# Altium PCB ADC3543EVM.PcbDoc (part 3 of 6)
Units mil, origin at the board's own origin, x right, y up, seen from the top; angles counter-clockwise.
Board outline 3900 x 2716.54 mil, 10 copper layers (Top Layer, L2 GND, L3 PWR, L4 GND, L5 SIG, L6 GND, L7 GND, L8 PWR, L9 GND, Bottom Layer), stack 61.2 mil thick; 352 components, 249 nets, 1505 pads, 904 vias.

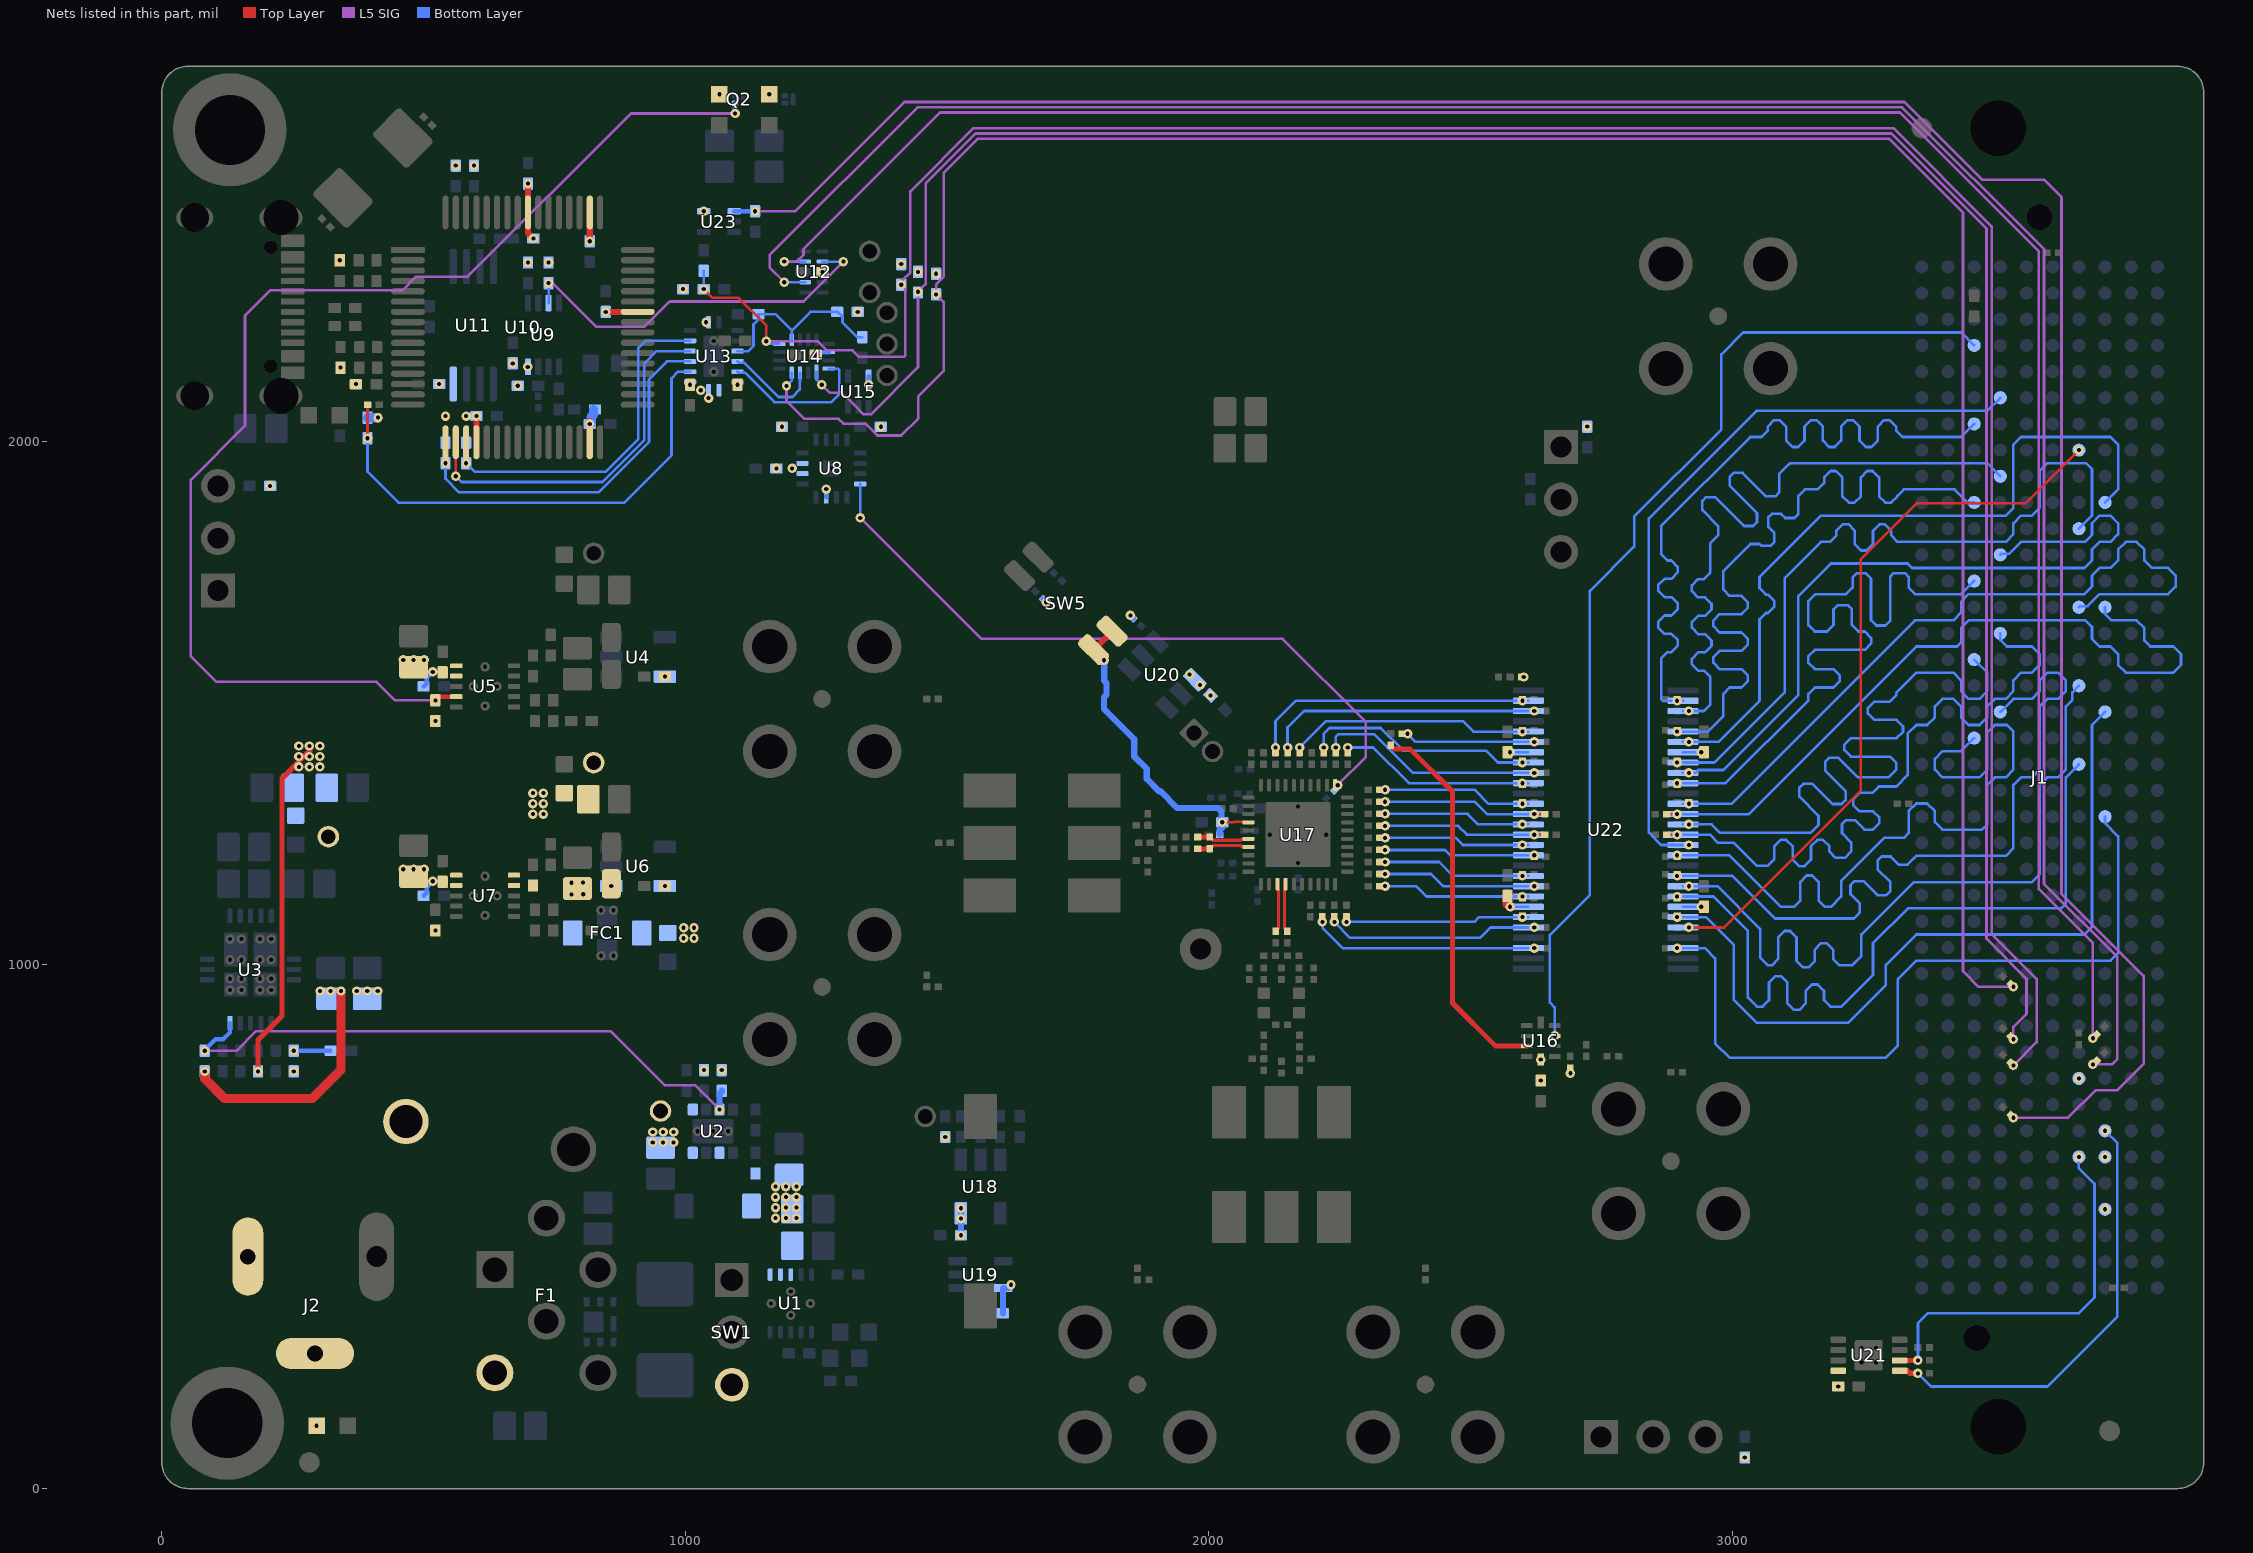
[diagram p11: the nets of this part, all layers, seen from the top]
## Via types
v1: diameter 18, hole 8, Top Layer to Bottom Layer, tented both sides, 891 vias
v2: diameter 40, hole 20, Top Layer to Bottom Layer, tented both sides, 9 vias
v3: diameter 18, hole 8, Top Layer to Bottom Layer, tented bottom, 4 vias

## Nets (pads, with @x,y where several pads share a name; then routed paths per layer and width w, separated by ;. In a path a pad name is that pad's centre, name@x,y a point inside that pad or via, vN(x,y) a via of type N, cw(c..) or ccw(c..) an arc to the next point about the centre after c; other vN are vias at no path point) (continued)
1p8V_BUFVCC: C29.2 C81.2 C82.2 C83.2 C84.2 FC1.3 R138.2 U22.7 U22.22 U22.35 U22.50 | length 181.9
  Top Layer w5: C81.2@2570,1406.28 v1(2575,1406.28) ; v1(2940.28,1111) C83.2@2945.28,1111 ; v1(2940.28,1406.28) C82.2@2945.28,1406.28
  Top Layer w8: R138.2@2597.05,1550 v1(2601.05,1550)
  Top Layer w18: C84.2@2570,1131.85 2570,1116 v1(2575,1111)
  Bottom Layer w5: v1(2575,1111) U22.35@2610,1111 ; v1(2575,1406.28) U22.50@2610,1406.28 ; U22.22@2905.28,1111 v1(2940.28,1111) ; U22.7@2905.28,1406.28 v1(2940.28,1406.28)
  other v1: 996.48,1051.05 1016.48,1051.05 996.48,1071.05 1016.48,1071.05
1p8V_IOVDD: C27.2 C69.2 FB3.2 PP4.1 U8.4 U17.31 | length 1351.9
  Top Layer w5: U17.31@2240.81,1343.29 v1(2245.81,1343.29)
  L5 SIG w5: v1(1334.01,1853.77) 1565.07,1622.71 2140.67,1622.71 2299.43,1463.94 2299.43,1396.91 v1(2245.81,1343.29)
  Bottom Layer w5: v1(1334.01,1853.77) U8.4@1334.01,1918.77
  Bottom Layer w8: C69.2@2239.47,1333.78 2245.81,1340.12 v1(2245.81,1343.29)
  other v1: 708.74,1288.25 728.74,1288.25 708.74,1308.25 728.74,1308.25 708.74,1328.25 728.74,1328.25
1p8V_LVLSHIFT: C26.2 C47.2 C73.2 FC1.1 R26.1 R27.2 R55.1 R58.2 R59.2 R60.2 R69.2 R96.2 R110.2 R112.1 R120.2 R148.1 U6.1 U7.9 U7.10 U13.15 U15.5 U18.5 U19.5 U23.5 | length 158.5
  Top Layer w5: v1(2690.22,793.22) R69.2@2690.22,803.22
  Bottom Layer w5: v1(1099.53,2108.3) U13.15@1099.53,2113.3
  Bottom Layer w9: v1(1350,2108.49) U15.5@1350,2124.23
  Bottom Layer w12: C73.2@1526.23,483.68 v1(1526.21,535.51) ; R112.1@1606.46,334.78 1606.69,335.01 1606.69,382.82 U19.5@1606.92,383.05 1615.82,383.05 ccw(c1615.82,389.15) 1616.84,383.13 U19.5@1621.84,388.13 ; R120.2@1683.8,1697.91 1688.18,1693.52 1689.41,1693.52 v1(1688.8,1692.91) ; U19.5@1621.84,388.13 ccw(c1615.82,389.15) v1(1621.93,389.15) 1621.93,388.22 U19.5@1621.84,388.13
  other v1: 1526.26,483.65 1526.21,515.51 1496.21,671.34 782.74,1134.69 805,1135 858.46,1150.75 782.43,1156.95 804.69,1157.26 2722.46,2028.25 1329.09,2247.34 995.55,2290.74 1478.89,2320.15 1444.21,2323.69 1412.13,2338.64 1034.92,2439.48
2p3V: C14.2 C15.2 C18.2 C19.2 C24.2 C25.2 FB1.2 PP2.1 R11.2 R15.2 R25.2 U5.1 U5.2 U7.1 U7.2 | length 854.7
  Top Layer w8: v1(460.98,1182.66) 474.98,1168.66 C24.2@480.98,1168.66 ; v1(460.98,1582.66) 474.98,1568.66 C18.2@480.98,1568.66 ; v1(480.98,1182.66) C24.2@480.98,1168.66 ; v1(480.98,1582.66) C18.2@480.98,1568.66 ; v1(500.98,1182.66) 486.98,1168.66 C24.2@480.98,1168.66 ; v1(500.98,1582.66) 486.98,1568.66 C18.2@480.98,1568.66
  Top Layer w10: v1(183.89,796.75) 183.89,856.68 229.77,902.57 229.77,1356.43 282.4,1409.06
  Bottom Layer w8: R25.2@499.93,1132.05 500.25,1132.05 506.09,1137.89 506.09,1148.51 v1(517.4,1159.81) ; R15.2@499.93,1532.05 500.25,1532.05 506.09,1537.89 506.09,1548.51 v1(517.4,1559.81)
  other v1: 261.89,1378.18 281.89,1378.18 301.89,1378.18 261.89,1398.18 281.89,1398.18 301.89,1398.18 261.89,1418.18 281.89,1418.18 301.89,1418.18
3p3V_AUX: J1.D32
  other v1: 3661.42,783.27
3p3V_EEPROM: C80.2 U21.8
  other v1: 3201.8,194.99
3p3V_Utility: C7.2 C17.2 C23.2 C30.2 C31.2 C37.2 C38.2 C39.2 C40.2 C41.2 C42.2 C45.2 C46.2 C48.2 C56.2 C77.2 FB4.1 FB5.1 PP1.1 R5.2 R7.2 R9.2 R14.2 R23.2 R31.2 R32.2 R33.2 R34.1 R36.2 R37.1 R40.2 R46.2 R47.2 R48.2 R50.2 R51.2 R52.2 R53.2 R72.2 R121.2 U2.4 U2.5 U4.5 U6.5 U8.7 U8.10 U8.11 U9.8 U10.20 U10.31 U10.42 U10.50 U10.56 U11.8 U12.8@1261.85,2323.6 U13.1 U13.2 U13.8 U13.16 U14.14 U16.10 U20.4 | length 426.6
  Top Layer w11: v1(847.98,2247.34) U10.42@908.98,2247.34
  Top Layer w12: U10.20@600.91,1998.32 v1(600.91,2048.32) ; v1(699.33,2492.3) U10.56@699.33,2437.3 699.33,2397.82 v1(709.66,2387.5) ; U10.31@817.44,1998.32 v1@817.44,2038.32 ; v1(817.44,2382.3) U10.50@817.44,2437.3
  Bottom Layer w5: v1(1008.98,2108.3) U13.2@1008.98,2113.3 ; v1(1039.41,2227.47) U13.8@1044.41,2227.47
  Bottom Layer w8: v1(1249.02,2165.39) 1251.72,2165.39 1256.72,2170.39 U14.14@1274.02,2170.39
  Bottom Layer w9: U8.7@1269.05,1893.18 v1(1269.05,1908.92)
  Bottom Layer w12: v1(1849.99,1667.72) R121.2@1854.99,1662.72
  Bottom Layer w18: R51.2@392.95,2045.32 v1(412.95,2045.32) ; v1(817.44,2033.32) 819.41,2033.32 820.25,2034.16 820.25,2047 824.48,2051.23 R37.1@824.48,2060.88
  other v1: 3023.45,59.35 937.5,660.99 957.5,660.99 977.5,660.99 937.5,680.99 957.5,680.99 977.5,680.99 2633.64,779.36 251.89,796.75 1035.7,799.2 1069.29,799.2 2633.64,819.36 522.48,1065.91 960.83,1150.75 522.48,1465.91 2002.96,1514.75 1982.96,1534.75 960.83,1550.75 1962.96,1554.75 206.85,1915 1173.78,1948.29 1203.78,1948.29 1184.41,2027.82 1373.38,2027.82 541.85,2048.32 581.22,2048.32 1044.41,2082.55 1029.41,2097.55 679.65,2106.22 370.63,2109.54 529.61,2109.54 341.37,2140.87 699.03,2142.22 670.29,2148.91 1261.85,2323.6 699.33,2341.64 738.7,2341.64 340,2345.76 561.54,2526.67 596.22,2526.67
3p3VU_PG: R5.1 R10.1 U2.7 U3.24 | length 1180.4
  L5 SIG w5: v1(81.89,836.12) 142.5,836.12 179.96,873.58 857.24,873.58 960.83,770 1019.12,770 v1(1065.29,723.83)
  Bottom Layer w8: v1(81.89,836.12) 81.89,838.09 87.73,843.93 88.74,843.93 103.07,858.26 117.42,858.26 130.21,871.05 U3.24@130.21,888.94
  Bottom Layer w12: v1(1065.29,723.83) 1065.29,753.86 1069.29,757.86 R5.1@1069.29,759.83
12V: C2.2 C3.2 C6.2 C9.2 C10.2 D1.1 D3.1 D4.1 D5.1 R6.2 R10.2 U1.6 U1.7 U1.8 U2.2 U3.18 | length 462.9
  Top Layer w18: v1(81.89,796.75) 81.89,783.11 120,745 287.48,745 342.26,799.78 v1(342.26,950.2)
  other v1: 295.33,119.85 1172.07,516.64 1192.07,516.64 1212.07,516.64 1172.07,536.64 1192.07,536.64 1212.07,536.64 1172.07,556.64 1192.07,556.64 1212.07,556.64 1172.07,576.64 1192.07,576.64 1212.07,576.64 302.26,950.2 322.26,950.2 372.26,950.2 392.26,950.2 412.26,950.2 1065,2663.11 1160,2663.11
12V_FMC: J1.C35 J1.C37 SW1.3
  other v1: 3711.42,533.27 3711.42,633.27
AIN_N: R84.2 U17.14 | length 93.3
  Top Layer w6.1: U17.14@2146.32,1154.31 2146.32,1146.44 2144,1144.11 2144,1070.85 2149.75,1065.1 R84.2@2149.75,1064.31
AIN_P: R76.2 U17.13 | length 93.3
  Top Layer w6.1: R76.2@2127.15,1064.31 2127.15,1065.1 2132.9,1070.85 2132.9,1144.11 2130.57,1146.44 U17.13@2130.57,1154.31
AVDD_PG: Q2.1@1095,2646.22 R14.1 U5.4 | length 2355.2
  Top Layer w8: v1(522.48,1505.28) 522.48,1506.52 528.32,1512.36 U5.4@562.48,1512.36
  L5 SIG w5: v1(522.48,1505.28) 445.42,1505.28 410,1540.7 104.24,1540.7 55.51,1589.43 55.51,1926.56 158.81,2029.87 158.81,2240.25 206.85,2288.29 459.46,2288.29 485.67,2314.49 584.28,2314.49 896.01,2626.22 v1(1095,2626.22)
  Bottom Layer w9.7: v1(1095,2626.22) Q2.1@1095,2646.22
CLK_N: C55.2 R65.1 U17.7 | length 100.5
  Top Layer w6.1: R65.1@2001.99,1221.75 2008.24,1228 2039.34,1228 2060.84,1228 2062.78,1226.06 2074.57,1226.06 U17.7@2075.45,1225.18
  Top Layer w9.7: C55.2@1978.2,1221.75 1994.35,1221.75 1994.9,1222.3 R65.1@2001.2,1222.3
CLK_P: C49.2 R65.2 U17.6 | length 101
  Top Layer w6.1: R65.2@2001.2,1244.35 2001.99,1244.35 2008.24,1238.1 2035.16,1238.1 2060.84,1238.1 2062.78,1240.04 2074.57,1240.04 U17.6@2075.45,1240.92
  Top Layer w9.7: C49.2@1978.2,1244.35 R65.2@2001.2,1244.35
CTRL: C78.2 C79.2 SW5.3 SW5.4 U17.4 | length 608.6
  Top Layer w5: v1(2025.45,1272.42) 2047.87,1272.42 2048.62,1273.17 2062.29,1273.17 2063.04,1272.42 U17.4@2075.45,1272.42
  Top Layer w12: v1(1799.63,1582.07) SW5.4@1779.63,1602.07 1790.21,1612.65 SW5.3@1814.99,1637.43
  Bottom Layer w12: v1@1799.8,1582.1 1799.8,1542.89 1804.28,1538.42 1804.28,1516.25 1799.37,1511.34 1799.37,1489.17 1857.18,1431.36 1857.18,1398.19 1880.89,1374.48 1880.89,1355.37 1904.59,1331.66 1907.61,1331.66 1939.61,1299.66 2006.69,1299.66 2006.93,1299.91 2016.93,1299.91 2023.96,1292.88 2023.96,1273.92 v1(2025.45,1272.42) 2025.45,1262.58 2020.45,1257.58 C79.2@2020.45,1249.42
D0: J1.H7 R140.2 U22.2 | length 1436.9
  Bottom Layer w5: U22.2@2905.28,1504.7 v1(2893.99,1504.7) 2866.64,1504.7 2863.71,1507.63 2863.71,1547.76 2863.71,1585.26 2875.96,1597.51 2883.21,1597.51 2895.46,1609.76 2895.46,1620.26 2883.21,1632.51 2870.16,1632.51 2857.91,1644.76 2857.91,1655.26 2870.16,1667.51 2883.21,1667.51 2895.46,1679.76 2895.46,1690.26 2883.21,1702.51 2870.16,1702.51 2857.91,1714.76 2857.91,1725.26 2870.16,1737.51 2882.98,1737.51 2895.23,1749.76 2895.23,1760.26 2882.98,1772.51 2875.96,1772.51 2863.71,1784.76 2863.71,1808.27 2863.71,1838.07 3033.91,2008.27 3052.59,2008.27 3055.09,2008.27 3067.34,2020.52 3067.34,2028.28 3079.59,2040.53 3090.09,2040.53 3102.34,2028.28 3102.34,2001.39 3114.59,1989.14 3125.09,1989.14 3137.34,2001.39 3137.34,2028.28 3149.59,2040.53 3160.09,2040.53 3172.34,2028.28 3172.34,2001.39 3184.59,1989.14 3195.09,1989.14 3207.34,2001.39 3207.34,2028.28 3219.59,2040.53 3230.09,2040.53 3242.34,2028.28 3242.34,2001.39 3254.59,1989.14 3265.09,1989.14 3277.34,2001.39 3277.34,2028.28 3289.59,2040.53 3300.09,2040.53 3312.34,2028.28 3312.34,2020.52 3324.59,2008.27 3361.42,2008.27 3436.42,2008.27 J1.H7@3461.42,2033.27
D1: J1.G9 R142.2 U22.3 | length 1436.9
  Bottom Layer w5: U22.3@2905.28,1485.02 v1(2916.56,1485.02) 2945.02,1485.02 2957.51,1497.51 2957.51,1547.2 2957.51,1549.7 2945.26,1561.95 2934.35,1561.95 2922.1,1574.2 2922.1,1584.7 2934.35,1596.95 2947.45,1596.95 2959.7,1609.2 2959.7,1619.7 2947.45,1631.95 2934.35,1631.95 2922.1,1644.2 2922.1,1654.7 2934.35,1666.95 2947.45,1666.95 2959.7,1679.2 2959.7,1689.7 2947.45,1701.95 2934.35,1701.95 2922.1,1714.2 2922.1,1724.7 2934.35,1736.95 2945.26,1736.95 2957.51,1749.2 2957.51,1797.33 2957.51,1805.77 2970.87,1819.13 2972.64,1820.9 2972.64,1838.22 2942.16,1868.7 2942.16,1886.02 2949.59,1893.44 2966.91,1893.44 3021.98,1838.37 3039.31,1838.37 3046.73,1845.8 3046.73,1863.12 2994.66,1915.19 2994.66,1932.52 3002.09,1939.94 3019.41,1939.94 3064.21,1895.15 3081.53,1895.15 3088.95,1902.57 3088.95,1919.9 3088.95,1937.22 3108.09,1956.35 3110,1958.27 3486.42,1958.27 J1.G9@3511.42,1933.27
D2: J1.H10 R144.2 U22.5 | length 1436.9
  Bottom Layer w5: U22.5@2905.28,1445.65 2952.69,1445.65 2982.27,1475.22 2982.27,1480.24 2982.27,1517.74 2994.52,1529.99 3017.1,1529.99 3029.35,1542.24 3029.35,1552.74 3017.1,1564.99 2975.47,1564.99 2963.22,1577.24 2963.22,1587.74 2975.47,1599.99 3017.1,1599.99 3029.35,1612.24 3029.35,1622.74 3017.1,1634.99 2975.47,1634.99 2963.22,1647.24 2963.22,1657.74 2975.47,1669.99 3017.1,1669.99 3029.35,1682.24 3029.35,1692.74 3017.1,1704.99 2994.52,1704.99 2982.27,1717.24 2982.27,1719.89 2982.27,1752.26 3007.54,1777.53 3034.06,1804.05 3051.38,1804.05 3054.9,1800.53 3072.22,1800.53 3079.65,1807.96 3079.65,1825.28 3067.98,1836.95 3067.98,1854.27 3075.4,1861.7 3092.73,1861.7 3100.88,1853.55 3118.2,1853.55 3125.63,1860.97 3125.63,1878.29 3125.63,1895.62 3138.27,1908.27 3139.36,1908.27 3160.09,1908.27 3162.59,1908.27 3174.84,1920.52 3174.84,1931.16 3187.09,1943.41 3197.59,1943.41 3209.84,1931.16 3209.84,1895.14 3222.09,1882.89 3232.59,1882.89 3244.84,1895.14 3244.84,1931.16 3257.09,1943.41 3267.59,1943.41 3279.84,1931.16 3279.84,1895.14 3292.09,1882.89 3302.59,1882.89 3314.84,1895.14 3314.84,1896.02 3327.09,1908.27 3348.03,1908.27 3423.82,1908.27 3448.82,1883.27 J1.H10@3461.42,1883.27
  other v1: 2893.99,1445.65
D3: J1.C10 R146.2 U22.6 | length 1436.9
  Bottom Layer w5: U22.6@2905.28,1425.96 v1(2916.56,1425.96) 2973.17,1425.96 3051.38,1504.17 3051.38,1622.51 3051.38,1660.01 3063.63,1672.26 3067.7,1672.26 3079.95,1684.51 3079.95,1695.01 3067.7,1707.26 3063.63,1707.26 3051.38,1719.51 3051.38,1733.05 3051.38,1740.84 3168.81,1858.27 3521.77,1858.27 3536.42,1872.91 3536.42,1886.02 3536.42,1993.62 3551.06,2008.27 3721.77,2008.27 3736.42,1993.62 3736.42,1908.27 J1.C10@3711.42,1883.27
D4: J1.D11 R151.2 U22.8 | length 1436.9
  Bottom Layer w5: U22.8@2905.28,1386.59 2965.15,1386.59 3100,1521.44 3100,1739.28 3168.98,1808.27 3183.47,1808.27 3185.97,1808.27 3198.22,1820.52 3198.22,1829.54 3210.47,1841.79 3220.97,1841.79 3233.22,1829.54 3233.22,1803.93 3245.47,1791.68 3255.97,1791.68 3268.22,1803.93 3268.22,1829.12 3280.47,1841.37 3290.97,1841.37 3303.22,1829.12 3303.22,1820.52 3315.47,1808.27 3361.1,1808.27 3521.77,1808.27 3536.42,1822.91 3536.42,1843.62 3551.07,1858.27 3571.77,1858.27 3586.42,1872.92 3586.42,1943.62 3601.07,1958.27 3675.16,1958.27 3686.42,1947.01 3686.42,1858.27 J1.D11@3661.42,1833.27
  other v1: 2893.99,1386.59
D5: J1.G12 R153.2 U22.9 | length 1446.1
  Bottom Layer w5: U22.9@2905.28,1366.91 2928.9,1366.91 2934.28,1372.29 2982.23,1372.29 3125.63,1515.7 3125.63,1704.82 3187.64,1766.83 3334.51,1766.83 3343.07,1758.27 3671.77,1758.27 3686.42,1772.91 3686.42,1793.62 3701.06,1808.27 3721.77,1808.27 3736.42,1822.91 3736.42,1843.62 3721.77,1858.27 3701.06,1858.27 3686.42,1843.62 3686.42,1821.1 3673.58,1808.27 3551.06,1808.27 3527.95,1785.16 3513.31,1785.16 J1.G12@3511.42,1783.27
  other v1: 2916.56,1366.91
D6: J1.H13 R155.2 U22.10 | length 1441.3
  Bottom Layer w5: U22.10@2905.28,1347.22 2986.88,1347.22 3144.84,1505.19 3144.84,1517.69 3157.09,1529.94 3192.59,1529.94 3204.84,1542.19 3204.84,1552.69 3192.59,1564.94 3157.09,1564.94 3144.84,1577.19 3144.84,1589.69 3157.09,1601.94 3252.59,1601.94 3264.84,1614.19 3264.84,1624.69 3252.59,1636.94 3240.09,1636.94 3227.84,1649.19 3227.84,1679.63 3220.53,1686.94 3200.67,1686.94 3192.84,1679.11 3192.84,1649.19 3180.59,1636.94 3157.09,1636.94 3144.84,1649.19 3144.84,1694.89 3158.22,1708.27 3217.09,1708.27 3229.34,1720.52 3229.34,1739.75 3237.86,1748.27 3253.9,1748.27 3264.34,1737.82 3264.34,1658.62 3274.7,1648.27 3291.7,1648.27 3301.35,1657.92 3301.35,1741.92 3307.69,1748.27 3328.98,1748.27 3336.35,1740.9 3336.35,1720.52 3348.6,1708.27 3436.42,1708.27 J1.H13@3461.42,1733.27
  other v1: 2893.99,1347.22
D7: J1.D14 R157.2 U22.12 | length 1446.1
  Bottom Layer w5: U22.12@2905.28,1307.85 v1(2916.56,1307.85) 2997.92,1307.85 3348.33,1658.27 3421.77,1658.27 3436.42,1672.91 3436.42,1693.62 3451.07,1708.27 3671.77,1708.27 3686.42,1722.91 3686.42,1743.62 3701.06,1758.27 3721.77,1758.27 3736.42,1772.91 3736.42,1793.62 3751.06,1808.27 3771.77,1808.27 3786.42,1793.62 3786.42,1772.51 3800.66,1758.27 3831.77,1758.27 3846.42,1743.62 3846.42,1722.91 3831.77,1708.27 3702.95,1708.27 3701.06,1708.27 3677.95,1685.16 3663.31,1685.16 J1.D14@3661.42,1683.27
D8: J1.C14 R159.2 U22.13 | length 1437.9
  Top Layer w5: R159.2@2873.99,1288.17 v1(2893.99,1288.17)
  Bottom Layer w5: U22.13@2905.28,1288.17 3030.96,1288.17 3351.07,1608.27 3428.88,1608.27 3436.42,1615.81 3436.42,1643.62 3451.07,1658.27 3511.41,1658.27 3673.82,1658.27 3686.42,1645.66 3686.42,1622.91 3701.07,1608.27 3721.77,1608.27 3736.42,1593.62 3736.42,1572.92 3751.06,1558.27 3841.77,1558.27 3856.42,1572.91 3856.42,1593.62 3841.77,1608.27 3797.85,1608.27 3786.42,1619.7 3786.42,1643.62 3771.77,1658.27 3723.82,1658.27 3711.42,1670.67 J1.C14@3711.42,1683.27
D9: J1.H16 R161.2 U22.14 | length 1438.9
  Bottom Layer w5: U22.14@2905.28,1268.48 v1(2916.56,1268.48) 2959.81,1268.48 2975.47,1252.83 3149.51,1252.83 3162.4,1265.71 3164.17,1267.48 3164.17,1284.81 3127.66,1321.32 3127.66,1338.64 3135.08,1346.07 3152.41,1346.07 3191.16,1307.31 3208.49,1307.31 3215.91,1314.73 3215.91,1332.06 3177.16,1370.81 3177.16,1388.14 3184.58,1395.56 3201.9,1395.56 3239.2,1358.27 3264.34,1358.27 3298.13,1358.27 3312.78,1372.92 3312.78,1383.27 3312.78,1385.77 3300.53,1398.02 3225.84,1398.02 3213.59,1410.27 3213.59,1420.77 3225.84,1433.02 3313.26,1433.02 3325.51,1445.27 3325.51,1455.77 3313.26,1468.02 3270.79,1468.02 3258.54,1480.27 3258.54,1490.77 3270.79,1503.02 3300.53,1503.02 3312.78,1515.27 3312.78,1518.58 3312.78,1519.98 3351.07,1558.27 3421.77,1558.27 3436.42,1543.62 3436.42,1522.92 3451.06,1508.27 3471.77,1508.27 3486.42,1522.92 3486.42,1558.27 J1.H16@3461.42,1583.27
D10: J1.G15 R163.2 U22.15 | length 1444.1
  Top Layer w5: R163.2@2873.99,1248.8 v1(2893.99,1248.8)
  Bottom Layer w5: U22.15@2905.28,1248.8 2957.11,1248.8 2972.64,1233.27 3002.62,1233.27 3046.14,1189.74 3067.5,1189.74 3079.75,1201.99 3079.75,1226.79 3092,1239.04 3102.5,1239.04 3114.75,1226.79 3114.75,1201.02 3127,1188.77 3137.5,1188.77 3149.75,1201.02 3149.75,1226.79 3162,1239.04 3172.5,1239.04 3184.75,1226.79 3184.75,1216.9 3197,1204.65 3214.32,1204.65 3226.57,1216.9 3226.57,1234.22 3209.04,1251.76 3209.04,1269.08 3216.47,1276.51 3233.79,1276.51 3252.01,1258.29 3267.96,1258.29 3280.47,1270.79 3280.47,1281.29 3268.22,1293.54 3242.45,1293.54 3230.2,1305.79 3230.2,1316.29 3242.45,1328.54 3267.25,1328.54 3279.5,1340.79 3312.78,1340.79 3334.51,1362.53 3334.51,1441.71 3351.06,1458.27 3371.77,1458.27 3386.42,1472.91 3386.42,1493.62 3401.06,1508.27 3421.77,1508.27 3436.42,1493.62 3436.42,1472.91 3451.07,1458.27 3471.77,1458.27 3486.42,1472.91 3486.42,1493.62 3501.07,1508.27 3521.77,1508.27 3536.42,1522.91 3536.42,1543.62 3551.06,1558.27 3571.77,1558.27 3586.42,1572.91 3586.42,1593.62 3571.77,1608.27 3551.06,1608.27 3523.82,1608.27 3511.42,1620.67 J1.G15@3511.42,1633.27
D11: J1.H19 R167.2 U22.17 | length 1439.9
  Bottom Layer w5: U22.17@2905.28,1209.43 2993.71,1209.43 3092.14,1111 3114.59,1111 3117.09,1111 3129.34,1123.25 3129.34,1158.6 3141.59,1170.85 3152.09,1170.85 3164.34,1158.6 3164.34,1123.25 3176.59,1111 3182.82,1111 3187.66,1111 3207.34,1130.69 3207.34,1160.52 3289.59,1242.77 3289.69,1242.67 3327.09,1242.67 3336.42,1252 3336.42,1293.62 3351.06,1308.27 3371.77,1308.27 3386.42,1293.62 3386.42,1272.91 3401.06,1258.27 3411.41,1258.27 3476.2,1258.27 3486.42,1268.48 3486.42,1343.62 3501.07,1358.27 3521.77,1358.27 3536.42,1372.91 3536.42,1445.65 3523.8,1458.27 3501.06,1458.27 3486.42,1443.62 3486.42,1372.92 3471.77,1358.27 3461.42,1358.27 3401.06,1358.27 3386.42,1372.91 3386.42,1393.62 3401.07,1408.27 3436.42,1408.27 J1.H19@3461.42,1433.27
  other v1: 2893.99,1209.43
D12: J1.G18 R169.2 U22.19 | length 1439.9
  Bottom Layer w5: U22.19@2905.28,1170.06 2999.74,1170.06 3081.08,1088.72 3231.52,1088.72 3241.17,1098.38 3242.94,1100.14 3242.94,1117.47 3225.23,1135.18 3225.23,1152.5 3232.65,1159.93 3249.98,1159.93 3276.47,1133.44 3293.79,1133.44 3301.22,1140.87 3301.22,1158.19 3277.11,1182.3 3277.11,1199.62 3284.53,1207.05 3301.86,1207.05 3317.19,1191.71 3334.51,1191.71 3346.93,1204.13 3351.07,1208.27 3521.77,1208.27 3536.42,1222.91 3536.42,1343.62 3551.06,1358.27 3571.77,1358.27 3586.42,1372.92 3586.42,1493.62 3601.07,1508.27 3621.77,1508.27 3636.42,1522.91 3636.42,1543.62 3621.77,1558.27 3601.07,1558.27 3586.42,1543.62 3586.42,1522.92 3571.77,1508.27 3536.42,1508.27 J1.G18@3511.42,1483.27
  other v1: 2893.99,1170.06
D13: J1.D17 R171.2 U22.20 | length 1440.8
  Bottom Layer w5: U22.20@2905.28,1150.37 v1(2916.56,1150.37) 2970.87,1150.37 3052.59,1068.65 3052.59,1014.37 3067.7,999.26 3072.34,999.26 3074.84,999.26 3087.09,1011.51 3087.09,1052.6 3099.34,1064.85 3109.84,1064.85 3122.09,1052.6 3122.09,1007.71 3134.34,995.46 3144.84,995.46 3157.09,1007.71 3157.09,1029.22 3169.34,1041.47 3179.84,1041.47 3192.09,1029.22 3192.09,1011.51 3204.34,999.26 3228.12,999.26 3232.59,1003.73 3246.08,1017.22 3246.08,1058.27 3346.08,1158.27 3401.06,1158.27 3571.77,1158.27 3586.42,1172.92 3586.42,1343.62 3601.07,1358.27 3621.77,1358.27 3636.42,1372.91 3636.42,1412.56 3636.42,1493.62 3648.82,1506.02 3648.82,1520.67 J1.D17@3661.42,1533.27
D14: J1.D20 R173.2 U22.21 | length 1441.1
  Bottom Layer w5: U22.21@2905.28,1130.69 2963.22,1130.69 3029.35,1064.56 3029.35,937.87 3046.73,920.49 3054.9,920.49 3057.4,920.49 3069.65,932.74 3069.65,966.38 3081.9,978.63 3092.4,978.63 3104.65,966.38 3104.65,926.67 3116.9,914.42 3127.4,914.42 3139.65,926.67 3139.65,950.41 3151.9,962.66 3162.4,962.66 3174.65,950.41 3174.65,932.74 3186.9,920.49 3202.19,920.49 3207.79,920.49 3268.22,980.92 3268.22,1041.52 3334.97,1108.27 3627.31,1108.27 3636.42,1117.37 3636.42,1358.27 J1.D20@3661.42,1383.27
  other v1: 2893.99,1130.69
D15: J1.C18 R175.2 U22.23 | length 1444.9
  Bottom Layer w5: U22.23@2905.28,1091.32 2949.59,1091.32 3002.09,1038.82 3002.09,934.32 3047.01,889.4 3220.05,889.4 3292.8,962.15 3292.8,1000.01 3351.07,1058.27 3671.77,1058.27 3686.42,1072.91 3686.42,1458.27 J1.C18@3711.42,1483.27
  other v1: 2893.99,1091.32
D16/FCLK: J1.D8 R177.2 U22.24 | length 1381.5
  Top Layer w5: v1(2916.56,1071.63) 2983.81,1071.63 3245,1332.82 3245,1775 3352.04,1882.04 3560.19,1882.04 v1(3661.42,1983.27)
D17: J1.C22 R179.2 U22.26 | length 1440.9
  Bottom Layer w5: U22.26@2905.28,1032.26 2947.23,1032.26 2966.91,1012.58 2966.91,850.46 2994.52,822.85 3292.8,822.85 3315.47,845.52 3315.47,972.67 3351.06,1008.27 3721.77,1008.27 3736.42,1022.91 3736.42,1245.67 3711.42,1270.67 J1.C22@3711.42,1283.27
  other v1: 2893.99,1032.26
DC-DC_PG: R9.1 R22.2 U3.19 | length 70.2
  Bottom Layer w8: v1(251.89,836.12) R22.2@322.11,836.12
DCLK: J1.G6 R165.2 U22.16 | length 1441.9
  Bottom Layer w5: U22.16@2905.28,1229.11 2863.71,1229.11 2840,1252.83 2840,1852.7 3045.56,2058.27 3486.42,2058.27 J1.G6@3511.42,2083.27
  other v1: 2916.56,1229.11
DCLKIN: R117.1 U16.8 | length 734.7
  Top Layer w9.7: R117.1@2347.23,1419.45 2347.23,1418.66 2353.16,1412.73 2383.41,1412.73 2465,1331.15 2465,927.49 2547.53,844.95 U16.8@2607.07,844.95
DUT_D0: R88.2 R139.1 U22.55 | length 559.4
  Top Layer w5: R88.2@2127.07,1405.33 v1(2127.07,1415.33)
  Bottom Layer w5: v1(2127.07,1415.33) 2127.07,1465.57 2166.2,1504.7 U22.55@2610,1504.7
  other v1: 2598.72,1504.7
DUT_D1: R90.2 R141.1 U22.54 | length 521.3
  Top Layer w5: R90.2@2150.07,1405.33 v1(2150.07,1415.33)
  Bottom Layer w5: v1(2150.07,1415.33) 2150.07,1453.7 2181.39,1485.02 U22.54@2610,1485.02
  other v1: 2621.28,1485.02
DUT_D2: R91.2 R143.1 U22.52 | length 476
  Top Layer w5: R91.2@2173.07,1405.33 v1(2173.07,1415.33)
  Bottom Layer w5: v1(2173.07,1415.33) 2223.31,1465.57 2485,1465.57 2504.93,1445.65 U22.52@2610,1445.65
  other v1: 2598.72,1445.65
DUT_D4: R93.2 R150.1 U22.49 | length 458.7
  Top Layer w5: R93.2@2219.07,1405.33 v1(2219.07,1415.33)
  Bottom Layer w5: v1(2219.07,1415.33) 2219.07,1441.14 2230.41,1452.48 2327.77,1452.48 2371.08,1409.17 2529.22,1409.17 2551.8,1386.59 U22.49@2610,1386.59
  other v1: 2598.72,1386.59
DUT_D5: R94.2 R152.1 U22.48 | length 431
  Top Layer w5: R94.2@2242.07,1405.33 v1(2242.07,1415.33)
  Bottom Layer w5: v1(2242.07,1415.33) 2242.07,1435.67 2247.25,1440.85 2315.31,1440.85 2389.25,1366.91 U22.48@2610,1366.91
  other v1: 2621.28,1366.91
DUT_D6: R95.2 R154.1 U22.47 | length 383.1
  Top Layer w5: R95.2@2265.07,1405.33 v1(2265.07,1415.33)
  Bottom Layer w5: v1(2265.07,1415.33) 2313.7,1415.33 2381.81,1347.22 U22.47@2610,1347.22
  other v1: 2598.72,1347.22
DUT_D7: R97.2 R156.1 U22.45 | length 294.6
  Top Layer w5: R97.2@2326.48,1334.67 v1(2336.48,1334.67)
  Bottom Layer w5: v1(2336.48,1334.67) 2507.24,1334.67 2534.06,1307.85 U22.45@2610,1307.85
  other v1: 2598.72,1307.85
DUT_D8: R98.2 R158.1 U22.44 | length 313.3
  Top Layer w5: R98.2@2326.48,1311.67 v1(2336.48,1311.67) ; v1(2621.28,1288.17) R158.1@2641.28,1288.17
  Bottom Layer w5: v1(2336.48,1311.67) 2507.65,1311.67 2531.15,1288.17 U22.44@2610,1288.17
DUT_D9: R99.2 R160.1 U22.43 | length 291.9
  Top Layer w5: R99.2@2326.48,1288.67 v1(2336.48,1288.67)
  Bottom Layer w5: v1(2336.48,1288.67) 2493.85,1288.67 2514.04,1268.48 U22.43@2610,1268.48
  other v1: 2598.72,1268.48
DUT_D10: R100.2 R162.1 U22.42 | length 310.5
  Top Layer w5: R100.2@2326.48,1265.67 v1(2336.48,1265.67) ; v1(2621.28,1248.8) R162.1@2641.28,1248.8
  Bottom Layer w5: v1(2336.48,1265.67) 2476,1265.67 2492.87,1248.8 U22.42@2610,1248.8
DUT_D11: R101.2 R166.1 U22.40 | length 287.8
  Top Layer w5: R101.2@2326.48,1219.67 v1(2336.48,1219.67)
  Bottom Layer w5: v1(2336.48,1219.67) 2450.61,1219.67 2460.85,1209.43 U22.40@2610,1209.43
  other v1: 2621.28,1209.43
DUT_D12: R102.2 R168.1 U22.38 | length 294.5
  Top Layer w5: R102.2@2326.48,1196.67 v1(2336.48,1196.67)
  Bottom Layer w5: v1(2336.48,1196.67) 2439.79,1196.67 2466.41,1170.06 U22.38@2610,1170.06
  other v1: 2598.72,1170.06
DUT_D13: R103.2 R170.1 U22.37 | length 292.8
  Top Layer w5: R103.2@2326.48,1173.67 v1(2336.48,1173.67)
  Bottom Layer w5: v1@2336.81,1173.67 2423.87,1173.67 2447.17,1150.37 U22.37@2610,1150.37
  other v1: 2621.28,1150.37
DUT_D14: R104.2 R172.1 U22.36 | length 291.8
  Top Layer w5: R104.2@2326.48,1150.67 v1(2336.48,1150.67)
  Bottom Layer w5: v1(2336.48,1150.67) 2395.82,1150.67 2415.81,1130.69 U22.36@2610,1130.69
  other v1: 2598.72,1130.69
DUT_D15: R105.2 R174.1 U22.34 | length 361.2
  Top Layer w5: v1(2262.56,1082.26) R105.2@2262.56,1092.26
  Bottom Layer w5: v1(2262.56,1082.26) 2506.99,1082.26 2516.05,1091.32 U22.34@2610,1091.32
  other v1: 2598.72,1091.32
DUT_D16/FCLK: R106.2 R176.1 U22.33 | length 401.3
  Top Layer w5: v1(2239.56,1082.26) R106.2@2239.56,1092.26
  Bottom Layer w5: v1(2239.56,1082.26) 2239.56,1081.93 2269.55,1051.95 2517.94,1051.95 2537.63,1071.63 U22.33@2610,1071.63
  other v1: 2621.28,1071.63
DUT_D17: R107.2 R178.1 U22.31 | length 430.8
  Top Layer w5: v1(2216.56,1082.26) R107.2@2216.56,1092.26
  Bottom Layer w5: v1(2216.56,1082.26) 2217.58,1081.25 2217.58,1069.94 2255.26,1032.26 U22.31@2610,1032.26
  other v1: 2621.28,1032.26
DUT_DB1: R113.1 R145.1 U22.51 | length 247.2
  Top Layer w5: R113.1@2369.27,1441.5 v1(2379.27,1441.5)
  Bottom Layer w5: v1(2379.27,1441.5) 2394.81,1425.96 U22.51@2610,1425.96
  other v1: 2621.28,1425.96
DUT_DCLK: R87.2 R164.1 U22.41 | length 289.1
  Top Layer w5: R87.2@2326.48,1242.67 v1(2336.48,1242.67)
  Bottom Layer w5: v1(2336.48,1242.67) 2471.44,1242.67 2485,1229.11 U22.41@2610,1229.11
  other v1: 2598.72,1229.11
EXTGND: F1.3 J2.2 J2.3 TP2.1
FMC_C\S\_DUT_LVLS: R59.1 R133.1 U14.4 | length 4447.5
  Top Layer w5: R133.1@3531.71,962.97 v3(3536.42,958.27)
  L5 SIG w5: v1(1193.15,2106.02) 1193.15,2077.4 1227.45,2043.1 1292.36,2043.1 1301.74,2033.72 1344.15,2033.72 1366.55,2011.32 1412.13,2011.32 1444.85,2044.05 1444.85,2086.22 1493.1,2134.47 1493.1,2266.58 v1(1478.89,2280.78) 1478.89,2299.65 1493.39,2314.15 1493.39,2512.94 1558.54,2578.09 3298.99,2578.09 3440,2437.08 3440,988.27 3470,958.27 v3(3536.42,958.27)
  Bottom Layer w5: v1(1193.15,2106.02) 1203.15,2116.02 U14.4@1203.15,2131.02
FMC_I2C_SCL: R130.1 U12.4 | length 4395.1
  Top Layer w10: v1(3688.23,860.08) R130.1@3694.85,866.7
  L5 SIG w5: v1(1188.98,2343.28) 1212.63,2343.28 1225.48,2356.13 1225.48,2367.09 1486.47,2628.09 2620,2628.09 ; 2790,2628.09 2620,2628.09 ; v1(3688.23,860.08) 3688.23,1041.77 3584.92,1145.08 3584.92,2362.87 3319.7,2628.09 2620,2628.09
  Bottom Layer w5: v1(1188.98,2343.28) U12.4@1228.98,2343.28
FMC_I2C_SDA: R131.1 U12.2 | length 4601.8
  Top Layer w10: v1(3688.23,810.08) R131.1@3694.85,816.7
  L5 SIG w5: v1(1188.98,2303.91) 1161.11,2331.78 1161.11,2356.13 1443.06,2638.09 2620,2638.09 ; 2790,2638.09 2620,2638.09 ; v1(3688.23,810.08) 3724.99,810.08 3734.92,820 3734.92,1015.08 3594.92,1155.08 3594.92,2367.01 3323.84,2638.09 2620,2638.09
  Bottom Layer w5: v1(1188.98,2303.91) U12.2@1228.98,2303.91
FMC_SCLK_DUT_LVLS: R58.1 R134.1 U14.1 | length 4368.2
  Top Layer w5: R134.1@3531.71,862.97 v3(3536.42,858.27)
  L5 SIG w5: v1(1260.39,2107.99) 1275.83,2092.55 1299.42,2092.55 1322.51,2069.47 1340.35,2051.62 1354.11,2051.62 1444.21,2141.73 1444.21,2145.58 v1(1444.21,2285.78) 1458.71,2300.28 1458.71,2492.4 1554.39,2588.09 3303.13,2588.09 3484.92,2406.3 3484.92,1050.11 3561.42,973.61 3561.42,906.6 3536.42,881.6 v3(3536.42,858.27)
  Bottom Layer w5: U14.1@1250.39,2132.99 1250.39,2117.99 v1(1260.39,2107.99)
FMC_SDI_DUT: R136.1 R147.2 U23.1 | length 4715
  Top Layer w5: R136.1@3531.71,712.97 v3(3536.42,708.27)
  L5 SIG w5: v1(1133.18,2439.48) 1209.54,2439.49 1418.14,2648.09 3327.99,2648.09 3476.07,2500 3595.03,2500 3628.21,2466.83 3628.21,1135.94 3785,979.14 3785,811.05 3734.92,760.97 3693.8,760.97 3641.1,708.27 v3(3536.42,708.27)
  Bottom Layer w8: U23.1@1093.18,2439.48 v1(1133.18,2439.48)
FMC_SDO_DUT_LVLS: R60.1 R61.1 R135.1 R148.2 R149.2 U14.8 | length 4698.7
  Top Layer w5: v1(1034.92,2290.74) 1051.42,2274.24 1101.36,2274.24 1154.53,2221.08 v1(1154.53,2191.14) ; R135.1@3531.71,812.97 v3(3536.42,808.27)
  L5 SIG w5: v1(1154.53,2191.14) 1253.15,2191.14 1270.56,2173.73 1319.06,2173.73 1331.33,2161.47 1417.07,2161.47 1420,2164.39 1420,2289.84 1412.13,2297.71 v1(1412.13,2299.27) 1414.61,2301.75 1414.61,2307.78 1429.71,2322.88 1429.71,2477.54 1550.25,2598.09 3307.28,2598.09 3494.92,2410.44 3494.92,1059.36 3580.66,973.61 3580.66,852.51 v3(3536.42,808.27)
  Bottom Layer w5: v1(1034.92,2290.74) R149.2@1034.92,2325.74 ; v1(1154.53,2191.14) 1157.23,2191.14 1162.23,2186.14 U14.8@1179.53,2186.14
FPGA_DCLKIN: J1.H4 U16.3 | length 1951.4
  Bottom Layer w5: v1(2660.22,864.64) 2660.22,919.21 2651.1,928.33 2651.1,1057.29 2727.5,1133.69 2727.5,1714.36 2812.17,1799.03 2812.17,1856.43 2978.68,2022.94 2978.68,2166.38 3020.21,2207.91 3436.77,2207.91 J1.H4@3461.42,2183.27
FTDI_C\S\_DUT_LVLS: U13.13 U14.3 | length 185.1
  Bottom Layer w5: U13.13@1099.53,2152.67 1101.75,2150.45 1112.4,2150.45 1178.02,2084.83 1204.35,2084.83 1218.15,2098.63 1218.15,2112.85 1218.9,2113.6 U14.3@1218.9,2131.02
FTDI_CSB_SHIFT: R52.1 U10.17 U13.4 | length 721.2
  Top Layer w5: v1(541.85,1958.32) U10.17@541.85,1998.32
  Bottom Layer w5: v1(541.85,1958.32) 541.85,1928.79 567.97,1902.67 834.37,1902.67 930.46,1998.75 930.46,2118.54 964.59,2152.67 U13.4@1008.98,2152.67
FTDI_I2C_SCL: R34.2 U9.3 U12.7 | length 727.2
  L5 SIG w5: v1(738.7,2302.27) 741.19,2299.78 748.78,2299.78 829.55,2219.01 921.46,2219.01 969.54,2267.09 1225.86,2267.09 1276.35,2317.59 1276.35,2317.78 v1(1301.85,2343.28)
  Bottom Layer w5: U9.3@738.7,2264.27 v1(738.7,2302.27) ; U12.7@1261.85,2343.28 v1(1301.85,2343.28)
FTDI_SCLK_DUT_LVLS: U13.14 U14.16 | length 292
  Bottom Layer w5: U13.14@1099.53,2132.99 1101.25,2131.27 1113.79,2131.27 1170.23,2074.83 1278.9,2074.83 1293.81,2089.74 1293.81,2136.39 1291.31,2138.89 U14.16@1274.02,2138.89
FTDI_SCLK_SHIFT: R35.2 R51.1 U13.3 | length 958.4
  Top Layer w5: v1(392.95,2005.95) R35.2@392.95,2070.17
  Bottom Layer w5: v1(392.95,2005.95) 392.95,1942.05 452.01,1882.99 883.27,1882.99 973.36,1973.08 973.36,2120.3 986.05,2132.99 U13.3@1008.98,2132.99
FTDI_SDI_SHIFT: R53.1 U10.19 U13.6 | length 680.4
  Top Layer w5: v1(581.22,1958.32) U10.19@581.22,1998.32
  Bottom Layer w5: v1(581.22,1958.32) 597.72,1941.82 847.76,1941.82 910,2004.06 910,2178.45 923.59,2192.04 U13.6@1008.98,2192.04
FTDI_SDIO_DUT_LVLS: R55.2 R56.2 R57.1 U13.12 U14.9 | length 369.5
  Bottom Layer w5: U13.12@1099.53,2172.36 1120.1,2172.36 1130.05,2182.31 1130.05,2223.58 1139.66,2233.18 R57.1@1139.66,2243.02 1171.83,2243.02 1203.15,2211.7 ; U14.9@1203.15,2194.01 1203.15,2211.7 ; R56.2@1337.95,2199.01 1328.11,2199.01 1299.97,2227.15 1299.97,2238.07 1290.71,2247.34 1288.74,2247.34 1238.79,2247.34 1203.15,2211.7
FTDI_SDO_SHIFT: U10.18 U13.5 | length 701.3
  Top Layer w5: v1@561.54,1938.32 U10.18@561.54,1998.32
  Bottom Layer w5: v1(561.54,1933.32) 572.5,1922.36 841.33,1922.36 921.46,2002.48 921.46,2148.91 944.9,2172.36 U13.5@1008.98,2172.36
GA0_FMC: J1.C34 R124.2 U21.1 | length 848.2
  Top Layer w10: U21.1@3319.06,224.99 3333.82,224.99 3338.82,219.99 v1(3354.06,219.99)
  Bottom Layer w5: v1(3354.06,219.99) 3379.05,195 3601.42,195 3735,328.58 3735,659.69 v1(3711.42,683.27)
GA1_FMC: J1.D35 R125.2 U21.2 | length 744.5
  Top Layer w10: U21.2@3319.06,244.68 v1(3354.06,244.68)
  Bottom Layer w5: v1(3354.06,244.68) 3354.06,315.9 3373.15,335 3661.42,335 3691.32,364.9 3691.32,581.79 3661.42,611.69 v1(3661.42,633.27)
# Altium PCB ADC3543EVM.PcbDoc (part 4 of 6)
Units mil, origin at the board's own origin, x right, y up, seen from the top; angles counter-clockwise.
Board outline 3900 x 2716.54 mil, 10 copper layers (Top Layer, L2 GND, L3 PWR, L4 GND, L5 SIG, L6 GND, L7 GND, L8 PWR, L9 GND, Bottom Layer), stack 61.2 mil thick; 352 components, 249 nets, 1505 pads, 904 vias.

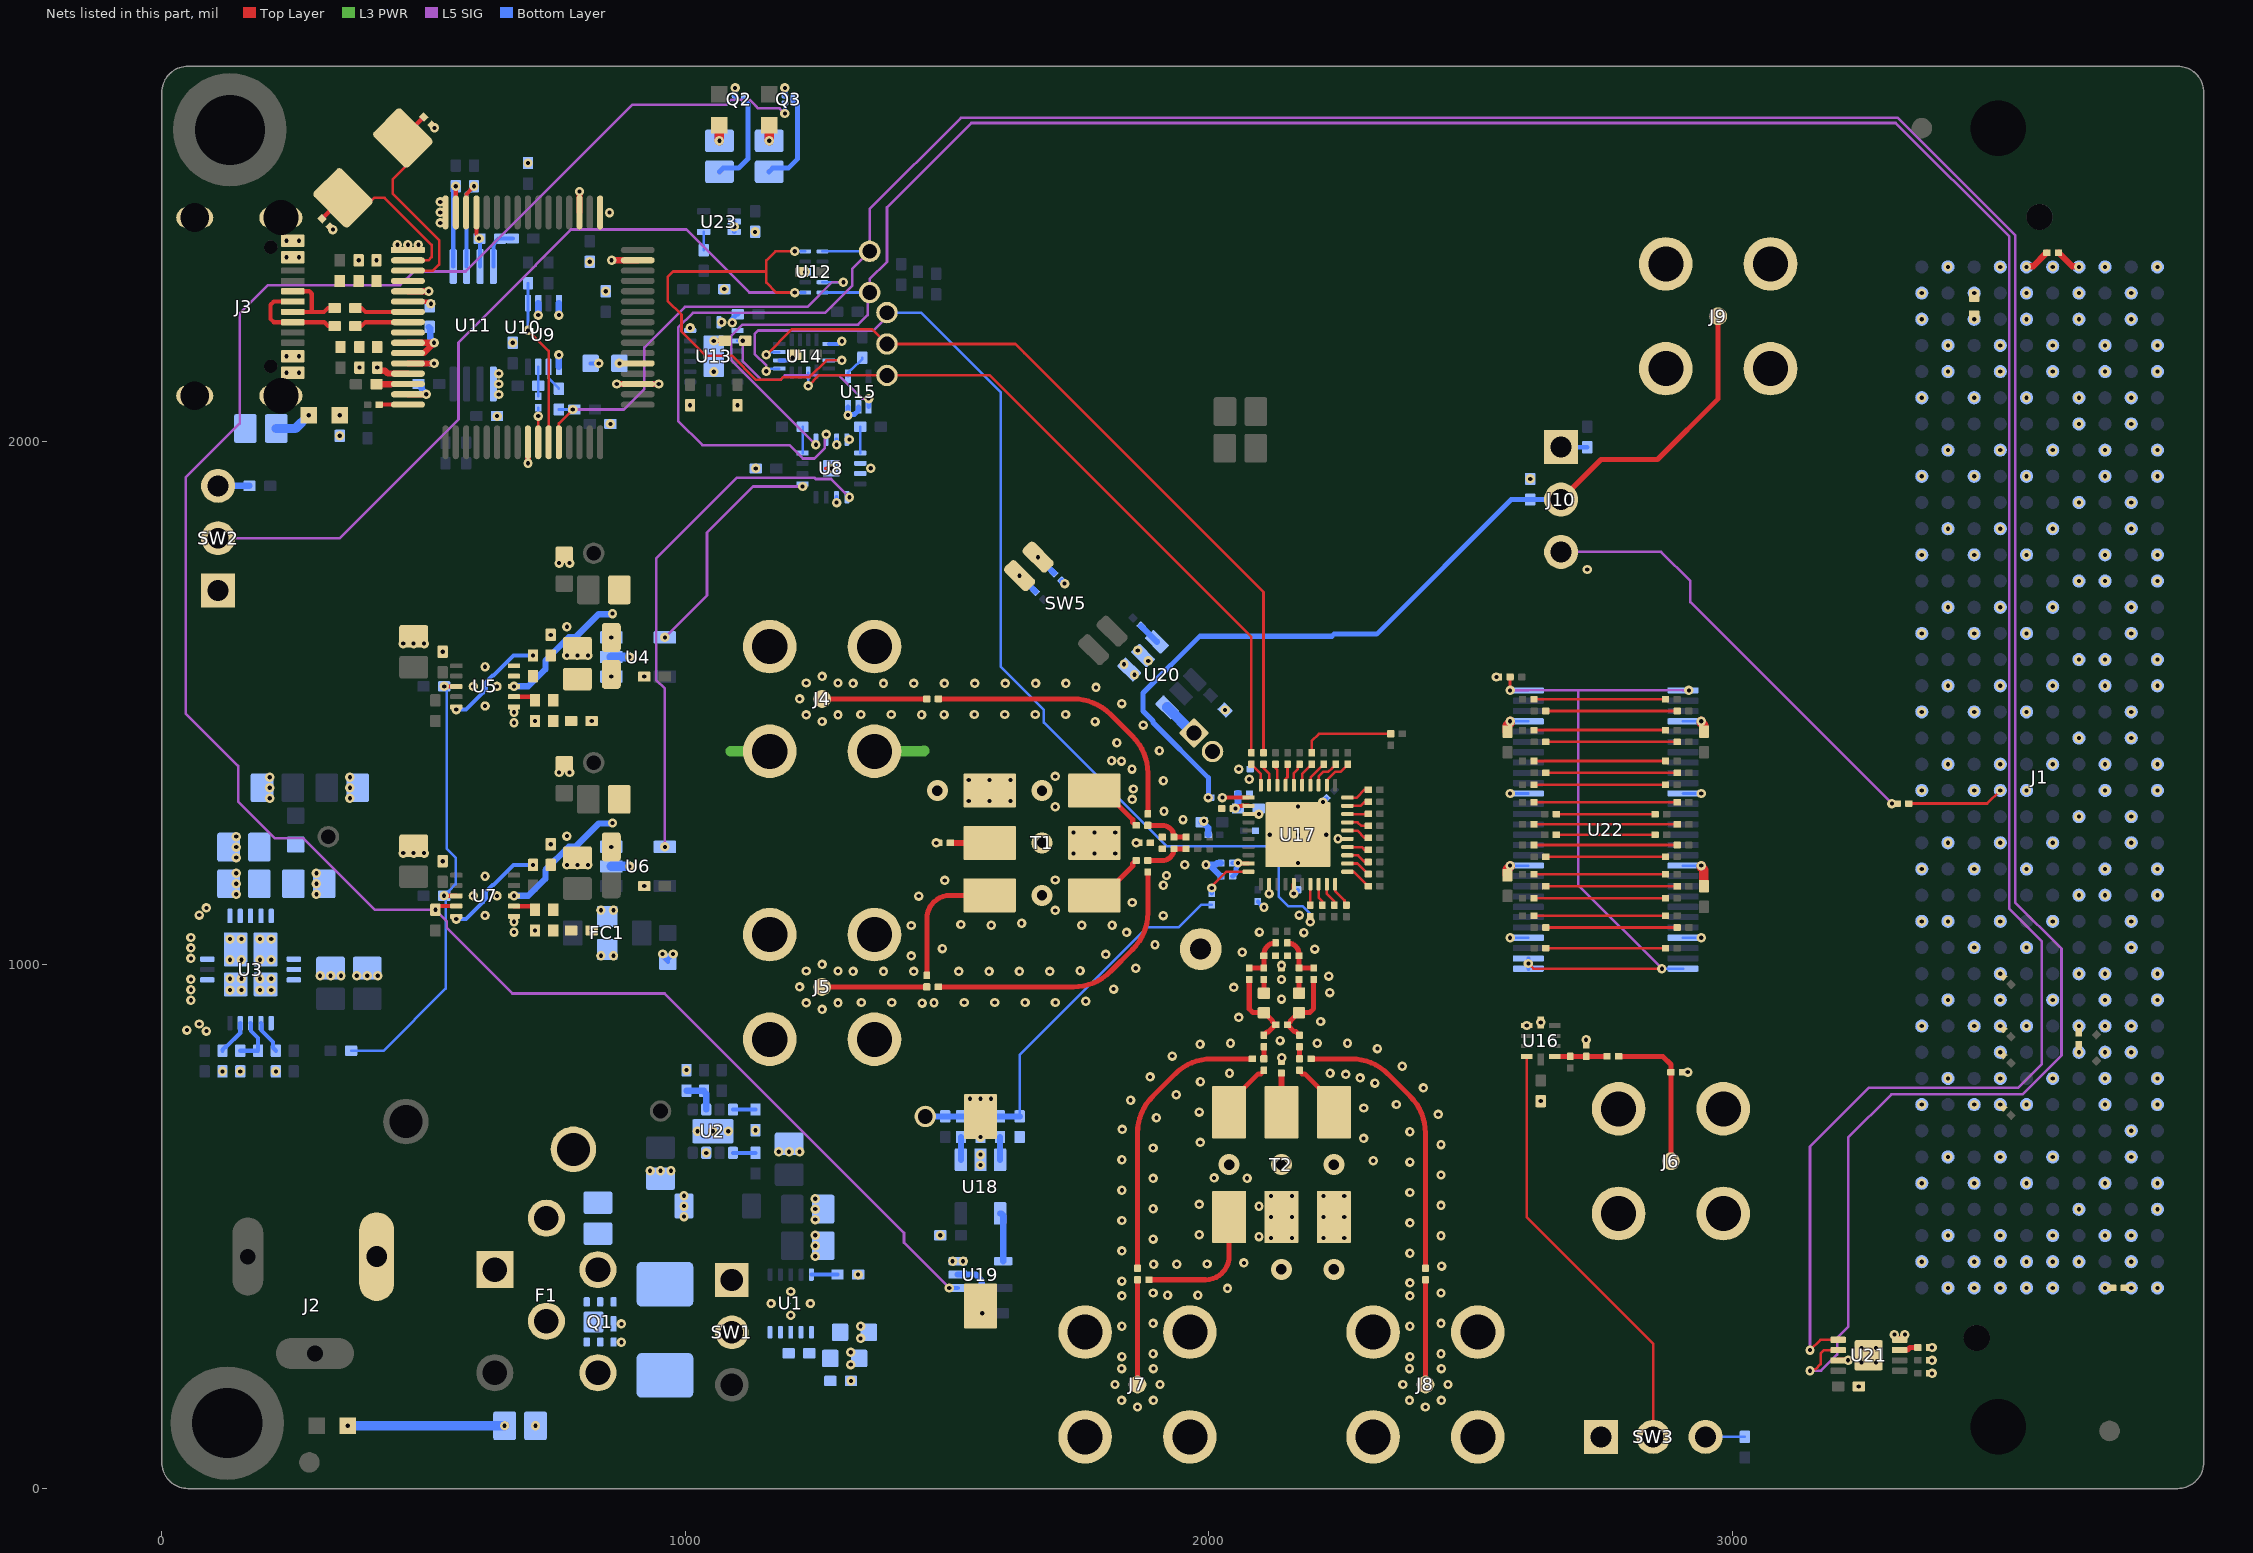
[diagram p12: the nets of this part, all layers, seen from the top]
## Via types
v1: diameter 18, hole 8, Top Layer to Bottom Layer, tented both sides, 891 vias
v2: diameter 40, hole 20, Top Layer to Bottom Layer, tented both sides, 9 vias
v3: diameter 18, hole 8, Top Layer to Bottom Layer, tented bottom, 4 vias

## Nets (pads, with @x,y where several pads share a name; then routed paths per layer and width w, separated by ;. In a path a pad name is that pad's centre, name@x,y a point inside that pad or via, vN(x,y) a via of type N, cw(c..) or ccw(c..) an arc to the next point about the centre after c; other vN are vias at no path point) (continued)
GND: C2.1 C3.1 C4.1 C5.1 C6.1 C7.1 C8.1 C9.1 C10.1 C11.1 C12.1 C13.1 C14.1 C15.1 C16.2 C17.1 C18.1 C19.1 C20.1 C21.1 C22.1 C23.1 C24.1 C25.1 C26.1 C27.1 C28.1 C29.1 C30.1 C31.1 C32.1 C33.1 C34.1 C35.1 C36.1 C37.1 C38.1 C39.1 C40.1 C41.1 C42.1 C43.1 C44.1 C45.1 C46.1 C47.1 C48.1 C51.2 C52.1 C56.1 C61.1 C62.2 C66.1 C67.1 C68.1 C69.1 C70.1 C71.1 C72.1 C73.1 C74.1 C75.1 C76.1 C77.1 C78.1 C79.1 C80.1 C81.1 C82.1 C83.1 C84.1 D3.2 FC1.2 J1.A1 J1.A4 J1.A5 J1.A8 J1.A9 J1.A12 J1.A13 J1.A16 J1.A17 J1.A20 J1.A21 J1.A24 J1.A25 J1.A28 J1.A29 J1.A32 J1.A33 J1.A36 J1.A37 J1.A40 J1.B2 J1.B3 J1.B6 J1.B7 J1.B10 J1.B11 J1.B14 J1.B15 J1.B18 J1.B19 J1.B22 J1.B23 J1.B26 J1.B27 J1.B30 J1.B31 J1.B34 J1.B35 J1.B38 J1.B39 J1.C1 J1.C4 J1.C5 J1.C8 J1.C9 J1.C12 J1.C13 J1.C16 J1.C17 J1.C20 J1.C21 J1.C24 J1.C25 J1.C28 J1.C29 J1.C32 J1.C33 J1.C36 J1.C38 J1.C40 J1.D2 J1.D3 J1.D6 J1.D7 J1.D10 J1.D13 J1.D16 J1.D19 J1.D22 J1.D25 J1.D28 J1.D37 J1.D39 J1.E1 J1.E4 J1.E5 J1.E8 J1.E11 J1.E14 J1.E17 J1.E20 J1.E23 J1.E26 J1.E29 J1.E32 J1.E35 J1.E38 J1.E40 J1.F2 J1.F3 J1.F6 J1.F9 J1.F12 J1.F15 J1.F18 J1.F21 J1.F24 J1.F27 J1.F30 J1.F33 J1.F36 J1.F39 J1.G1 J1.G4 J1.G5 J1.G8 J1.G11 J1.G14 J1.G17 J1.G20 J1.G23 J1.G26 J1.G29 J1.G32 J1.G35 J1.G38 J1.G40 J1.H3 J1.H6 J1.H9 J1.H12 J1.H15 J1.H18 J1.H21 J1.H24 J1.H27 J1.H30 J1.H33 J1.H36 J1.H39 J1.J1 J1.J4 J1.J5 J1.J8 J1.J11 J1.J14 J1.J17 J1.J20 J1.J23 J1.J26 J1.J29 J1.J32 J1.J35 J1.J38 J1.J40 J1.K2 J1.K3 J1.K6 J1.K9 J1.K12 J1.K15 J1.K18 J1.K21 J1.K24 J1.K26 J1.K30 J1.K33 J1.K36 J1.K39 J3.1 J3.2 J3.3 J3.4 J3.A1 J3.B1 J4.2 J4.3 J4.4 J4.5 J5.2 J5.3 J5.4 J5.5 J6.2 J6.3 J6.4 J6.5 J7.2 J7.3 J7.4 J7.5 J8.2 J8.3 J8.4 J8.5 J9.2 J9.3 J9.4 J9.5 Q1.4 Q1.7 Q2.2@1095,2660 Q3.2@1190,2660 R2.1 R3.1 R4.1 R8.1 R12.1 R13.1 R19.1 R21.1 R28.1 R30.1 R44.1 R45.1 R54.1 R57.2 R61.2 R70.1 R71.1 R89.1 R114.1 R122.1 R123.1 R124.1 R125.1 R126.1 R127.1 R137.1 R147.1 R180.1 SW2.3 SW3.3 SW4.2 T1.1 T1.5 T2.2 T2.3 U1.11 U2.3 U2.9 U3.1 U3.2 U3.3 U3.5 U3.6 U3.7 U3.8 U3.9 U3.16 U3.17 U3.20 U3.25 U3.26 U3.28 U4.2 U5.6 U5.11 U6.2 U7.6 U7.11 U8.2 U8.3 U8.6 U8.15 U8.16 U8.17 U9.2 U9.4 U9.5 U10.1 U10.5 U10.10 U10.11 U10.13 U10.15 U10.25 U10.35 U10.47 U10.51 U11.5 U12.3@1228.98,2323.6 U13.7 U13.9 U13.10 U13.17 U14.6 U14.13 U15.2 U15.3 U16.5 U16.6 U17.3 U17.12 U17.15 U17.25 U17.41 U18.2 U19.3 U20.1 U20.2 U21.4 U21.7 U21.9 U22.4 U22.11 U22.18 U22.25 U22.32 U22.39 U22.46 U22.53 U23.2 U23.3 | length 2249.5
  Top Layer w5: v1(2246.43,1240.92) U17.25@2264.43,1240.92 ; R71.1@2720.22,847.32 v1(2720.22,857.32) ; R70.1@2904.31,795.27 v1(2914.31,795.27)
  Top Layer w8: v1(460.98,1213.72) 474.98,1227.72 C24.1@480.98,1227.72 ; v1(460.98,1613.72) 474.98,1627.72 C18.1@480.98,1627.72 ; v1(480.98,1213.72) C24.1@480.98,1227.72 ; v1(480.98,1613.72) C18.1@480.98,1627.72 ; v1(500.98,1213.72) 486.98,1227.72 C24.1@480.98,1227.72 ; v1(500.98,1613.72) 486.98,1627.72 C18.1@480.98,1627.72 ; v1(758.74,1367.62) 758.74,1373.36 C27.1@768.74,1383.36 778.74,1373.36 v1(778.74,1367.62) ; v1(773.72,1191.03) 787.72,1205.03 C26.1@793.72,1205.03 ; v1(773.72,1591.03) 787.72,1605.03 C20.1@793.72,1605.03 ; v1(793.72,1191.03) C26.1@793.72,1205.03 ; v1(793.72,1591.03) C20.1@793.72,1605.03 ; v1(813.72,1191.03) 799.72,1205.03 C26.1@793.72,1205.03 ; v1(813.72,1591.03) 799.72,1605.03 C20.1@793.72,1605.03 ; v1(1479.06,1233.05) C51.2@1484.06,1233.05 ; v1(1861.06,1233.05) C52.1@1866.06,1233.05 ; U17.3@2075.45,1288.17 v1(2095.45,1288.17) ; v1(2114.82,1136.31) U17.12@2114.82,1154.31 ; v1(2162.07,1136.31) U17.15@2162.07,1154.31 ; v1(2548.95,1550) R180.1@2552.95,1550 ; C21.1@758.74,1773.36 C21.1@768.74,1783.36 ; C21.1@758.74,1773.36 v1(758.74,1767.62) C21.1@758.74,1773.36 ; C21.1@758.74,1773.36 C21.1@768.74,1783.36 ; C21.1@768.74,1783.36 C21.1@778.74,1773.36 ; C21.1@768.74,1783.36 C21.1@778.74,1773.36 ; C21.1@778.74,1773.36 v1(778.74,1767.62) C21.1@778.74,1773.36 ; 1269.05,1948.3 U8.17@1278.9,1948.29 1269.05,1948.29
  Top Layer w9: U13.17@1054.25,2192.04 R54.1@1075.16,2192.04
  Top Layer w10: U21.7@3201.8,244.68 3202.01,244.88 3220.36,244.88 v1(3220.57,245.09) ; v1(3309.06,294.05) U21.4@3319.06,284.05 v1(3329.06,294.05) ; R124.1@3376.1,219.99 v1(3381.1,219.99) ; R125.1@3376.1,244.68 v1(3381.1,244.68) ; R126.1@3376.1,269.36 v1(3381.1,269.36) ; v1(3461.42,2233.27) R137.1@3461.42,2238.58 ; v1(3711.42,383.27) R127.1@3726.08,383.27
  Top Layer w12: C43.1@321.7,2409.56 v1(326.7,2404.56) ; v1(411.37,2140.87) 411.37,2138.91 415.21,2135.06 426.33,2135.06 431.82,2129.57 469.65,2129.57 U10.13@470,2129.23 ; U10.15@470,2089.86 v1(505,2089.86) ; U10.11@470,2168.6 500.32,2168.6 v1(520,2188.28) U10.10@470,2188.28 ; U10.5@470,2286.71 v1(510,2286.71) ; C44.1@515.84,2603.7 v1(520.84,2598.7) ; v1(699.33,1958.32) U10.25@699.33,1998.32 ; U10.51@797.76,2437.3 v1(797.76,2477.3) ; v1(858.98,2345.76) U10.47@908.98,2345.76 ; v1(868.98,2109.54) U10.35@908.98,2109.54 v1(948.98,2109.54)
  Top Layer w18: C84.1@2570,1171.22 2570,1183.03 2575,1188.03 v1(2575,1189.74) ; C81.1@2570,1445.65 2570,1457.46 2575,1462.46 v1(2575,1465.33) ; v1(2940.28,1189.74) 2940.28,1186.87 2945.28,1181.87 C83.1@2945.28,1150.37 ; v1(2940.28,1465.33) 2940.28,1462.46 2945.28,1457.46 C82.1@2945.28,1445.65
  L3 PWR w20: 1086.21,1408.05 J4.4@1161.11,1408.05 ; J4.5@1361.11,1408.05 1454.85,1408.05 1455.97,1409.17
  Bottom Layer w5: U13.7@1008.98,2211.73 v1(1008.98,2216.73) ; U13.9@1064.09,2227.47 v1(1069.09,2227.47) ; v1(2575,1051.95) U22.32@2610,1051.95 ; v1(2575,1189.74) U22.39@2610,1189.74 ; v1(2575,1327.54) U22.46@2610,1327.54 ; v1(2575,1465.33) U22.53@2610,1465.33 ; U22.25@2905.28,1051.95 v1(2940.28,1051.95) ; U22.18@2905.28,1189.74 v1(2940.28,1189.74) ; U22.11@2905.28,1327.54 v1(2940.28,1327.54) ; U22.4@2905.28,1465.33 v1(2940.28,1465.33)
  Bottom Layer w8: C36.1@818.86,2148.91 v1(834.61,2148.91) ; v1(956.48,1020.93) 956.48,1015.93 C29.1@966.48,1005.93 966.48,1010.93 v1(976.48,1020.93) ; U23.3@1093.18,2400.11 v1(1093.18,2409.96) U23.2@1093.18,2419.8 ; U14.6@1179.53,2154.64 1196.82,2154.64 1201.82,2159.64 v1(1204.53,2159.64) ; U14.13@1274.02,2186.14 1291.31,2186.14 1296.31,2191.14 v1(1299.02,2191.14) ; v1(1288.74,1883.18) U8.6@1288.74,1893.18 ; v1(1288.74,1993.41) U8.15@1288.74,2003.41 ; C68.1@2093.37,1121.24 2093.37,1120.45 2103.66,1110.16 v1(2105.13,1110.16) ; v1(2162.07,1136.31) 2163.75,1136.31 2169.94,1142.5 C66.1@2169.94,1143.29 ; v1(2217.54,1311.29) 2217.54,1311.85 C69.1@2223.88,1318.19
  Bottom Layer w9: v1(1089.53,2226.73) 1089.05,2227.2 1089.05,2233.76 1098.32,2243.02 R57.2@1100.29,2243.02 ; v1(1310.63,2050.22) U15.3@1310.63,2065.97
  Bottom Layer w9.7: Q2.2@1095,2660 v1(1095,2675) ; Q3.2@1190,2660 v1(1190,2675) ; v1(1310.63,2050.22) 1311.97,2051.56 1323.19,2051.56 1330.32,2058.68 U15.2@1330.32,2065.97
  Bottom Layer w12: C38.1@490.24,2109.54 492.21,2109.54 496.06,2105.7 496.06,2099.89 505,2090.94 v1(505,2089.86) ; R45.1@510,2218.61 512.81,2215.81 512.81,2197.1 520,2189.9 v1(520,2188.28) v1@512,2188.28 ; v1(719.02,2241.27) U9.2@719.02,2264.27 ; U9.5@758.39,2142.22 v1(758.39,2165.22) ; v1(758.39,2241.27) U9.4@758.39,2264.27 ; v1@1313.15,2002.7 v1(1313.15,2003.55) ; R123.1@1719.15,1733.26 1723.54,1728.88 1724.77,1728.88 v1(1724.15,1728.26) ; C78.1@1986.08,1272.42 1988.05,1272.42 1998.41,1262.07 C79.1@1998.41,1248.42 ; C71.1@2022.97,1169.68 2022.19,1169.68 2001.77,1190.1 1995.53,1190.1 v1(1994.38,1191.25) 2012.46,1191.25 2015.89,1194.68 C70.1@2022.97,1194.68
  Bottom Layer w18: U6.2@858.46,1188.15 v1(893.46,1188.15) ; U4.2@858.46,1588.15 v1(893.46,1588.15)
  other v1: 713.73,119.85 1863.45,155.72 2413.45,155.72 1833.04,168.31 1893.85,168.31 2383.04,168.31 2443.85,168.31 3241.17,194.99 1820.45,198.72 1906.45,198.72 2370.45,198.72 2456.45,198.72 1316.31,205.62 1833.04,229.13 1893.85,229.13 2383.04,229.13 2443.85,229.13 1315.9,236.67 1833.73,251.91 2383.73,251.91 1893.17,257.52 2443.17,257.52 1315.9,260.14 877.82,279.42 1334.68,286.67 1334.68,310.14 1833.73,309.91 2383.73,309.91 877.82,314.42 1893.17,315.52 2443.17,315.52 1833.73,367.91 2383.73,367.91 1920.88,369 1978.88,369 1893.17,373.52 2443.17,373.52 2035.36,382.2 3411.42,383.27 3511.42,383.27 3611.42,383.27 3811.42,383.27 2383.73,392.76 1833.72,396.3 1329.96,408.64 2444.32,424.84 1894.32,428.42 1938.51,428.44 1996.5,428.81 2066.73,430.98 3361.42,433.27 3461.42,433.27 3561.42,433.27 3661.42,433.27 3761.42,433.27 1510.3,434.23 1530.3,434.23 1248.09,443.64 2383.73,449.44 1833.73,453.87 1248.09,463.64 1893.17,476.41 2118.45,478.72 2158.45,478.72 2218.45,478.72 2258.45,478.72 2095.58,481.3 2443.17,482.83 1248.09,483.64 1486.89,483.65 3411.42,483.27 3511.42,483.27 3611.42,483.27 3711.42,483.27 3761.42,483.27 1981.32,484.79 2383.73,507.44 1833.73,511.87 1248.09,513.64 2118.45,518.72 2158.45,518.72 2218.45,518.72 2258.45,518.72 997.3,519.36 1248.09,533.64 3661.42,533.27 3811.42,533.27 1893.17,534.41 997.3,539.36 2095.58,539.3 2443.17,540.83 1981.32,542.79 1248.09,553.64 2118.45,558.72 2158.45,558.72 2218.45,558.72 2258.45,558.72 997.3,559.36 2383.73,565.44 1833.73,569.87 3361.42,583.27 3461.42,583.27 3561.42,583.27 3711.42,583.27 3811.42,583.27 1893.17,592.41 2072.72,592.61 2009.73,593.35 2443.17,598.83 932.5,606.94 952.5,606.94 972.5,606.94 1563.61,617.87 2383.73,623.44 2313.86,626.23 1833.73,627.87 3411.42,633.27 3511.42,633.27 3611.42,633.27 3761.42,633.27 1563.61,637.87 1039.7,641.15 1178.13,643.42 1198.13,643.42 1218.13,643.42 1893.17,650.41 2443.17,656.83 1983.29,661.04 2295.21,668.82 1563.61,671.34 2383.69,681.44 3761.42,683.27 1133.88,684.46 1834.29,685.87 1899.57,708.05 2437.83,714.58 1981.32,719.01 2295.58,726.82 2358.06,733.47 3361.42,733.27 3461.42,733.27 3561.42,733.27 3711.42,733.27 3811.42,733.27 2633.64,739.99 1850.33,741.61 1543.61,744.61 1563.61,744.61 1583.61,744.61 1937.39,752.02 2409.59,765.24 2316.86,774.3 1983.52,776.97 3411.42,783.27 3511.42,783.27 3611.42,783.27 3711.42,783.27 3811.42,783.27 2288.58,784.39 1887.47,786.16 2261.33,791.05 2039.16,793.35 2231.27,793.35 115.89,796.75 149.89,796.75 217.89,796.75 1002.1,799.2 2368.96,806.63 2138.87,822.85 1929.7,825.92 3761.42,833.27 2321.72,840.29 1983.09,848.57 2041.06,850.49 2206.62,850.49 2264.62,850.49 2135.87,855.52 85.27,873.58 47.89,875.49 3361.42,883.27 3461.42,883.27 3561.42,883.27 3761.42,883.27 2607.07,884.32 71.55,887.3 2633.64,890.23 2213.26,892 2056.72,899.9 1261.11,915.05 1230.7,927.64 1291.51,927.64 1452.07,927.18 1474.77,927.69 1336.09,928.33 1394.09,928.33 1532.76,928.33 1590.76,928.33 1648.76,928.33 1706.76,928.33 1764.71,930.73 55.51,932.48 3411.42,933.27 3511.42,933.27 3611.42,933.27 3711.42,933.27 3811.42,933.27 2138.45,934.79 2230.67,947.33 55.51,952.48 1817.9,953.86 2047.21,957.11 1218.11,958.05 55.51,972.48 2138.45,972.22 2228.88,978.84 302.26,979.25 322.26,979.25 342.26,979.25 372.26,979.25 392.26,979.25 412.26,979.25 3661.42,983.27 3711.42,983.27 3811.42,983.27 1320.3,987.77 1378.3,987.77 1436.3,987.77 1521.96,987.77 1579.96,987.77 1637.96,987.77 1695.96,987.77 1230.7,988.46 1291.51,988.46 1753.95,988.8 1860.11,993.63 1261.11,1001.05 55.51,1012.48 1431.39,1017.35 1802.68,1020.26 2063.68,1024.29 2202.05,1030.26 1490.83,1031.32 55.51,1032.48 3461.42,1033.27 3561.42,1033.27 3761.42,1033.27 1896.97,1038.42 55.51,1052.48 2181.3,1061.83 672.72,1062.68 1842.66,1062.28 2096.27,1062.84 712.72,1065.91 821.09,1065.91 1431.39,1075.35 1584.19,1075.92 1757.05,1075.92 1815.05,1075.92 1526.21,1077.28 1642.06,1079.77 672.72,1082.68 3361.42,1083.27 3411.42,1083.27 3511.42,1083.27 3611.42,1083.27 3761.42,1083.27 1912.59,1094.28 71.55,1095.3 2172.52,1095.34 1706.48,1104.31 85.27,1109.02 1853.44,1119.27 1445.8,1131.53 3661.42,1133.27 3711.42,1133.27 3811.42,1133.27 142.26,1135 295.33,1135 921.46,1150.75 1912.87,1152.28 142.26,1155 295.33,1155 1495.39,1161.6 1706.48,1162.31 1918.93,1170.82 142.26,1175 295.33,1175 3361.42,1183.27 3461.42,1183.27 3561.42,1183.27 3711.42,1183.27 3811.42,1183.27 1953.79,1191.31 536.41,1198.19 142.26,1205.06 1741.11,1213.05 1781.11,1213.05 1821.11,1213.05 142.26,1225.06 742.72,1230.47 3411.42,1233.27 3511.42,1233.27 3611.42,1233.27 3761.42,1233.27 142.26,1245.06 773.72,1246.01 1741.11,1253.05 1781.11,1253.05 1821.11,1253.05 1990.19,1274.7 1950.39,1277.59 3661.42,1283.27 3761.42,1283.27 1914.03,1293.68 1706.56,1302.08 1541.11,1313.05 1581.11,1313.05 1621.11,1313.05 1853.44,1316.16 206.27,1318.49 359.34,1318.49 3361.42,1333.27 3461.42,1333.27 3561.42,1333.27 3711.42,1333.27 3811.42,1333.27 1855.74,1336.13 206.27,1338.49 359.34,1338.49 1912.87,1351.66 1541.11,1353.05 1581.11,1353.05 1621.11,1353.05 2077.05,1354.73 206.27,1358.49 359.34,1358.49 1706.48,1360.08 1852.93,1374.15 3411.42,1383.27 3511.42,1383.27 3611.42,1383.27 3711.42,1383.27 3811.42,1383.27 1832.88,1389.44 1814.05,1390.18 1905.33,1409.17 1824.06,1424.46 3661.42,1433.27 3761.42,1433.27 1874.37,1458.21 672.72,1462.68 1782.46,1464.87 1261.11,1465.05 712.72,1465.91 821.09,1465.91 1230.7,1477.64 1291.51,1477.64 1335.23,1478.33 1393.23,1478.33 1451.23,1477.98 1494.04,1478.18 1552.04,1478.33 1610.04,1478.33 1668.04,1478.33 1726.04,1478.33 672.72,1482.68 3361.42,1483.27 3461.42,1483.27 3561.42,1483.27 3761.42,1483.27 2030.8,1486.91 1833.35,1499.23 1218.11,1508.05 1784.28,1530.13 3411.42,1533.27 3511.42,1533.27 3611.42,1533.27 3711.42,1533.27 3811.42,1533.27 1320.3,1537.77 1378.3,1537.77 1436.3,1537.77 1494.78,1537.77 1552.78,1537.77 1610.78,1537.77 1668.78,1537.77 1726.78,1537.77 1230.7,1538.46 1291.51,1538.46 921.46,1550.75 1261.11,1551.05 1857.68,1554.24 1837.68,1574.24 1884.13,1580.68 3661.42,1583.27 3711.42,1583.27 3811.42,1583.27 536.41,1598.19 1864.13,1600.68 742.72,1630.47 3361.42,1633.27 3461.42,1633.27 3561.42,1633.27 3761.42,1633.27 773.72,1646.01 3411.42,1683.27 3511.42,1683.27 3611.42,1683.27 3761.42,1683.27 3661.42,1733.27 3711.42,1733.27 3811.42,1733.27 2722.46,1755.24 3361.42,1783.27 3461.42,1783.27 3561.42,1783.27 3711.42,1783.27 3811.42,1783.27 3411.42,1833.27 3511.42,1833.27 3611.42,1833.27 3761.42,1833.27 3661.42,1883.27 3761.42,1883.27 2613.43,1928.25 3361.42,1933.27 3461.42,1933.27 3561.42,1933.27 3711.42,1933.27 3811.42,1933.27 1134.41,1948.29 1354.11,1948.52 3411.42,1983.27 3511.42,1983.27 3611.42,1983.27 3711.42,1983.27 3811.42,1983.27 340,2010.63 856.81,2033.32 3661.42,2033.27 3761.42,2033.27 640.28,2048.32 1008.98,2068.93 1099.53,2068.93 3361.42,2083.27 3461.42,2083.27 3561.42,2083.27 3661.42,2083.27 3761.42,2083.27 643.39,2089.54 643.39,2109.54 643.39,2129.54 238.16,2131.19 262.16,2131.19 3411.42,2133.27 3511.42,2133.27 3611.42,2133.27 3711.42,2133.27 3811.42,2133.27 377.37,2140.87 3411.42,2183.27 3511.42,2183.27 3611.42,2183.27 3711.42,2183.27 3811.42,2183.27 670.29,2188.28 3361.42,2233.27 3561.42,2233.27 3661.42,2233.27 3761.42,2233.27 3361.42,2283.27 3561.42,2283.27 3661.42,2283.27 3761.42,2283.27 847.98,2286.71 1074.29,2290.74 1228.98,2323.6 3411.42,2333.27 3511.42,2333.27 3611.42,2333.27 3711.42,2333.27 3811.42,2333.27 817.44,2342.93 376,2345.76 410,2345.76 450,2375.45 470,2375.45 490,2375.45 238.16,2383.16 262.16,2383.16 1133.18,2400.11 699.33,2531.67
  other v2: 2138.45,418.72 2238.45,418.72 2038.45,618.72 2138.45,618.72 2238.45,618.72 1681.11,1133.05 1681.11,1233.05 1481.11,1333.05 1681.11,1333.05
IOVDD_PG: Q3.1@1190,2646.22 R23.1 U7.4 U19.1 | length 4078.8
  Top Layer w8: v1(522.48,1105.28) 522.48,1106.52 528.32,1112.36 U7.4@562.48,1112.36
  L5 SIG w5: 898.37,2642.72 580.14,2324.49 481.52,2324.49 455.32,2298.29 202.71,2298.29 148.81,2244.39 148.81,2034.01 45.51,1930.7 45.51,1480.61 145.67,1380.45 145.67,1312.5 216.33,1241.84 270.16,1241.84 406.73,1105.28 v1(522.48,1105.28) 544.38,1083.37 544.38,1070.5 669.37,945.51 960.37,945.51 1417.41,488.48 1417.41,469.72 v1(1504.08,383.05) ; 898.7,2643.05 1078.5,2643.05 1088.17,2652.72 1122.01,2652.72 1134.61,2640.12 1138.51,2636.22 1180,2636.22 v1(1190,2626.22)
  Bottom Layer w8: v1(1190,2626.22) Q3.1@1190,2646.22 ; v1(1504.08,383.05) U19.1@1520.3,383.05
ISENSE_AVDD: U4.4 U8.9 | length 457.3
  L5 SIG w5: v1(960.83,1625.55) 1041.3,1706.03 1041.3,1825.49 1129.58,1913.77 v1(1223.78,1913.77)
  Bottom Layer w5: v1(1223.78,1913.77) U8.9@1223.78,1918.77
ISENSE_IOVDD: U6.4 U8.5 | length 1011
  L5 SIG w5: v1(960.83,1225.55) 960.83,1527.72 944.33,1544.22 944.33,1776.67 1097.92,1930.27 1246.64,1930.27 1248.83,1928.07 1278.53,1928.07 v1(1313.42,1893.18)
  Bottom Layer w5: U8.5@1308.42,1893.18 v1(1313.42,1893.18)
NetC1_1: C1.1 D2.2 F1.2 Q1.3 SW1.1
NetC1_2: C1.2 D2.1 F1.4 Q1.1 Q1.2 Q1.5 Q1.6 Q1.8
NetC4_2: C4.2 R1.1 R4.2 U1.2
NetC5_2: C5.2 U1.1
NetC8_2: C8.2 U2.8 | length 43
  Bottom Layer w8: U2.8@1090.88,723.83 C8.2@1133.88,723.83
NetC11_2: C11.2 C12.2 C13.2 FB1.1 U3.10 U3.11 U3.12 U3.13 U3.14 U3.15 U3.27
NetC16_1: C16.1 U3.21 | length 64.7
  Bottom Layer w8: U3.21@189.27,888.94 190.19,888.02 190.19,874.88 212.1,852.96 212.1,841.91 C16.1@217.89,836.12
NetC20_2: C20.2 R16.1 R18.2 U4.1 U5.9 U5.10
  other v1: 858.46,1550.75
NetC22_2: C22.2 R20.2 U5.7 | length 44
  Top Layer w9: U5.7@672.72,1512.36 707.37,1512.36 712.72,1507.02 C22.2@712.72,1505.28
NetC28_2: C28.2 R29.2 U7.7 | length 44
  Top Layer w9: U7.7@672.72,1112.36 707.37,1112.36 712.72,1107.02 C28.2@712.72,1105.28
NetC32_2: C32.2 C33.2 FB4.2 U10.9
NetC34_2: C34.2 C35.2 FB5.2 U10.4
NetC43_2: C43.2 U10.2 Y1.1 | length 338.6
  Top Layer w5: Y1.1@346.11,2465.15 351.11,2460.15 400.47,2460.15 405.47,2465.15 425.62,2465.15 515.29,2375.49 515.29,2351.67 509.38,2345.76 U10.2@470,2345.76
  Top Layer w8: C43.2@306.11,2425.15 Y1.1@346.11,2465.15
NetC44_2: C44.2 U10.3 Y1.2 | length 411.4
  Top Layer w5: Y1.2@460.25,2579.29 465.25,2574.29 465.25,2524.93 440.9,2500.58 440.9,2472.95 529.61,2384.23 529.61,2337.89 517.8,2326.08 U10.3@470,2326.08
  Top Layer w8: Y1.2@460.25,2579.29 C44.2@500.25,2619.29
NetC49_1: C49.1 C50.2 R62.2 R64.2 | length 85.7
  Top Layer w9.7: C50.2@1883.16,1266.57 1910.93,1266.57 cw(c1910.93,1244.35) R64.2@1933.16,1244.35 C49.1@1956.16,1244.35
NetC50_1: C50.1 T1.6 | length 110.3
  Top Layer w9.7: T1.6@1781.11,1333.05 1798.61,1333.05 1854.39,1277.27 1854.39,1272.5 1860.32,1266.57 C50.1@1861.11,1266.57
NetC51_1: C51.1 T1.2 | length 75
  Top Layer w12: C51.1@1506.11,1233.05 T1.2@1581.11,1233.05
NetC52_2: C52.2 R64.1 R66.2
NetC53_1: C53.1 T1.3 | length 253.6
  Top Layer w9.7: C53.1@1461.11,980.1 1461.11,1088.05 cw(c1506.11,1088.05) 1506.11,1133.05 T1.3@1581.11,1133.05
NetC54_1: C54.1 C55.1 R66.1 R68.2 | length 85.7
  Top Layer w9.7: C54.1@1883.16,1199.53 1910.93,1199.53 ccw(c1910.93,1221.75) R66.1@1933.16,1221.75 C55.1@1956.16,1221.75
NetC54_2: C54.2 T1.4 | length 110.3
  Top Layer w9.7: T1.4@1781.11,1133.05 1798.61,1133.05 1854.39,1188.83 1854.39,1193.6 1860.32,1199.53 C54.2@1861.11,1199.53
NetC57_1: C57.1 R69.1 R71.2 U16.1 | length 100
  Top Layer w9.7: U16.1@2660.22,825.27 R69.1@2690.22,825.27 R71.2@2720.22,825.27 C57.1@2760.22,825.27
NetC57_2: C57.2 J6.1 R70.2 | length 290.9
  Top Layer w9.7: C57.2@2782.27,825.27 2866.74,825.27 2882.27,809.74 R70.2@2882.27,795.27 J6.1@2882.27,625.27
NetC58_1: C58.1 C59.1 J7.1 | length 200
  Top Layer w9.7: J7.1@1863.45,198.72 C58.1@1863.45,398.72
NetC58_2: C58.2 R73.1 | length 551.9
  Top Layer w9.7: C58.2@1863.45,420.77 1863.45,678.69 cw(c1963.45,678.69) 1892.74,749.4 1935.34,792 cw(c2004.78,722.56) 2004.78,820.77 R73.1@2082.88,820.77
NetC59_2: C59.2 T2.1 | length 253.6
  Top Layer w9.7: C59.2@1885.49,398.72 1993.45,398.72 ccw(c1993.45,443.72) 2038.45,443.72 T2.1@2038.45,518.72
NetC60_1: C60.1 T2.6 | length 110.3
  Top Layer w9.7: T2.6@2038.45,718.72 2038.45,736.22 2094.23,792 2098.99,792 2104.93,797.93 C60.1@2104.93,798.72
NetC60_2: C60.2 R73.2 R74.1 | length 23
  Top Layer w9.7: C60.2@2104.93,820.77 R74.1@2104.93,843.77
NetC62_1: C62.1 T2.5 | length 75
  Top Layer w12: T2.5@2138.45,718.72 C62.1@2138.45,793.72
NetC63_1: C63.1 L2.1 R82.2 R83.1 | length 150.7
  Top Layer w9.7: C63.1@2148.97,885.81 C63.1@2149.76,885.81 ; R82.2@2171.97,865.81 2171.97,866.6 2166.04,872.53 2163.04,872.53 C63.1@2149.76,885.81 ; R83.1@2199.97,971.43 2199.97,916.45 2192.65,909.13 2172.29,909.13 L2.1@2171.97,908.81 2170.98,908.81 2155.69,893.52 2155.69,891.74 C63.1@2149.76,885.81
NetC63_2: C63.2 L1.1 R74.2 R75.1 | length 150.7
  Top Layer w9.7: R75.1@2076.93,971.2 2076.93,916.22 2084.25,908.9 2104.61,908.9 2104.93,908.58 2105.91,908.58 2121.21,893.28 2121.21,891.51 C63.2@2127.14,885.58 ; R74.2@2104.93,865.58 2104.93,866.37 2110.86,872.3 2113.86,872.3 C63.2@2127.14,885.58 ; C63.2@2127.93,885.58 C63.2@2127.14,885.58
NetC64_1: C64.1 R81.2 R82.1 | length 23
  Top Layer w9.7: C64.1@2172.95,820.77 R82.1@2172.95,843.77
NetC64_2: C64.2 T2.4 | length 110.3
  Top Layer w9.7: C64.2@2171.97,798.72 2171.97,797.93 2177.9,792 2182.66,792 2238.45,736.22 T2.4@2238.45,718.72
NetC65_1: C65.1 J8.1 | length 200
  Top Layer w9.7: J8.1@2413.45,198.72 C65.1@2413.45,398.72
NetC65_2: C65.2 R81.1 | length 551.9
  Top Layer w9.7: R81.1@2194.02,820.77 2272.11,820.77 cw(c2272.11,722.56) 2341.56,792 2384.16,749.4 cw(c2313.45,678.69) 2413.45,678.69 C65.2@2413.45,420.77
NetD1_2: D1.2 R3.2 | length 300
  Bottom Layer w18: v1(355,120) R3.2@655,120
  other v1: 654.67,119.85
NetD4_2: D4.2 R17.2 | length 30
  Top Layer w18: v1(1065,2574.06) D4.2@1065,2604.06
NetD5_2: D5.2 R24.2 | length 30
  Top Layer w18: v1(1160,2574.06) D5.2@1160,2604.06
NetD6_2: D6.2 R44.2
  other v1: 340,2050
NetF1_1: F1.1 J2.1 TP1.1
NetFB2_1: FB2.1 R16.2 U4.3 U5.8 | length 255.5
  Bottom Layer w12: v1(672.65,1532.05) 700.02,1532.05 732.72,1564.76 732.72,1581.32 777.41,1626.01 790.09,1626.01 834.05,1669.98 859.68,1669.98 v1(860.83,1671.12)
  other v1: 858.46,1625.55
NetFB3_1: FB3.1 R26.2 U6.3 U7.8 | length 255.5
  Bottom Layer w12: v1(672.65,1132.05) 700.02,1132.05 732.72,1164.76 732.72,1181.32 777.41,1226.01 790.09,1226.01 834.05,1269.98 859.68,1269.98 v1(860.83,1271.12)
  other v1: 858.46,1225.55
NetJ1_B40: J1.B40 R127.2 | length 13.3
  Top Layer w10: R127.2@3748.13,383.27 v1(3761.42,383.27)
NetJ1_G21: J1.G21 R132.2 | length 185.4
  Top Layer w5: R132.2@3336.42,1308.27 3486.42,1308.27 v1(3511.42,1333.27)
NetJ1_G28: J1.G28 R133.2 | length 6.7
  Top Layer w5: v1(3511.42,983.27) R133.2@3516.12,978.56
NetJ1_G30: J1.G30 R134.2 | length 6.7
  Top Layer w5: v1(3511.42,883.27) R134.2@3516.12,878.56
NetJ1_G31: J1.G31 R135.2 | length 6.7
  Top Layer w5: v1(3511.42,833.27) R135.2@3516.12,828.56
NetJ1_G33: J1.G33 R136.2 | length 6.7
  Top Layer w5: v1(3511.42,733.27) R136.2@3516.12,728.56
NetJ3_A4,B4: J3.A4 J3.B4 R41.1
  other v1: 238.16,2162.69 262.16,2162.69 238.16,2351.67 262.16,2351.67
NetJ3_A6: J3.A6 J3.B6 R43.1 | length 200
  Top Layer w8: J3.B6@245.62,2227.65 213.91,2227.65 207.83,2233.72 207.83,2260.95 213.91,2267.02 J3.A6@250.16,2267.02 ; J3.B6@245.63,2227.65 J3.B6@250.16,2227.65 310.15,2227.65 317.56,2220.25 R43.1@330.16,2220.25
NetJ3_A7: J3.A7 J3.B7 R42.1 | length 155.9
  Top Layer w8: J3.A7@250.16,2247.34 286.41,2247.34 ; J3.B7@250.16,2286.71 281.72,2286.71 286.41,2282.02 286.41,2247.34 ; R42.1@330.16,2254.74 317.32,2254.74 309.91,2247.34 286.41,2247.34
NetJ9_1: J9.1 J10.2 R89.2 R108.1 | length 1745
  Top Layer w9.7: J10.2@2672.46,1888.88 2748.84,1965.25 2856.45,1965.25 2972.46,2081.26 J9.1@2972.46,2238.88
  Bottom Layer w9.7: R108.1@2003.85,1319.66 R108.1@2003.41,1319.66 1998.85,1319.66 1998.85,1357.61 1893.22,1463.24 1893.22,1466.02 1874.13,1485.11 1874.13,1519.36 1982.53,1627.76 2092.45,1627.76 2234.63,1627.76 2238.7,1631.83 2320.2,1631.83 2577.24,1888.88 R89.2@2613.43,1888.88 J10.2@2672.46,1888.88
  other v1: 1998.64,1319.66
NetJ10_1: J10.1 R96.1 | length 50
  Bottom Layer w8: J10.1@2672.46,1988.88 R96.1@2722.46,1988.88
NetJ11_1: J11.1 U20.6 | length 69.1
  Bottom Layer w20: U20.6@1920.06,1491.86 J11.1@1968.9,1443.02
NetL1_2: L1.2 R77.1 | length 26
  Top Layer w9.7: L1.2@2104.93,946.22 R77.1@2104.93,972.22
NetL2_2: L2.2 R80.1 | length 26
  Top Layer w9.7: L2.2@2171.97,946.22 R80.1@2171.97,972.22
NetQ2_3: Q2.3 R17.1 | length 181.6
  Bottom Layer w9.7: R17.1@1065,2515 1071.82,2521.82 1101.43,2521.82 1119.42,2539.81 1119.42,2644.44 Q2.3@1110.75,2653.11
NetQ3_3: Q3.3 R24.1 | length 181.6
  Bottom Layer w9.7: R24.1@1160,2515 1166.82,2521.82 1196.43,2521.82 1214.42,2539.81 1214.42,2644.44 Q3.3@1205.75,2653.11
NetR1_2: R1.2 SW1.2 U1.3 U1.4 U1.5
NetR2_2: R2.2 U1.10 | length 50
  Bottom Layer w8: U1.10@1240.59,408.64 R2.2@1290.59,408.64
NetR6_1: R6.1 U2.1 | length 43
  Bottom Layer w8: U2.1@1090.88,641.15 R6.1@1133.88,641.15
NetR7_1: R7.1 R8.2 U2.6 | length 71.3
  Bottom Layer w12: R8.2@1002.1,759.83 R7.1@1035.7,759.83 1035.7,757.86 1039.7,753.86 U2.6@1039.7,723.83
NetR11_1: R11.1 R13.2 U3.22 | length 92.7
  Bottom Layer w8: R13.2@149.89,836.12 R11.1@183.89,836.12 183.89,860.44 170.5,873.83 170.5,888.02 U3.22@169.58,888.94
NetR12_2: R12.2 U3.23 | length 68.1
  Bottom Layer w8: R12.2@115.89,836.12 115.89,838.09 121.73,843.93 123.7,843.93 149.9,870.13 U3.23@149.9,888.94
NetR15_1: R15.1 R22.1 R25.1 U5.3 U7.3 | length 869.8
  Top Layer w8: v1(539.22,1132.05) U7.3@562.41,1132.05 ; v1(539.3,1532.05) U5.3@562.48,1532.05
  Bottom Layer w5: R22.1@361.48,836.12 422.94,836.12 541.95,955.13 R25.1@541.95,1129.32 ; v1(539.22,1132.05) 541.26,1132.05 548.61,1139.39 548.61,1141.43 561.38,1154.2 561.38,1205.1 544.14,1222.33 544.14,1527.2 v1(539.3,1532.05)
NetR18_1: R18.1 R19.2 U5.5 | length 206.8
  Top Layer w8: v1(562.41,1487.68) U5.5@562.41,1492.68
  Bottom Layer w8: v1(562.41,1487.68) 581.13,1487.68 612.83,1519.38 612.83,1520.55 619.35,1527.08 619.35,1540.67 631.55,1552.86 633.21,1552.86 671.45,1591.1 v1@712.72,1591.1
  other v1: 709.12,1591.1
NetR20_1: R20.1 R21.2
NetR27_1: R27.1 R28.2 U7.5 | length 206.8
  Top Layer w8: v1(562.41,1087.68) U7.5@562.41,1092.68
  Bottom Layer w8: v1(562.41,1087.68) 581.13,1087.68 612.83,1119.38 612.83,1120.55 619.35,1127.08 619.35,1140.67 631.55,1152.86 633.21,1152.86 671.45,1191.1 v1@712.72,1191.1
  other v1: 709.12,1191.1
NetR29_1: R29.1 R30.2
NetR31_1: R31.1 U8.12 | length 50
  Bottom Layer w5: U8.12@1223.78,1977.82 R31.1@1223.78,2027.82
NetR32_1: R32.1 U8.1 | length 50
  Bottom Layer w5: U8.1@1334.01,1977.82 R32.1@1334.01,2027.82
NetR35_1: R35.1 U10.16 | length 55
  Top Layer w8: R35.1@415,2070.17 U10.16@470,2070.17
NetR38_1: R38.1 U10.26 | length 65.9
  Top Layer w5: U10.26@719.02,1998.32 v1(719.02,2048.32)
  Bottom Layer w5: v1(719.02,2048.32) R38.1@719.02,2064.17
NetR39_1: R39.1 U9.6 | length 50.1
  Bottom Layer w5: U9.6@738.7,2142.22 738.7,2120.72 758.39,2101.04 R39.1@758.39,2100.25
NetR40_1: R40.1 U10.14 | length 60.1
  Top Layer w12: R40.1@410,2109.22 437.2,2109.22 437.52,2109.54 U10.14@470,2109.54
NetR42_2: R42.2 U10.7 | length 103.5
  Top Layer w8: R42.2@369.53,2254.74 381.34,2254.74 388.74,2247.34 U10.7@470,2247.34
NetR43_2: R43.2 U10.8 | length 103.5
  Top Layer w8: R43.2@369.53,2220.25 381.34,2220.25 388.74,2227.65 U10.8@470,2227.65
NetR45_2: R45.2 U10.6 | length 95.5
  Top Layer w8: v1@510,2267.02 U10.6@470,2267.02 470.73,2266.29 508.02,2266.29 511.29,2263.02 v1(514,2263.02)
  Bottom Layer w8: R45.2@510,2267.02 512,2265.02 R45.2@512,2257.98
NetR46_1: R46.1 U10.62 U11.2 | length 216.5
  Top Layer w8: U10.62@581.22,2437.3 581.67,2437.75 581.67,2472.75 v1(596.22,2487.3)
  Bottom Layer w8: U11.2@582.21,2333.95 582.21,2473.28 588.41,2479.49 590.38,2479.49 596.22,2485.33 v1(596.22,2487.3)
NetR47_1: R47.1 R49.1 U11.4 | length 84.6
  Bottom Layer w8: U11.4@633.39,2333.95 633.39,2375.6 637.48,2379.69 637.48,2381.65 643.32,2387.5 R47.1@670.29,2387.5
NetR48_1: R48.1 U10.63 U11.1 | length 205.4
  Top Layer w8: U10.63@561.54,2437.3 v1(561.54,2487.3)
  Bottom Layer w8: U11.1@556.61,2333.95 556.61,2482.38 v1(561.54,2487.3)
NetR49_2: R49.2 U10.61 U11.3 | length 106.2
  Top Layer w8: U10.61@600.91,2437.3 600.91,2395.21 605.92,2390.2 v1(605.92,2387.5)
  Bottom Layer w8: v1(605.92,2387.5) 607.8,2385.62 U11.3@607.8,2333.95
NetR50_1: R50.1 SW2.2 | length 60
  Bottom Layer w12: SW2.2@107.48,1915 R50.1@167.48,1915
NetR54_2: R54.2 U13.11 U15.1 | length 341.7
  L5 SIG w5: v1(1109.53,2192.04) 1109.53,2153.32 1145.46,2117.39 1181.19,2117.39 1189.76,2125.97 1293.81,2125.97 1333.81,2085.97 1338.07,2081.71 v1(1350,2081.71)
  Bottom Layer w5: U13.11@1099.53,2192.04 v1(1109.53,2192.04)
  Bottom Layer w9: U15.1@1350,2065.97 v1(1350,2081.71)
NetR56_1: R56.1 U15.4 | length 47.4
  Bottom Layer w5: U15.4@1310.63,2124.23 1310.63,2131.52 1315.96,2136.85 1317.13,2136.85 1337.95,2157.67 R56.1@1337.95,2159.64
NetR62_1: R62.1 R63.2 | length 551.9
  Top Layer w9.7: R63.2@1483.16,1508.05 1741.08,1508.05 cw(c1741.08,1408.05) 1811.79,1478.76 1854.39,1436.16 cw(c1784.95,1366.72) 1883.16,1366.72 R62.1@1883.16,1288.62
NetR67_2: R67.2 R68.1 | length 551.9
  Top Layer w9.7: R67.2@1483.16,958.05 1741.08,958.05 ccw(c1741.08,1058.05) 1811.79,987.34 1854.39,1029.94 ccw(c1784.95,1099.38) 1883.16,1099.38 R68.1@1883.16,1177.48
NetR72_1: R72.1 SW3.2 | length 75
  Bottom Layer w5: SW3.2@2948.45,98.72 R72.1@3023.45,98.72
NetR75_2: R75.2 R76.1 R77.2 R78.2 | length 88.7
  Top Layer w9.7: R75.2@2076.93,994.26 R77.2@2104.93,994.26 R78.2@2104.93,1017.26 2104.93,1020.04 cw(c2127.15,1020.04) R76.1@2127.15,1042.26
NetR79_1: R79.1 R80.2 R83.2 R84.1 | length 88.7
  Top Layer w9.7: R84.1@2149.75,1042.26 cw(c2149.75,1020.04) 2171.97,1020.04 R79.1@2171.97,1017.26 R80.2@2171.97,994.26 R83.2@2199.97,994.26
NetR87_1: R87.1 U17.26 | length 45.8
  Top Layer w5: U17.26@2264.43,1256.67 2283.34,1256.67 2297.34,1242.67 R87.1@2304.43,1242.67
NetR88_1: R88.1 U17.38 | length 41.5
  Top Layer w5: R88.1@2127.07,1383.29 2127.07,1376.2 2130.57,1372.7 U17.38@2130.57,1343.29
NetR90_1: R90.1 U17.37 | length 41.6
  Top Layer w5: U17.37@2146.32,1343.29 2146.32,1355.1 2150.07,1358.84 R90.1@2150.07,1383.29
NetR91_1: R91.1 U17.36 | length 44.6
  Top Layer w5: U17.36@2162.07,1343.29 2162.07,1366.19 2169.49,1373.61 2169.49,1379.7 R91.1@2173.07,1383.29
NetR92_1: R92.1 U17.35 | length 47.6
  Top Layer w5: U17.35@2177.82,1343.29 2177.82,1364.25 2196.07,1382.5 R92.1@2196.07,1383.29
NetR92_2: R92.2 R113.2 R117.2 | length 179
  Top Layer w5: R92.2@2196.07,1405.33 2196.07,1427.36 2210.21,1441.5 R117.2@2347.23,1441.5
NetR93_1: R93.1 U17.34 | length 50.6
  Top Layer w5: U17.34@2193.56,1343.29 2194.31,1344.03 2194.31,1357.74 2219.07,1382.5 R93.1@2219.07,1383.29
NetR94_1: R94.1 U17.33 | length 59.6
  Top Layer w5: U17.33@2209.31,1343.29 2209.31,1360.01 2218,1368.7 2227.74,1368.7 2235.61,1376.57 2236.14,1376.57 2242.07,1382.5 R94.1@2242.07,1383.29
NetR95_1: R95.1 U17.32 | length 62.6
  Top Layer w5: U17.32@2225.06,1343.29 2226.5,1344.72 2226.5,1354.18 2241.02,1368.7 2251.27,1368.7 2265.07,1382.5 R95.1@2265.07,1383.29
NetR97_1: R97.1 U17.30 | length 46.2
  Top Layer w5: U17.30@2264.43,1319.66 2282.34,1319.66 2297.34,1334.67 R97.1@2304.43,1334.67
NetR98_1: R98.1 U17.29 | length 43.2
  Top Layer w5: U17.29@2264.43,1303.92 2289.59,1303.92 2297.34,1311.67 R98.1@2304.43,1311.67
NetR99_1: R99.1 U17.28 | length 40.2
  Top Layer w5: U17.28@2264.43,1288.17 2296.84,1288.17 2297.34,1288.67 R99.1@2304.43,1288.67
NetR100_1: R100.1 U17.27 | length 42.8
  Top Layer w5: U17.27@2264.43,1272.42 2284.09,1272.42 2290.84,1265.67 R100.1@2304.43,1265.67
NetR101_1: R101.1 U17.24 | length 42.3
  Top Layer w5: U17.24@2264.43,1225.18 2291.84,1225.18 2297.34,1219.67 R101.1@2304.43,1219.67
NetR102_1: R102.1 U17.23 | length 45.3
  Top Layer w5: U17.23@2264.43,1209.43 2284.59,1209.43 2297.34,1196.67 R102.1@2304.43,1196.67
NetR103_1: R103.1 U17.22 | length 48.3
  Top Layer w5: U17.22@2264.43,1193.68 2283.64,1193.68 2303.64,1173.67 R103.1@2304.43,1173.67
NetR104_1: R104.1 U17.21 | length 51.3
  Top Layer w5: U17.21@2264.43,1177.93 2276.24,1177.93 2277.68,1176.49 2277.82,1176.49 2303.64,1150.67 R104.1@2304.43,1150.67
NetR105_1: R105.1 U17.20 | length 49
  Top Layer w5: U17.20@2240.81,1154.31 2240.81,1141.36 2258.77,1123.4 2258.77,1118.11 R105.1@2262.56,1114.31
NetR106_1: R106.1 U17.19 | length 46
  Top Layer w5: U17.19@2225.06,1154.31 2225.06,1135.9 2239.56,1121.4 R106.1@2239.56,1114.31
NetR107_1: R107.1 U17.18 | length 43
  Top Layer w5: U17.18@2209.31,1154.31 2209.31,1128.65 2216.56,1121.4 R107.1@2216.56,1114.31
NetR108_2: R108.2 U17.1 | length 50
  Top Layer w8: v1@2025.45,1319.66 U17.1@2075.45,1319.66
  other v1: 2025.69,1319.66
NetR109_2: R109.2 U17.10 | length 97.9
  Top Layer w5: v1(2005.45,1146.93) 2004.06,1146.93 2002.94,1148.05 2003.05,1148.05 2010.31,1155.3 2010.31,1155.41 2032.83,1177.93 U17.10@2075.45,1177.93
  Bottom Layer w8: R109.2@2005.45,1136.93 v1(2005.45,1146.93)
NetR111_2: R111.2 U18.1 | length 43.5
  Bottom Layer w12: U18.1@1526.21,627.87 R111.2@1526.21,671.34
NetR112_2: R112.2 SW4.1 U19.2 | length 113.2
  Bottom Layer w12: U19.2@1520.3,408.64 1554.43,408.64 1566.22,396.85 1566.22,335.65 v1(1567.09,334.78)
NetR115_2: R115.2 U17.40 | length 47.5
  Top Layer w5: R115.2@2081.07,1383.29 2081.07,1382.5 2099.08,1364.49 U17.40@2099.08,1343.29
NetR116_2: R116.2 U17.39 | length 44.5
  Top Layer w5: R116.2@2104.07,1383.29 2104.07,1376.2 2114.82,1365.44 U17.39@2114.82,1343.29
NetR118_2: R118.2 U18.3 | length 43.5
  Bottom Layer w12: U18.3@1601.01,627.87 R118.2@1601.01,671.34
NetR119_2: R119.2 U17.17 | length 40
  Top Layer w5: R119.2@2193.56,1114.31 2193.56,1142.5 U17.17@2193.56,1154.31
NetR120_1: R120.1 SW5.1 | length 42.4
  Bottom Layer w12: v1(1638.21,1743.5) R120.1@1668.21,1713.5
NetR121_1: R121.1 U20.3 | length 42.4
  Bottom Layer w12: R121.1@1870.58,1647.13 U20.3@1900.58,1617.13
NetR123_2: R123.2 SW5.2 | length 42.4
  Bottom Layer w12: v1(1673.56,1778.85) R123.2@1703.56,1748.85
NetR126_2: R126.2 U21.3 | length 37.1
  Top Layer w10: U21.3@3319.06,264.36 3333.82,264.36 3338.82,269.36 R126.2@3354.06,269.36
NetR138_1: R138.1 R180.2 U22.1 U22.28 U22.29 U22.30 U22.56 | length 1330.5
  Top Layer w5: v1(2575,1524.39) R138.1@2575,1550 ; v1(2610,1002.73) 2619.84,992.89 v1(2865,992.89)
  L5 SIG w5: v1(2575,1524.39) 2664.65,1524.39 2705.54,1524.39 ; v1(2865,992.89) 2704.94,1152.95 2704.94,1523.79 2705.54,1524.39 ; v1(2916.56,1524.39) 2705.54,1524.39
  Bottom Layer w5: v1(2575,1524.39) U22.56@2610,1524.39 ; v1(2865,992.89) U22.28@2905.28,992.89 ; U22.1@2905.28,1524.39 v1(2916.56,1524.39)
  Bottom Layer w8: U22.29@2610,992.89 v1(2610,1002.73) U22.30@2610,1012.58
NetR139_2: R139.2 R140.1 | length 251.2
  Top Layer w5: R139.2@2620.76,1507.7 2864.86,1507.7 R140.1@2871.95,1507.7
NetR141_2: R141.2 R142.1 | length 251.2
  Top Layer w5: R141.2@2643.33,1485.02 2887.42,1485.02 R142.1@2894.51,1485.02
NetR143_2: R143.2 R144.1 | length 251.2
  Top Layer w5: R143.2@2620.76,1448.65 2864.86,1448.65 R144.1@2871.95,1448.65
NetR145_2: R145.2 R146.1 | length 251.2
  Top Layer w5: R145.2@2643.33,1425.96 2887.42,1425.96 R146.1@2894.51,1425.96
NetR149_1: R149.1 U23.4 | length 35
  Bottom Layer w5: R149.1@1034.92,2365.11 U23.4@1034.92,2400.11
NetR150_2: R150.2 R151.1 | length 251.2
  Top Layer w5: R150.2@2620.76,1389.59 2864.86,1389.59 R151.1@2871.95,1389.59
NetR152_2: R152.2 R153.1 | length 251.2
  Top Layer w5: R152.2@2643.33,1366.91 2887.42,1366.91 R153.1@2894.51,1366.91
NetR154_2: R154.2 R155.1 | length 251.2
  Top Layer w5: R154.2@2620.76,1344.22 R155.1@2871.95,1344.22
NetR156_2: R156.2 R157.1 | length 273.7
  Top Layer w5: R156.2@2620.76,1310.85 R157.1@2894.51,1310.85
NetR158_2: R158.2 R159.1 | length 188.6
  Top Layer w5: R158.2@2663.33,1288.17 R159.1@2851.95,1288.17
NetR160_2: R160.2 R161.1 | length 273.7
  Top Layer w5: R160.2@2620.76,1268.48 R161.1@2894.51,1268.48
NetR162_2: R162.2 R163.1 | length 188.6
  Top Layer w5: R162.2@2663.33,1248.8 R163.1@2851.95,1248.8
NetR164_2: R164.2 R165.1 | length 273.7
  Top Layer w5: R164.2@2620.76,1229.11 2887.42,1229.11 R165.1@2894.51,1229.11
NetR166_2: R166.2 R167.1 | length 228.6
  Top Layer w5: R166.2@2643.33,1206.43 R167.1@2871.95,1206.43
NetR168_2: R168.2 R169.1 | length 251.2
  Top Layer w5: R168.2@2620.76,1173.06 2864.86,1173.06 R169.1@2871.95,1173.06
NetR170_2: R170.2 R171.1 | length 251.2
  Top Layer w5: R170.2@2643.33,1150.37 2887.42,1150.37 R171.1@2894.51,1150.37
NetR172_2: R172.2 R173.1 | length 251.2
  Top Layer w5: R172.2@2620.76,1127.69 R173.1@2871.95,1127.69
NetR174_2: R174.2 R175.1 | length 251.2
  Top Layer w5: R174.2@2620.76,1094.32 R175.1@2871.95,1094.32
NetR176_2: R176.2 R177.1 | length 251.2
  Top Layer w5: R176.2@2643.33,1071.63 R177.1@2894.51,1071.63
NetR178_2: R178.2 R179.1 | length 228.6
  Top Layer w5: R178.2@2643.33,1032.26 R179.1@2871.95,1032.26
NetSW2_1: SW2.1 U12.1 U12.5 U14.15 | length 2403.3
  Top Layer w5: v1(1208.98,2284.23) 1173.35,2284.23 1154.53,2303.05 1154.53,2345.64 ; v1(1208.98,2362.97) 1171.86,2362.97 1154.53,2345.64 ; v1(1299.02,2154.64) 1269.38,2154.64 1237.25,2122.52 1186.32,2122.52 1181.19,2117.39 1134.92,2117.39 1088.67,2163.64 1038.73,2163.64 992.48,2209.89 992.48,2242.28 966.29,2268.47 966.29,2314.4 976.23,2324.34 1154.53,2324.34 1154.53,2345.64
  L5 SIG w5: SW2.1@107.48,1815 340,1815 566.72,2041.72 566.72,2188.52 713.83,2335.63 713.83,2337.27 781.12,2404.56 1001.89,2404.56 1122.22,2284.23 v1(1208.98,2284.23)
  Bottom Layer w5: v1(1208.98,2284.23) U12.1@1228.98,2284.23 ; v1(1208.98,2362.97) U12.5@1228.98,2362.97 ; U14.15@1274.02,2154.64 v1(1299.02,2154.64)
NetSW3_1: SW3.1 U16.9 | length 826.5
  Top Layer w5: U16.9@2607.07,825.27 2607.07,518.12 2848.45,276.74 SW3.1@2848.45,98.72
NetU18_4: U18.4 U19.4 | length 94.7
  Bottom Layer w12: U18.4@1601.01,525.51 cw(c1601.01,519.61) 1606.92,519.61 U19.4@1606.92,434.23
PDN/SYNC: J10.3 R132.1 | length 864.4
  Top Layer w5: v1(3304.37,1308.27) R132.1@3314.37,1308.27
  L5 SIG w5: J10.3@2672.46,1788.88 2863.7,1788.88 2919.31,1733.27 2919.31,1693.33 v1(3304.37,1308.27)
PG-C2M: J1.D1 R128.2 | length 50
  Top Layer w12: R128.2@3622.44,2360 3623.23,2360 3648.81,2334.42 3660.27,2334.42 v1(3661.42,2333.27)
PG-M2C: J1.F1 R128.1 | length 50
  Top Layer w12: v1(3561.42,2333.27) 3562.57,2334.42 3574.02,2334.42 3599.61,2360 R128.1@3600.39,2360
PRSNT-M2C-L: J1.H2 R137.2 | length 5.3
  Top Layer w10: R137.2@3461.42,2277.95 v1(3461.42,2283.27)
RESET: C72.2 PP10.1 R109.1 R110.1 R111.1 R114.2 R118.1 | length 783.2
  Bottom Layer w5: R114.2@1638.41,710.71 1638.41,827.76 1882.91,1072.26 1942.44,1072.26 1985.06,1114.88 R109.1@2005.45,1114.88
  Bottom Layer w12: PP10.1@1458.21,710.71 R111.1@1526.21,710.71 C72.2@1563.61,710.71 R118.1@1601.01,710.71 R114.2@1638.41,710.71
SCL_I2C: PP6.1 U8.14 U12.6 U21.6 | length 6138.2
  Top Layer w5: v1(3147.87,225) 3150.36,227.49 3157.95,227.49 3168.23,237.76 3168.23,257.77 3174.82,264.36 U21.6@3201.8,264.36
  L5 SIG w5: v1(1269.05,2013.41) 1266.57,2010.92 1266.57,2003.87 1265.87,2003.17 1265.87,1986.58 1246.61,1967.32 1224.4,1967.32 1199.09,1992.63 1032.58,1992.63 986.08,2039.13 986.08,2217.17 1014.43,2245.51 1266.78,2245.51 1318.35,2297.08 1318.35,2329.47 PP6.1@1351.85,2362.97 1351.85,2443.99 1525.94,2618.09 3315.56,2618.09 3539.7,2393.95 3539.7,1119.7 3628.21,1031.19 3628.21,827.47 3553.52,752.78 3303.53,752.78 3220.91,670.17 3220.91,308.82 3199.85,287.76 3199.85,255.56 3169.29,225 v1(3147.87,225)
  Bottom Layer w5: U12.6@1261.85,2362.97 PP6.1@1351.85,2362.97
SCL_Local: J1.C30 R130.2
  other v1: 3711.42,883.27
SCLK_DUT: PP7.1 R115.1 U14.2 | length 1307.8
  Top Layer w5: v1(1234.65,2106.02) 1254.59,2125.97 PP7.1@1385,2125.97 1581.63,2125.97 2081.07,1626.53 R115.1@2081.07,1405.33
  Bottom Layer w5: v1(1234.65,2106.02) U14.2@1234.65,2131.02
SDA_I2C: PP5.1 U8.13 U12.10 U21.5 | length 5729.3
  Top Layer w5: v1(3147.87,264.37) 3167.55,284.05 ; U21.5@3201.8,284.05 3168.23,284.05 ; 3167.55,284.05 3168.23,284.05 ; 3167.55,284.05 3168.23,284.05
  L5 SIG w5: v1(1249.37,1993.41) 1087.29,2155.49 1087.29,2201.16 1108.93,2222.79 1329.99,2222.79 1348.2,2241 1348.2,2280.58 PP5.1@1351.85,2284.23 1351.85,2309.78 1385,2342.93 1385,2446.97 1546.11,2608.09 3311.42,2608.09 3528.65,2390.86 3528.65,1107.02 3590.66,1045 3590.66,810.66 3545.25,765.24 3259.96,765.24 3147.87,653.16 v1(3147.87,264.37)
  Bottom Layer w5: U12.10@1261.85,2284.23 PP5.1@1351.85,2284.23
SDA_Local: J1.C31 R131.2
  other v1: 3711.42,833.27
SDIO_DUT: PP9.1 R116.1 U14.7 | length 1535.8
  Top Layer w5: v1(1154.53,2165.39) 1203.09,2213.95 1357.01,2213.95 PP9.1@1385,2185.97 1630.05,2185.97 ; 1647.42,2168.6 1630.05,2185.97 ; R116.1@2104.07,1405.33 2104.07,1711.95 1630.05,2185.97
  Bottom Layer w5: v1(1154.53,2165.39) 1157.23,2165.39 1162.23,2170.39 U14.7@1179.53,2170.39
SEN_DUT: PP8.1 R119.1 U14.5 | length 2063.2
  Top Layer w5: v1(2193.56,1082.26) R119.1@2193.56,1092.26
  L5 SIG w5: v1(1154.53,2133.89) 1154.53,2144.88 1132.12,2167.29 1132.12,2205.02 1138.97,2211.86 1359.1,2211.86 1385,2237.76 PP8.1@1385,2245.97
  Bottom Layer w5: v1(1154.53,2133.89) 1157.23,2133.89 1162.23,2138.89 U14.5@1179.53,2138.89 ; PP8.1@1385,2245.97 1449.66,2245.97 1602.43,2093.19 1602.43,1569.45 1684.54,1487.34 1684.54,1463.02 1784.28,1363.29 1784.28,1361.98 1919.33,1226.93 2118.71,1226.93 2135.43,1210.22 2135.43,1190.34 2133.12,1188.03 2133.12,1131.01 2152.3,1111.84 2179.36,1111.84 2193.56,1097.63 v1(2193.56,1082.26)
SMA_CLK_N: C53.2 J5.1 R67.1 | length 200
  Top Layer w9.7: J5.1@1261.11,958.05 C53.2@1461.11,958.05
SMA_CLK_P: J4.1 R63.1 | length 200
  Top Layer w9.7: J4.1@1261.11,1508.05 R63.1@1461.11,1508.05
TDI_FMC: J1.D30 R129.2 | length 13.3
  Top Layer w10: R129.2@3661.42,869.98 v1(3661.42,883.27)
TDO_FMC: J1.D31 R129.1 | length 14.7
  Top Layer w10: v1(3661.42,833.27) R129.1@3661.42,847.93
USB_5V: D6.1 R41.2 | length 72.4
  Bottom Layer w18: R41.2@218.64,2024.59 255.06,2024.59 v1(280.47,2050)
USB_I2C_SCL: R33.1 R38.2 U9.7 | length 56
  Bottom Layer w5: R38.2@719.02,2086.22 719.02,2093.3 R33.1@719.02,2106.22 719.02,2116.06 U9.7@719.02,2142.22
USB_I2C_SDAr: R37.2 R39.2 U10.28 U12.9 | length 804.4
  Top Layer w5: U10.28@758.39,1998.32 758.39,2034.35 v1(784.92,2060.88)
  L5 SIG w5: v1(784.92,2060.88) 882.7,2060.88 921.46,2099.64 921.46,2179.39 999.16,2257.09 1233.54,2257.09 1280.35,2303.91 v1(1301.85,2303.91)
  Bottom Layer w5: R39.2@758.39,2060.88 v1(784.92,2060.88) ; U12.9@1261.85,2303.91 v1(1301.85,2303.91)
USB_I2C_SDAw: R36.1 U9.1 U10.27 | length 320.3
  Top Layer w5: v1(699.33,2211.86) 738.7,2172.49 U10.27@738.7,1998.32
  Bottom Layer w5: v1(699.33,2211.86) U9.1@699.33,2264.27 R36.1@699.33,2302.27
VADJ: J1.E39 J1.F40 J1.G39 J1.H40
  other v1: 3461.42,383.27 3561.42,383.27 3511.42,433.27 3611.42,433.27
VCM: C61.2 C70.2 C71.2 R78.1 R79.2 TP3.1 U17.9 | length 60.6
  Top Layer w8: v1(2055.45,1194.68) 2056.45,1193.68 U17.9@2075.45,1193.68
  Bottom Layer w8: C70.2@2045.02,1194.68 v1(2055.45,1194.68)
  Bottom Layer w9: C71.2@2045.02,1169.68 2045.81,1169.68 2051.74,1175.61 2051.74,1184.91 2053.73,1186.9 2053.73,1192.96 v1(2055.45,1194.68)
  other v1: 2138.45,999.26
VCORE: C36.2 U10.12 U10.37 U10.49 U10.64 | length 92.5
  Top Layer w5: v1(873.98,2148.91) U10.37@908.5,2148.91
  Top Layer w12: U10.12@470,2148.91 v1(520,2148.91)
  Bottom Layer w12: v1@512,2148.91 v1(520,2148.91)
  other v1: 531.85,2417.3 855,2436.85 531.85,2437.3 531.85,2457.3
VREF: C74.2 C75.2 C76.2 J11.2 R122.2 U17.2 | length 58.3
  Top Layer w8: C76.2@2046.45,1298.92 v1(2050.45,1298.92) cw(c2062.53,1286.84) 2062.53,1303.92 U17.2@2075.45,1303.92
  Bottom Layer w14: C74.2@2055.28,1298.89 C75.2@2055.28,1326.89
  other v1: 2056.8,1374.13
pads on no net: FID1.1 FID2.1 FID3.1 H1. H3. J1. J1.A2 J1.A3 J1.A6 J1.A7 J1.A10 J1.A11 J1.A14 J1.A15 J1.A18 J1.A19 J1.A22 J1.A23 J1.A26 J1.A27 J1.A30 J1.A31 J1.A34 J1.A35 J1.A38 J1.A39 J1.B1 J1.B4 J1.B5 J1.B8 J1.B9 J1.B12 J1.B13 J1.B16 J1.B17 J1.B20 J1.B21 J1.B24 J1.B25 J1.B28 J1.B29 J1.B32 J1.B33 J1.B36 J1.B37 J1.C2 J1.C3 J1.C6 J1.C7 J1.C11 J1.C15 J1.C19 J1.C23 J1.C26 J1.C27 J1.C39 J1.D4 J1.D5 J1.D9 J1.D12 J1.D15 J1.D18 J1.D21 J1.D23 J1.D24 J1.D26 J1.D27 J1.D29 J1.D33 J1.D34 J1.D36 J1.D38 J1.D40 J1.E2 J1.E3 J1.E6 J1.E7 J1.E9 J1.E10 J1.E12 J1.E13 J1.E15 J1.E16 J1.E18 J1.E19 J1.E21 J1.E22 J1.E24 J1.E25 J1.E27 J1.E28 J1.E30 J1.E31 J1.E33 J1.E34 J1.E36 J1.E37 J1.F4 J1.F5 J1.F7 J1.F8 J1.F10 J1.F11 J1.F13 J1.F14 J1.F16 J1.F17 J1.F19 J1.F20 J1.F22 J1.F23 J1.F25 J1.F26 J1.F28 J1.F29 J1.F31 J1.F32 J1.F34 J1.F35 J1.F37 J1.F38 J1.G2 J1.G3 J1.G7 J1.G10 J1.G13 J1.G16 J1.G19 J1.G22 J1.G24 J1.G25 J1.G27 J1.G34 J1.G36 J1.G37 J1.H1 J1.H5 J1.H8 J1.H11 J1.H14 J1.H17 J1.H20 J1.H22 J1.H23 J1.H25 J1.H26 J1.H28 J1.H29 J1.H31 J1.H32 J1.H34 J1.H35 J1.H37 J1.H38 J1.J2 J1.J3 J1.J6 J1.J7 J1.J9 J1.J10 J1.J12 J1.J13 J1.J15 J1.J16 J1.J18 J1.J19 J1.J21 J1.J22 J1.J24 J1.J25 J1.J27 J1.J28 J1.J30 J1.J31 J1.J33 J1.J34 J1.J36 J1.J37 J1.J39 J1.K1 J1.K4 J1.K5 J1.K7 J1.K8 J1.K10 J1.K11 J1.K13 J1.K14 J1.K16 J1.K17 J1.K19 J1.K20 J1.K22 J1.K23 J1.K25 J1.K27 J1.K28 J1.K29 J1.K31 J1.K32 J1.K34 J1.K35 J1.K37 J1.K38 J1.K40 J3. J3.A5 J3.A8 J3.B5 J3.B8 Q1.0 Q2.1@1095,2645.24 Q2.2@1095,2660.98 Q3.1@1190,2645.24 Q3.2@1190,2660.98 R85.1 R85.2 R86.1 R86.2 SH-J1.0 U1.9 U2.0 U3.4 U10.21 U10.22 U10.23 U10.24 U10.29 U10.30 U10.32 U10.33 U10.34 U10.36 U10.38 U10.39 U10.40 U10.41 U10.43 U10.44 U10.45 U10.46 U10.48 U10.52 U10.53 U10.54 U10.55 U10.57 U10.58 U10.59 U10.60 U11.6 U11.7 U12.3@1228.98,2323.6 U12.8@1261.85,2323.6 U14.10 U14.11 U14.12 U16.2 U16.4 U16.7 U20.5 U22.27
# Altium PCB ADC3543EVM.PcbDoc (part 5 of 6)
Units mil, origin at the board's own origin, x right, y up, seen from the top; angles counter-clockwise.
Board outline 3900 x 2716.54 mil, 10 copper layers (Top Layer, L2 GND, L3 PWR, L4 GND, L5 SIG, L6 GND, L7 GND, L8 PWR, L9 GND, Bottom Layer), stack 61.2 mil thick; 352 components, 249 nets, 1505 pads, 904 vias.

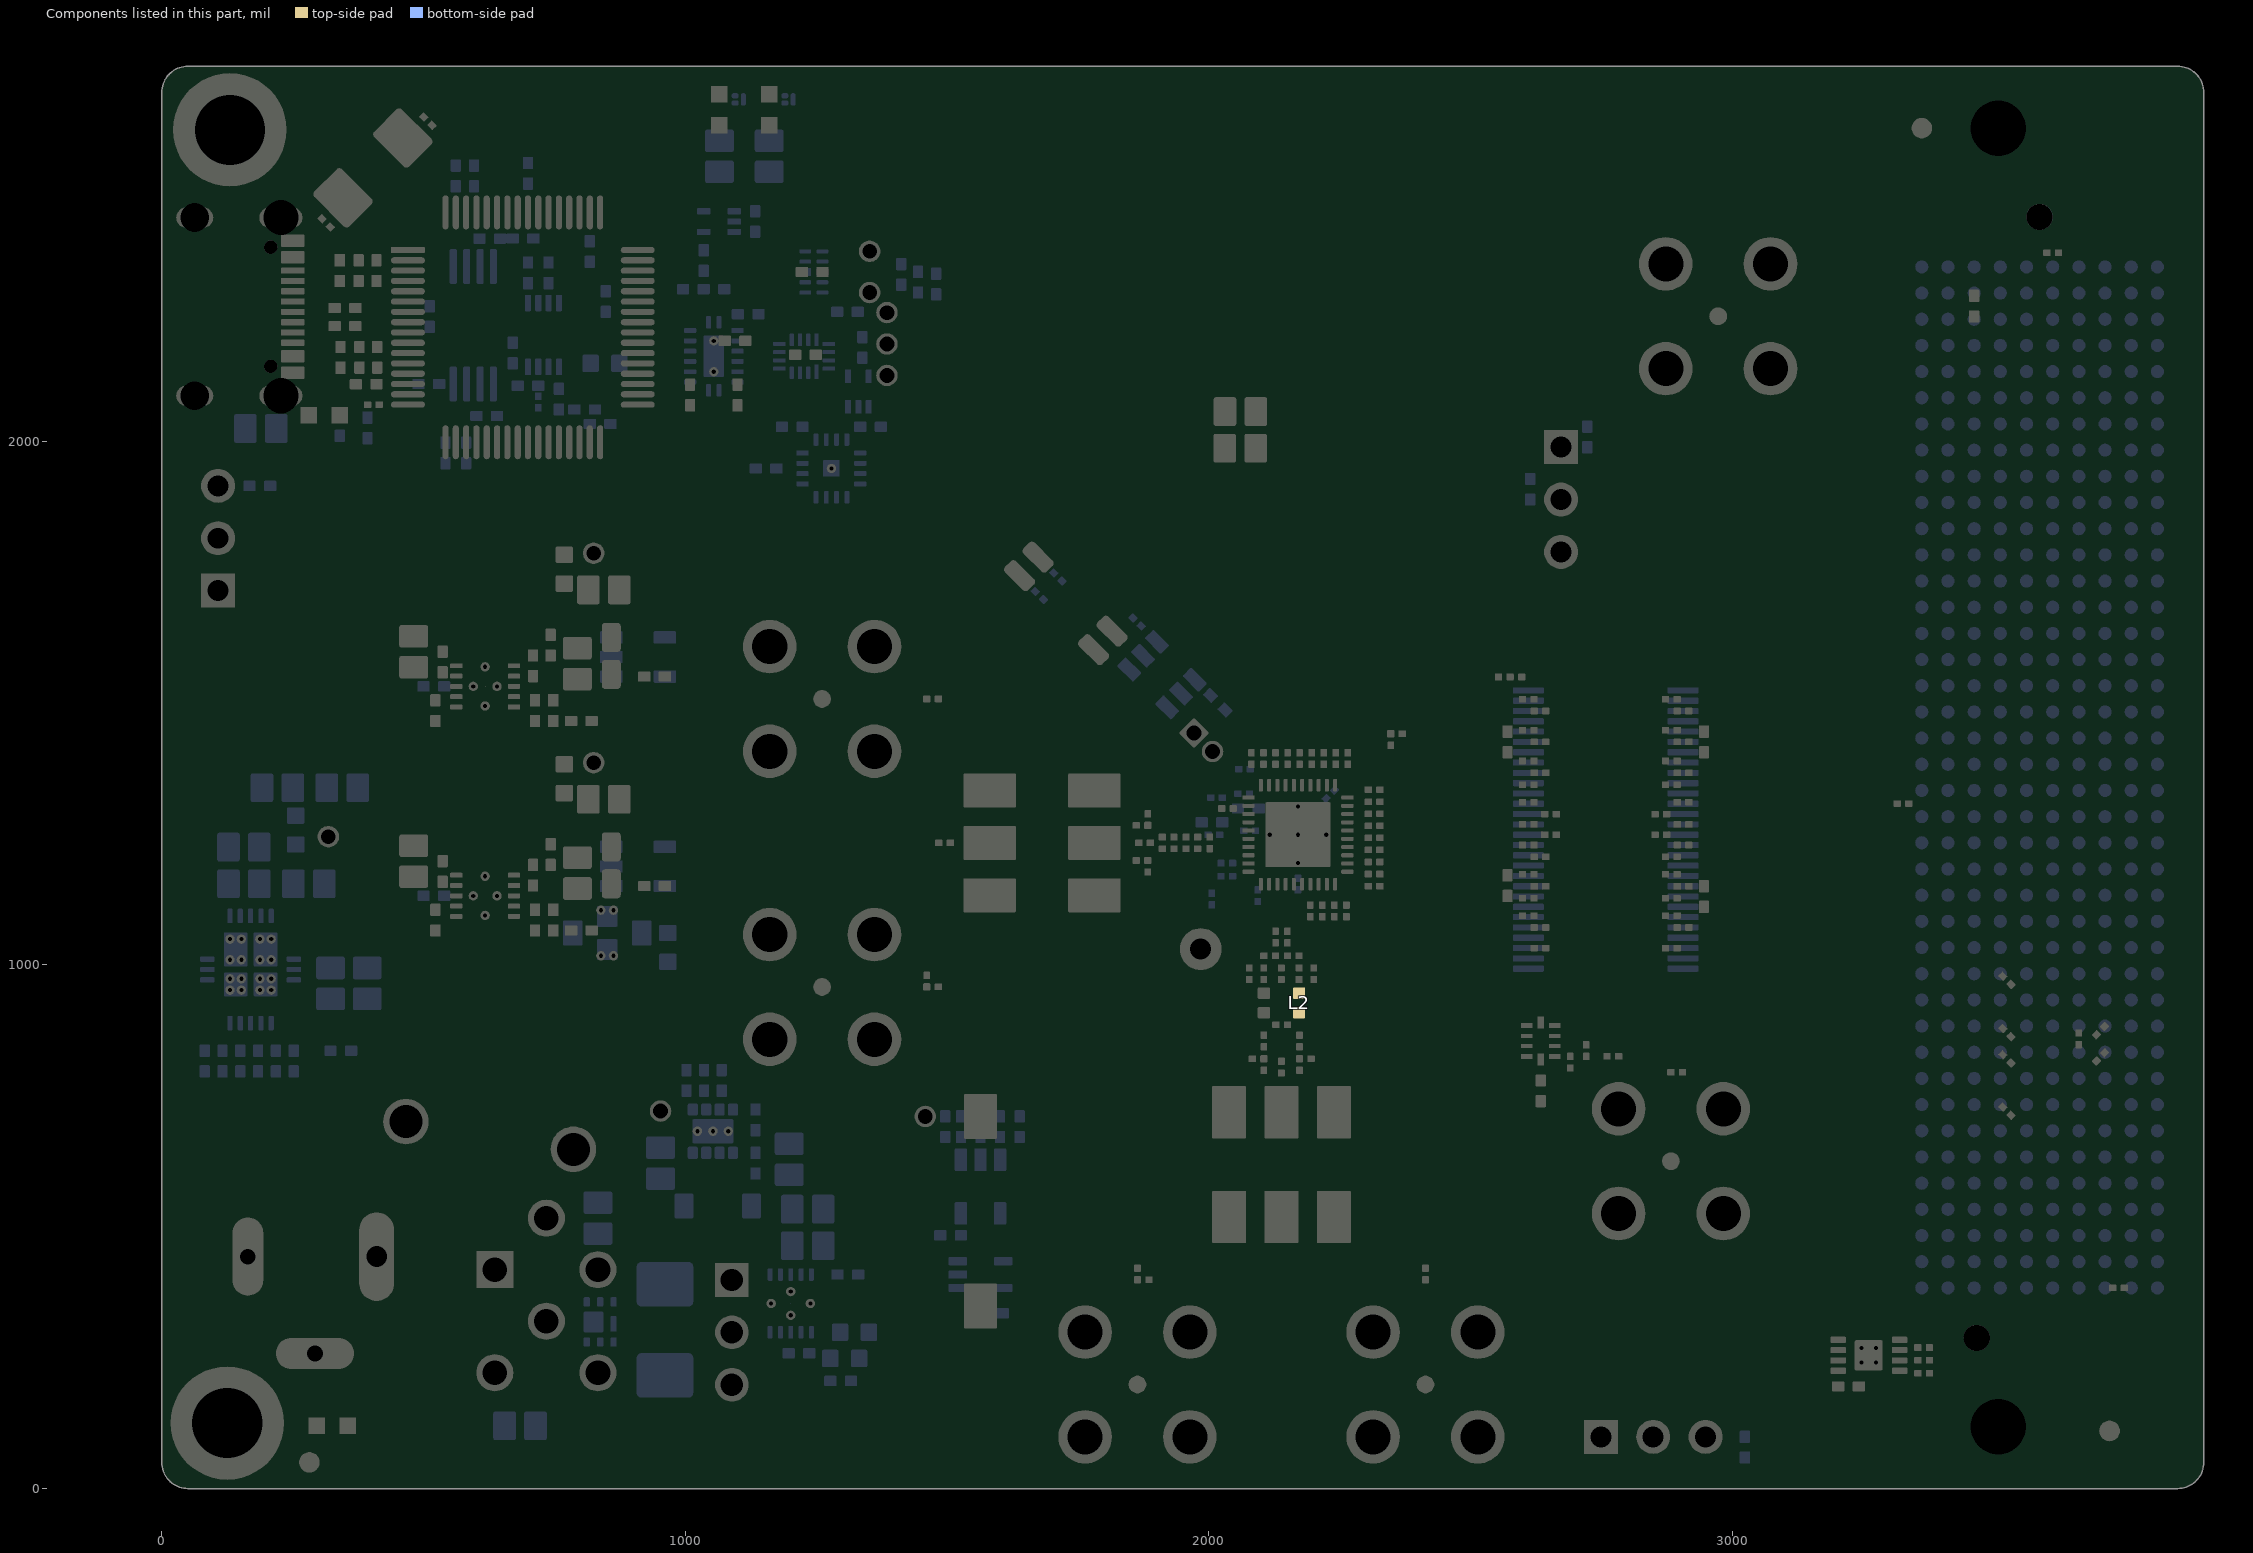
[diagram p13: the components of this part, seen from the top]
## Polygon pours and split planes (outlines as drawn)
1p8V_LVLSHIFT on L8 PWR "1" (solid, pour order 24): 1580,1639.12 1755,1639.12 1755,2415 1405,2415 1405,1640 1580,1640
VADJ on L8 PWR "L8 PWR-VADJ" (solid, remove dead copper, pour order 48): 3160.92,2015 3160.92,253.29 3635,253.29 3635,2715 1389.6,2715 1389.6,2015
3p3V_Utility on L8 PWR "L8 PWR-3p3V_Utility" (solid, remove dead copper, pour order 85): 155,760 265,760 265,1015 595,1015 595,605.64 1290,605.64 1290,416.86 786.24,416.86 786.24,-5 3320,-5 3320,100 1035,100 1035,248.29 3145,248.29 3145,2015 1389.6,2015 1389.6,2545 1390,2545 1390,2716.54 1265,2716.54 1265,2622.3 155,2622.3
GND on L8 PWR "L2 GND-GND" (solid, remove dead copper, pour order 100): 3900,-3.61 3900,2716.53 556.54,2716.54 ccw(c556.53,2660.06) 536.65,2712.92 56.54,2712.92 ccw(c56.53,2656.39) 0,2656.39 0,46.39 ccw(c50,46.39) 50,-3.61
2p3V on L8 PWR "vcm" (solid, remove dead copper, pour order 55): 170,1140 560,1140 560,1422.72 496.81,1422.72 496.81,1505.28 570,1505.28 570,1705 170,1705
1p8V_BUFVCC on L8 PWR "1" (solid, pour order 27): 965,1115 965,845 2385,845 2385,980 3145,980 3145,1665 2235,1665 2235,1375 980,1375 980,1115
12V_FMC on L8 PWR "gnd" (solid, remove dead copper, pour order 81): 3635,660 3791.17,660 3791.17,105 997.3,105 997.3,253.29 2785,253.29 3635,253.29
12V on L8 PWR "L8 PWR-12V" (solid, remove dead copper, pour order 34): 0,-5 275,-5 275.6,-5 790,-5 790,416.86 1290,416.86 1290,605.64 595,605.64 595,1015 275.6,1015 275.6,745 140,745 140,2635 1257.39,2635 1257.39,2715 0,2715
VCORE on L8 PWR "L10 PWR-VCORE" (solid, remove dead copper, pour order 69): 948.98,2112.51 948.98,2470 637.92,2470 637.92,2479.2 470,2479.2 470,2126.19 637.92,2126.19 637.92,2410 876.5,2410 876.5,2192.06 845,2192.06 845,2112.51
GND on L5 SIG "L2 GND-GND" (solid, remove dead copper, pour order 101): 3900,-3.61 3900,2716.53 556.54,2716.54 ccw(c556.53,2660.06) 536.65,2712.92 56.54,2712.92 ccw(c56.53,2656.39) 0,2656.39 0,46.39 ccw(c50,46.39) 50,-3.61
GND on L5 SIG "gnd" (solid, remove dead copper, pour order 54): 1895,1450 1895,1235 2130,1235 2130,1450
VREF on L5 SIG "gnd" (solid, remove dead copper, pour order 39): 1978.88,1424.46 1978.88,1285 2085.6,1285 2085.6,1424.46
VCM on L5 SIG "L5 SIG-VCM" (solid, remove dead copper, pour order 42): 1885,945 2202.05,945 2202.05,1213.05 1885,1213.05
EXTGND on L5 SIG "NONET_L-01_P-001" (solid, remove dead copper, pour order 38): 688.31,766.34 0,766.34 0,50 ccw(c50,50) 50,0 688.31,0
GND on L2 GND "L2 GND-GND" (solid, remove dead copper, pour order 71): 3900,-3.61 3900,2716.53 556.54,2716.54 ccw(c556.53,2660.06) 536.65,2712.92 56.54,2712.92 ccw(c56.53,2656.39) 0,2656.39 0,46.39 ccw(c50,46.39) 50,-3.61
EXTGND on L2 GND "NONET_L-01_P-001" (solid, remove dead copper, pour order 7): 688.31,766.34 0,766.34 0,50 ccw(c50,50) 50,0 688.31,0
GND on Top Layer "L2 GND-GND" (solid, remove dead copper, pour order 88): 3900,-3.61 3900,2716.53 556.54,2716.54 ccw(c556.53,2660.06) 536.65,2712.92 56.54,2712.92 ccw(c56.53,2656.39) 0,2656.39 0,46.39 ccw(c50,46.39) 50,-3.61
EXTGND on Top Layer "NONET_L-01_P-001" (solid, remove dead copper, pour order 58): 688.31,766.34 0,766.34 0,50 ccw(c50,50) 50,0 688.31,0
GND on L6 GND "L2 GND-GND" (solid, remove dead copper, pour order 76): 3900,-3.61 3900,2716.53 556.54,2716.54 ccw(c556.53,2660.06) 536.65,2712.92 56.54,2712.92 ccw(c56.53,2656.39) 0,2656.39 0,46.39 ccw(c50,46.39) 50,-3.61
EXTGND on L6 GND "NONET_L-01_P-001" (solid, remove dead copper, pour order 57): 688.31,766.34 0,766.34 0,50 ccw(c50,50) 50,0 688.31,0
GND on L4 GND "L2 GND-GND" (solid, remove dead copper, pour order 74): 3900,-3.61 3900,2716.53 556.54,2716.54 ccw(c556.53,2660.06) 536.65,2712.92 56.54,2712.92 ccw(c56.53,2656.39) 0,2656.39 0,46.39 ccw(c50,46.39) 50,-3.61
EXTGND on L4 GND "NONET_L-01_P-001" (solid, remove dead copper, pour order 59): 688.31,766.34 0,766.34 0,50 ccw(c50,50) 50,0 688.31,0
GND on L7 GND "L2 GND-GND" (solid, remove dead copper, pour order 77): 3900,-3.61 3900,2716.53 556.54,2716.54 ccw(c556.53,2660.06) 536.65,2712.92 56.54,2712.92 ccw(c56.53,2656.39) 0,2656.39 0,46.39 ccw(c50,46.39) 50,-3.61
EXTGND on L7 GND "NONET_L-01_P-001" (solid, remove dead copper, pour order 60): 688.31,766.34 0,766.34 0,50 ccw(c50,50) 50,0 688.31,0
GND on L9 GND "L2 GND-GND" (solid, remove dead copper, pour order 78): 3900,-3.61 3900,2716.53 556.54,2716.54 ccw(c556.53,2660.06) 536.65,2712.92 56.54,2712.92 ccw(c56.53,2656.39) 0,2656.39 0,46.39 ccw(c50,46.39) 50,-3.61
GND on L9 GND "L2 GND-GND" (solid, remove dead copper, pour order 90): 3900,-3.61 3900,2716.53 556.54,2716.54 ccw(c556.53,2660.06) 536.65,2712.92 56.54,2712.92 ccw(c56.53,2656.39) 0,2656.39 0,46.39 ccw(c50,46.39) 50,-3.61
EXTGND on L9 GND "NONET_L-01_P-001" (solid, remove dead copper, pour order 61): 688.31,766.34 0,766.34 0,50 ccw(c50,50) 50,0 688.31,0
1p8V_LVLSHIFT on L3 PWR "L3 PWR-1p8V_LVLSHIFT" (solid, pour order 93): 2636.58,697.88 3106.62,697.88 3106.62,2712.92 0,2712.92 0,887.5 1224.31,887.5 1224.31,0 1659.39,0 1659.39,1188.15 1366.99,1188.15 709.12,1191.1 269.17,1191.1 269.17,2033.32 2636.58,2033.32
GND on L3 PWR "L2 GND-GND" (solid, remove dead copper, pour order 99): 3900,-3.61 3900,2716.53 556.54,2716.54 ccw(c556.53,2660.06) 536.65,2712.92 56.54,2712.92 ccw(c56.53,2656.39) 0,2656.39 0,46.39 ccw(c50,46.39) 50,-3.61
1p8V_AVDD on L3 PWR "L3 PWR-1p8V_AVDD" (solid, remove dead copper, pour order 95): 2018.18,936.33 2018.64,879.73 2333.72,879.73 2333.72,936.33 2198.25,936.33 2198.25,1785 385,1785 385,1435 2018.64,1435 2018.64,936.33
3p3V_EEPROM on L3 PWR "vcm" (solid, remove dead copper, pour order 97): 3270,340 2875,340 2875,0 3270,0 3270,100
3p3V_AUX on L3 PWR "vcm" (solid, remove dead copper, pour order 96): 3270,340 3270,0 3900,0 3900,820 3575,820 3575,340
1p8V_IOVDD on L3 PWR "L3_PWR_1P8V_IOVDD_P098" (solid, remove dead copper, pour order 98): 385,1205.06 1741.07,1205.06 1741.07,376.16 2621.28,376.16 2621.28,1419.71 2227.79,1419.71 2227.79,819.66 1994.38,819.66 1994.38,1381.33 385,1381.33
EXTGND on L3 PWR "NONET_L-01_P-001" (solid, remove dead copper, pour order 94): 688.31,766.34 0,766.34 0,50 ccw(c50,50) 50,0 688.31,0
GND on Bottom Layer "L2 GND-GND" (solid, remove dead copper, pour order 92): 3900,-3.61 3900,2716.53 556.54,2716.54 ccw(c556.53,2660.06) 536.65,2712.92 56.54,2712.92 ccw(c56.53,2656.39) 0,2656.39 0,46.39 ccw(c50,46.39) 50,-3.61

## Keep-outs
Keep-Out Layer:
  text ".Layer_Name" at 577,-858.49 h60

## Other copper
Top Layer:
  drawing of 67 lines, arcs and shapes, not listed
  text ".Layer_Name" at 577,-858.49 h60
L2 GND:
  pour cut-out: 2907.99,625.2 ccw(c2882.27,625.27) 2900.45,643.45 ccw(c2882.93,625.93) 2882.93,650.72 2881.55,650.72 ccw(c2881.55,625.98) 2864.06,643.47 2863.35,642.76 ccw(c2880.85,625.27) 2856.11,625.27 2856.11,624.57 ccw(c2881.56,624.57) 2863.56,606.57 2863.7,606.43 ccw(c2882.05,624.77) 2882.05,598.83 ccw(c2882.05,624.75) 2900.38,606.42 2900.75,606.79 ccw(c2883.27,624.27) 2907.99,624.27
  pour cut-out: 2998.18,2238.8 ccw(c2972.46,2238.88) 2990.65,2257.06 ccw(c2973.12,2239.54) 2973.12,2264.32 2971.75,2264.32 ccw(c2971.75,2239.59) 2954.26,2257.08 2953.55,2256.37 ccw(c2971.04,2238.88) 2946.3,2238.88 2946.3,2238.17 ccw(c2971.76,2238.17) 2953.76,2220.17 2953.9,2220.03 ccw(c2972.24,2238.38) 2972.24,2212.44 ccw(c2972.24,2238.36) 2990.58,2220.03 2990.94,2220.4 ccw(c2973.47,2237.87) 2998.18,2237.87
  pour cut-out: 2387.73,198.79 ccw(c2413.44,198.72) 2395.26,180.53 ccw(c2412.79,198.06) 2412.79,173.27 2414.16,173.27 ccw(c2414.16,198) 2431.65,180.52 2432.36,181.23 ccw(c2414.86,198.72) 2439.61,198.72 2439.61,199.42 ccw(c2414.15,199.42) 2432.15,217.42 2432.01,217.56 ccw(c2413.67,199.22) 2413.67,225.16 ccw(c2413.67,199.23) 2395.33,217.57 2394.97,217.2 ccw(c2412.44,199.72) 2387.73,199.72
  pour cut-out: 1837.73,198.79 ccw(c1863.44,198.72) 1845.26,180.53 ccw(c1862.79,198.06) 1862.79,173.27 1864.16,173.27 ccw(c1864.16,198) 1881.65,180.52 1882.36,181.23 ccw(c1864.86,198.72) 1889.61,198.72 1889.61,199.42 ccw(c1864.15,199.42) 1882.15,217.42 1882.01,217.56 ccw(c1863.67,199.22) 1863.67,225.16 ccw(c1863.67,199.23) 1845.33,217.57 1844.97,217.2 ccw(c1862.44,199.72) 1837.73,199.72
  pour cut-out: 1261.18,983.77 ccw(c1261.11,958.05) 1242.92,976.24 ccw(c1260.45,958.71) 1235.66,958.71 1235.66,957.33 ccw(c1260.39,957.33) 1242.9,939.85 1243.61,939.14 ccw(c1261.11,956.63) 1261.11,931.89 1261.81,931.89 ccw(c1261.81,957.35) 1279.81,939.35 1279.95,939.49 ccw(c1261.61,957.83) 1287.55,957.83 ccw(c1261.62,957.83) 1279.95,976.16 1279.59,976.53 ccw(c1262.11,959.05) 1262.11,983.77
  pour cut-out: 1261.18,1533.77 ccw(c1261.11,1508.05) 1242.92,1526.24 ccw(c1260.45,1508.71) 1235.66,1508.71 1235.66,1507.33 ccw(c1260.39,1507.33) 1242.9,1489.85 1243.61,1489.14 ccw(c1261.11,1506.63) 1261.11,1481.89 1261.81,1481.89 ccw(c1261.81,1507.35) 1279.81,1489.35 1279.95,1489.49 ccw(c1261.61,1507.83) 1287.55,1507.83 ccw(c1261.62,1507.83) 1279.95,1526.16 1279.59,1526.53 ccw(c1262.11,1509.05) 1262.11,1533.77
  pour cut-out: 2200.95,663.72 2200.95,773.72 2275.95,773.72 2275.95,663.72
  pour cut-out: 2000.95,663.72 2000.95,773.72 2075.95,773.72 2075.95,663.72
  pour cut-out: 2000.95,463.72 2000.95,573.72 2075.95,573.72 2075.95,463.72
  pour cut-out: 1726.11,1295.55 1836.11,1295.55 1836.11,1370.55 1726.11,1370.55
  pour cut-out: 1726.11,1095.55 1836.11,1095.55 1836.11,1170.55 1726.11,1170.55
  pour cut-out: 1526.11,1095.55 1636.11,1095.55 1636.11,1170.55 1526.11,1170.55
  text ".Layer_Name" at 575,-860 h60
L3 PWR:
  pour cut-out: 2907.99,625.2 ccw(c2882.27,625.27) 2900.45,643.45 ccw(c2882.93,625.93) 2882.93,650.72 2881.55,650.72 ccw(c2881.55,625.98) 2864.06,643.47 2863.35,642.76 ccw(c2880.85,625.27) 2856.11,625.27 2856.11,624.57 ccw(c2881.56,624.57) 2863.56,606.57 2863.7,606.43 ccw(c2882.05,624.77) 2882.05,598.83 ccw(c2882.05,624.75) 2900.38,606.42 2900.75,606.79 ccw(c2883.27,624.27) 2907.99,624.27
  pour cut-out: 2998.18,2238.8 ccw(c2972.46,2238.88) 2990.65,2257.06 ccw(c2973.12,2239.54) 2973.12,2264.32 2971.75,2264.32 ccw(c2971.75,2239.59) 2954.26,2257.08 2953.55,2256.37 ccw(c2971.04,2238.88) 2946.3,2238.88 2946.3,2238.17 ccw(c2971.76,2238.17) 2953.76,2220.17 2953.9,2220.03 ccw(c2972.24,2238.38) 2972.24,2212.44 ccw(c2972.24,2238.36) 2990.58,2220.03 2990.94,2220.4 ccw(c2973.47,2237.87) 2998.18,2237.87
  pour cut-out: 921.46,1139.75 cw(c921.46,1150.75) 910.46,1150.75 cw(c921.46,1150.75) 921.46,1161.75 cw(c921.46,1150.75) 932.46,1150.75 cw(c921.46,1150.75)
  pour cut-out: 3761.42,822.27 cw(c3761.42,833.27) 3750.42,833.27 cw(c3761.42,833.27) 3761.42,844.27 cw(c3761.42,833.27) 3772.42,833.27 cw(c3761.42,833.27)
  pour cut-out: 3561.42,722.27 cw(c3561.42,733.27) 3550.42,733.27 cw(c3561.42,733.27) 3561.42,744.27 cw(c3561.42,733.27) 3572.42,733.27 cw(c3561.42,733.27)
  pour cut-out: 3560.12,570.57 cw(c3560.12,581.57) 3549.12,581.57 cw(c3560.12,581.57) 3560.12,592.57 cw(c3560.12,581.57) 3571.12,581.57 cw(c3560.12,581.57)
  pour cut-out: 3561.42,422.27 cw(c3561.42,433.27) 3550.42,433.27 cw(c3561.42,433.27) 3561.42,444.27 cw(c3561.42,433.27) 3572.42,433.27 cw(c3561.42,433.27)
  pour cut-out: 2383.73,356.91 cw(c2383.73,367.91) 2372.73,367.91 cw(c2383.73,367.91) 2383.73,378.91 cw(c2383.73,367.91) 2394.73,367.91 cw(c2383.73,367.91)
  pour cut-out: 2443.17,362.52 cw(c2443.17,373.52) 2432.17,373.52 cw(c2443.17,373.52) 2443.17,384.52 cw(c2443.17,373.52) 2454.17,373.52 cw(c2443.17,373.52)
  pour cut-out: 1978.88,358 cw(c1978.88,369) 1967.88,369 cw(c1978.88,369) 1978.88,380 cw(c1978.88,369) 1989.88,369 cw(c1978.88,369)
  pour cut-out: 1920.88,358 cw(c1920.88,369) 1909.88,369 cw(c1920.88,369) 1920.88,380 cw(c1920.88,369) 1931.88,369 cw(c1920.88,369)
  pour cut-out: 1893.17,362.52 cw(c1893.17,373.52) 1882.17,373.52 cw(c1893.17,373.52) 1893.17,384.52 cw(c1893.17,373.52) 1904.17,373.52 cw(c1893.17,373.52)
  pour cut-out: 1833.73,356.91 cw(c1833.73,367.91) 1822.73,367.91 cw(c1833.73,367.91) 1833.73,378.91 cw(c1833.73,367.91) 1844.73,367.91 cw(c1833.73,367.91)
  pour cut-out: 1824.06,1413.46 cw(c1824.06,1424.46) 1813.06,1424.46 cw(c1824.06,1424.46) 1824.06,1435.46 cw(c1824.06,1424.46) 1835.06,1424.46 cw(c1824.06,1424.46)
  pour cut-out: 2063.68,1013.29 cw(c2063.68,1024.29) 2052.68,1024.29 cw(c2063.68,1024.29) 2063.68,1035.29 cw(c2063.68,1024.29) 2074.68,1024.29 cw(c2063.68,1024.29)
  pour cut-out: 2387.73,198.79 ccw(c2413.44,198.72) 2395.26,180.53 ccw(c2412.79,198.06) 2412.79,173.27 2414.16,173.27 ccw(c2414.16,198) 2431.65,180.52 2432.36,181.23 ccw(c2414.86,198.72) 2439.61,198.72 2439.61,199.42 ccw(c2414.15,199.42) 2432.15,217.42 2432.01,217.56 ccw(c2413.67,199.22) 2413.67,225.16 ccw(c2413.67,199.23) 2395.33,217.57 2394.97,217.2 ccw(c2412.44,199.72) 2387.73,199.72
  pour cut-out: 1837.73,198.79 ccw(c1863.44,198.72) 1845.26,180.53 ccw(c1862.79,198.06) 1862.79,173.27 1864.16,173.27 ccw(c1864.16,198) 1881.65,180.52 1882.36,181.23 ccw(c1864.86,198.72) 1889.61,198.72 1889.61,199.42 ccw(c1864.15,199.42) 1882.15,217.42 1882.01,217.56 ccw(c1863.67,199.22) 1863.67,225.16 ccw(c1863.67,199.23) 1845.33,217.57 1844.97,217.2 ccw(c1862.44,199.72) 1837.73,199.72
  pour cut-out: 1261.18,983.77 ccw(c1261.11,958.05) 1242.92,976.24 ccw(c1260.45,958.71) 1235.66,958.71 1235.66,957.33 ccw(c1260.39,957.33) 1242.9,939.85 1243.61,939.14 ccw(c1261.11,956.63) 1261.11,931.89 1261.81,931.89 ccw(c1261.81,957.35) 1279.81,939.35 1279.95,939.49 ccw(c1261.61,957.83) 1287.55,957.83 ccw(c1261.62,957.83) 1279.95,976.16 1279.59,976.53 ccw(c1262.11,959.05) 1262.11,983.77
  pour cut-out: 1261.18,1533.77 ccw(c1261.11,1508.05) 1242.92,1526.24 ccw(c1260.45,1508.71) 1235.66,1508.71 1235.66,1507.33 ccw(c1260.39,1507.33) 1242.9,1489.85 1243.61,1489.14 ccw(c1261.11,1506.63) 1261.11,1481.89 1261.81,1481.89 ccw(c1261.81,1507.35) 1279.81,1489.35 1279.95,1489.49 ccw(c1261.61,1507.83) 1287.55,1507.83 ccw(c1261.62,1507.83) 1279.95,1526.16 1279.59,1526.53 ccw(c1262.11,1509.05) 1262.11,1533.77
  pour cut-out: 2200.95,663.72 2200.95,773.72 2275.95,773.72 2275.95,663.72
  pour cut-out: 2000.95,663.72 2000.95,773.72 2075.95,773.72 2075.95,663.72
  pour cut-out: 2000.95,463.72 2000.95,573.72 2075.95,573.72 2075.95,463.72
  pour cut-out: 1726.11,1295.55 1836.11,1295.55 1836.11,1370.55 1726.11,1370.55
  pour cut-out: 1726.11,1095.55 1836.11,1095.55 1836.11,1170.55 1726.11,1170.55
  pour cut-out: 1526.11,1095.55 1636.11,1095.55 1636.11,1170.55 1526.11,1170.55
  text ".Layer_Name" at 575,-860 h60
L4 GND:
  text ".Layer_Name" at 575,-860 h60
L7 GND:
  text ".Layer_Name" at 575,-860 h60
L8 PWR:
  pour cut-out: 3220.57,234.09 cw(c3220.57,245.09) 3209.57,245.09 cw(c3220.57,245.09) 3220.57,256.09 cw(c3220.57,245.09) 3231.57,245.09 cw(c3220.57,245.09)
  pour cut-out: 3246.08,229.6 cw(c3246.08,240.6) 3235.08,240.6 cw(c3246.08,240.6) 3246.08,251.6 cw(c3246.08,240.6) 3257.08,240.6 cw(c3246.08,240.6)
  pour cut-out: 3381.1,258.36 cw(c3381.1,269.36) 3370.1,269.36 cw(c3381.1,269.36) 3381.1,280.36 cw(c3381.1,269.36) 3392.1,269.36 cw(c3381.1,269.36)
  pour cut-out: 3381.1,233.68 cw(c3381.1,244.68) 3370.1,244.68 cw(c3381.1,244.68) 3381.1,255.68 cw(c3381.1,244.68) 3392.1,244.68 cw(c3381.1,244.68)
  text ".Layer_Name" at 575,-860 h60
L9 GND:
  text ".Layer_Name" at 575,-860 h60
L5 SIG:
  pour cut-out: 2093.53,1198.32 cw(c2093.53,1209.32) 2082.53,1209.32 cw(c2093.53,1209.32) 2093.53,1220.32 cw(c2093.53,1209.32) 2104.53,1209.32 cw(c2093.53,1209.32)
  pour cut-out: 2170.02,1183.75 cw(c2170.02,1194.75) 2159.02,1194.75 cw(c2170.02,1194.75) 2170.02,1205.75 cw(c2170.02,1194.75) 2181.02,1194.75 cw(c2170.02,1194.75)
  pour cut-out: 2138.52,923.68 cw(c2138.52,934.68) 2127.52,934.68 cw(c2138.52,934.68) 2138.52,945.68 cw(c2138.52,934.68) 2149.52,934.68 cw(c2138.52,934.68)
  pour cut-out: 2114.9,1125.2 cw(c2114.9,1136.2) 2103.9,1136.2 cw(c2114.9,1136.2) 2114.9,1147.2 cw(c2114.9,1136.2) 2125.9,1136.2 cw(c2114.9,1136.2)
  pour cut-out: 2177.89,1161.2 cw(c2177.89,1172.2) 2166.89,1172.2 cw(c2177.89,1172.2) 2177.89,1183.2 cw(c2177.89,1172.2) 2188.89,1172.2 cw(c2177.89,1172.2)
  pour cut-out: 2162.14,1125.2 cw(c2162.14,1136.2) 2151.14,1136.2 cw(c2162.14,1136.2) 2162.14,1147.2 cw(c2162.14,1136.2) 2173.14,1136.2 cw(c2162.14,1136.2)
  text ".Layer_Name" at 575,-860 h60
L6 GND:
  text ".Layer_Name" at 575,-860 h60
Bottom Layer:
  region net GND: 1358.66,1933.73 ccw(c1358.66,1938.23) 1363.17,1938.23 1363.17,1958.63 ccw(c1358.94,1958.63) 1358.94,1962.86 1324.07,1962.86 ccw(c1324.07,1961) 1322.21,1961 1322.21,1935.65 ccw(c1324.13,1935.65) 1324.13,1933.73 1326.09,1933.73
  region net 3p3V_Utility: 1199.13,1962.86 ccw(c1199.13,1958.36) 1194.62,1958.36 1194.62,1937.96 ccw(c1198.85,1937.96) 1198.85,1933.73 1233.72,1933.73 ccw(c1233.72,1935.59) 1235.58,1935.59 1235.58,1960.93 ccw(c1233.66,1960.93) 1233.66,1962.86 1231.7,1962.86
  region net GND: 1059.37,2237.86 cw(c1060.67,2237.86) 1060.67,2239.16 1066.77,2239.16 1066.77,2239.28 1107.06,2239.28 cw(c1107.06,2235.01) 1111.34,2235.01 1111.34,2208.52 cw(c1109.9,2208.52) 1109.9,2207.08 1090.08,2207.08 1090.08,2207 1070.2,2207 cw(c1070.2,2217.83) 1059.37,2217.83
  region net 1p8V_BUFVCC: 1023.43,1037.43 ccw(c1023.43,1044.73) 1030.73,1044.73 1030.73,1079.23 ccw(c1025.3,1079.23) 1025.3,1084.67 900.29,1084.67 ccw(c900.29,1082.16) 897.78,1082.16 897.78,1039.27 ccw(c899.62,1039.27) 899.62,1037.43 929.59,1037.43 931.49,1037.43
  region net 1p8V_LVLSHIFT: 801.22,1037.43 ccw(c801.22,1039.5) 803.29,1039.5 803.29,1111.35 cw(c813.86,1111.35) 813.86,1121.91 ccw(c813.86,1129.14) 821.09,1129.14 821.09,1165.8 ccw(c817.44,1165.8) 817.44,1169.45 774.38,1169.45 ccw(c774.38,1160.96) 765.89,1160.96 765.89,1039.69 ccw(c768.16,1039.69) 768.16,1037.43
  region net NetJ3_A4,B4: 225,2165 ccw(c240,2165) 240,2150 265,2150 ccw(c265,2160) 275,2160 275,2355 ccw(c265,2355) 265,2365 240.09,2365 ccw(c240,2350) 225,2350 225,2320 cw(c205,2320) 205,2300 140,2300 ccw(c140,2280) 120,2280 120,2020 ccw(c145,2020) 145,1995 180,1995 ccw(c180,2000) 185,2000 185,2055 ccw(c180,2055) 180,2060 cw(c180,2070) 170,2070 170,2165 cw(c180,2165) 180,2175 215,2175 cw(c215,2165)
  region net 3p3V_Utility: 1053.66,2073.3 1064.09,2073.3 ccw(c1064.09,2078.02) 1068.82,2078.02 1068.82,2104.88 1068.82,2107.09 ccw(c1066.69,2107.24) 1066.83,2109.36 1030.72,2109.36 ccw(c1030.72,2098.63) 1019.99,2098.63 1019.99,2096.93 ccw(c1028.57,2096.93) 1028.57,2088.35 cw(c1028.57,2083.37) 1033.55,2083.37 ccw(c1043.62,2083.37) 1043.62,2073.3 1044.15,2073.3 ccw(c1044.15,2097.97) 1046.76,2073.44 1046.61,2073.3
  region net DC-DC_PG: 242.05,824.31 242.05,870.61 ccw(c237.5,870.61) 237.5,875.16 231.59,875.16 cw(c231.59,877.12) 229.62,877.12 229.62,909.61 cw(c231.59,909.61) 231.59,911.57 264.07,911.57 cw(c264.07,909.8) 265.84,909.8 265.84,903.7 266.04,903.7 266.04,828.62 cw(c261.73,828.62) 261.73,824.31
  region net 2p3V: 294.81,1210.12 cw(c294.81,1214.32) 290.61,1214.32 290.61,1249.02 ccw(c270.2,1249.02) 270.2,1269.44 238.85,1269.44 cw(c238.85,1279.62) 228.67,1279.62 228.67,1420.85 cw(c235.57,1420.85) 235.57,1427.76 327.39,1427.76 cw(c327.39,1418.21) 336.94,1418.21 336.94,1281.99 ccw(c345.07,1281.99) 345.07,1273.85 cw(c345.07,1266.38) 352.54,1266.38 352.54,1217.59 cw(c345.07,1217.59) 345.07,1210.12
  region net GND: 38.05,863.68 38.05,968.87 cw(c45.17,968.87) 45.17,976 98.72,976.54 ccw(c98.72,986.95) 109.13,986.95 109.13,997.24 ccw(c99.52,996.45) 98.72,1006.06 45.17,1006.06 cw(c44.84,1012.86) 38.05,1012.53 38.26,1115.78 cw(c47.89,1115.78) 47.89,1125.41 103.58,1125.41 ccw(c103.58,1127.44) 105.61,1127.44 105.61,1182.56 148.91,1182.56 148.91,1123.39 ccw(c152.85,1123.39) 152.85,1119.46 cw(c152.85,1117.49) 154.82,1117.49 154.82,1074.55 ccw(c158.26,1074.55) 158.26,1071.11 cw(c158.26,1065.7) 163.68,1065.7 163.68,997.8 ccw(c176.56,998.24) 175.49,985.39 218.73,985.39 cw(c218.73,983.36) 220.76,983.36 220.76,884.02 cw(c211.91,884.01) 211.91,875.16 206,875.16 cw(c206,877.12) 204.03,877.13 204.03,909.64 ccw(c199.05,909.64) 199.05,914.62 114.55,914.62 ccw(c114.55,909.61) 109.54,909.61 109.54,887.21 cw(c86.02,887.2) 86.01,863.68
  region net GND: 240.5,966.69 275.71,966.69 ccw(c275.71,970.29) 279.3,970.29 cw(c281.61,970.29) 281.61,972.6 419.82,972.6 419.82,1015.85 283.36,1015.85 cw(c263.68,1015.9) 263.68,996.22 240.42,996.22 ccw(c240.42,994.29) 238.48,994.29 238.48,971.09 238.48,968.57 ccw(c240.35,968.57) 240.35,966.7
  region net 12V: 238.48,955.68 cw(c239.65,955.68) 239.65,956.85 419.82,956.85 419.82,913.54 294.7,913.54 ccw(c280.92,913.54) 280.92,927.32 240.43,927.32 cw(c240.25,929.09) 238.48,928.91
  region net NetC11_2: 164.66,1213.92 164.66,1252.86 cw(c170.05,1252.86) 170.05,1258.25 267.23,1258.25 cw(c267.23,1252.56) 272.93,1252.56 272.93,1014.92 cw(c264.07,1014.92) 264.07,1006.06 240.45,1006.06 227.58,1006.06 ccw(c227.58,999.24) 220.76,999.24 cw(c218.73,999.24) 218.73,997.2 177.53,997.2 cw(c177.53,999.24) 175.49,999.24 175.49,1070.83 ccw(c166.43,1070.83) 166.63,1079.88 cw(c166.63,1081.88) 166.55,1079.88 ccw(c166.55,1079.78) 166.53,1079.88 cw(c166.63,1081.85) 164.66,1081.85 164.66,1213.87 cw(c174.84,1213.87)
  pour cut-out: 109.54,877.13 109.54,909.61 cw(c114.55,909.61) 114.55,914.62 199.05,914.62 cw(c199.05,909.64) 204.03,909.64 204.03,877.13
  region net 12V: 1085.37,563.37 cw(c1085.37,544.99) 1103.76,544.99 1103.76,522.42 ccw(c1110.83,522.42) 1110.83,515.35 1137.61,515.35 cw(c1137.61,495.83) 1157.12,495.83 1157.12,400 ccw(c1160.29,400) 1160.29,396.83 1203.8,396.83 ccw(c1203.8,398.96) 1205.94,398.97 1205.94,426.28 cw(c1215.74,426.28) 1215.74,436.08 1225.69,436.08 1225.69,616.62 ccw(c1221.29,616.62) 1221.29,621.02 1175.14,621.02 ccw(c1175.14,607.73) 1175.08,621.02 1087.64,621.02 cw(c1087.64,633.52) 1075.13,633.52 1075.13,648.1 ccw(c1070.28,648.1) 1070.28,652.96 1060.06,652.96 ccw(c1060.06,648.35) 1055.45,648.35 1055.45,567 ccw(c1059.07,567) 1059.07,563.37
  region net NetF1_1: 679.61,584.11 680.09,584.03 825.56,584.03 ccw(c825.56,617.33) 858.86,617.33 858.86,707.08 ccw(c852.59,707.08) 852.59,713.36 577.66,713.36 ccw(c577.66,693) 557.31,693 557.31,585.32 cw(c517.94,585.32) 517.94,545.95 389.99,545.95 ccw(c389.99,516.43) 360.46,516.43 360.46,378.63 ccw(c409.67,378.63) 409.67,329.42 618.33,329.42 ccw(c618.33,382.57) 671.48,382.57 671.48,571.54 cw(c685.26,571.54)
  region net EXTGND: 101.33,287.03 ccw(c124.78,287.03) 124.78,263.57 182.11,263.57 cw(c182.11,238.64) 207.04,238.64 ccw(c229.51,238.64) 229.51,216.17 531.41,216.17 cw(c531.41,188.72) 558.86,188.72 ccw(c573.91,188.72) 573.91,173.67 669.83,173.67 ccw(c669.83,189.11) 685.26,189.11 685.26,287.03 633.15,287.03 cw(c633.15,296.61) 633.1,287.03 685.26,287.03 ccw(c659.66,284.13) 656.76,309.73 350.62,309.73 cw(c350.62,319.58) 340.77,319.58 340.77,496.72 340.87,496.74 340.87,530.41 340.87,547.77 cw(c410.43,547.78) 410.43,617.33 491.45,617.33 ccw(c491.45,662.2) 536.33,662.2 536.33,740.36 ccw(c493.33,740.36) 493.33,783.36 391.33,783.36 ccw(c391.32,678.36) 286.38,681.78 286.33,681.8 cw(c143.89,681.79) 144.13,539.36 113.59,539.36 ccw(c113.59,527.1) 101.33,527.1
  region net NetR1_2: 1208.88,248.56 1208.88,268.25 cw(c1208.88,271.24) 1205.89,271.24 1205.89,307.98 1205.94,307.98 1205.94,308.31 ccw(c1204.03,308.31) 1204.03,310.21 1159.38,310.21 1129.39,310.21 cw(c1129.39,318.62) 1120.99,318.62 ccw(c1109.11,318.62) 1109.11,330.49 1062.92,330.49 ccw(c1062.92,324.33) 1056.76,324.33 1056.76,256.47 ccw(c1064.67,256.47) 1064.67,248.56 1185.4,248.56
  region net GND: 858.86,270.91 878.85,270.91 ccw(c878.85,278.48) 886.42,278.48 886.42,315.7 ccw(c872.93,315.7) 872.93,329.18 857.49,329.18 857.49,328.61 856.92,328.61 856.92,272.86 ccw(c858.86,272.86)
  region net NetC1_2: 695.1,299.89 ccw(c724.63,299.89) 724.63,270.36 cw(c724.63,231) 764,230.99 764,211.31 ccw(c793.5,211.31) 764.08,209.13 ccw(c767.36,208.4) 764,208.4 ccw(c798.74,208.4) 798.74,173.67 1005.49,173.67 996.33,188.72 996.32,255.77 850.23,255.77 cw(c850.93,263.53) 843.14,263.53 843.14,362.9 ccw(c840.64,362.91) 840.64,365.4 787.07,365.4 cw(c787.07,378.63) 773.85,378.63 773.85,506.59 cw(c793.53,506.59) 774.03,509.31 774.03,508.51 cw(c789.84,508.51) 774.07,509.54 cw(c793.53,506.59) 779.95,520.84 cw(c789.84,508.51) 789.84,524.31 805.34,524.31 805.34,524.3 860.46,524.3 ccw(c860.46,526.27) 862.43,526.27 862.43,536.11 862.43,561.2 862.43,564.87 ccw(c859.69,564.87) 859.69,567.61 701.51,567.61 ccw(c701.51,561.2) 695.1,561.2
  region net NetC5_2: 1311.06,281.67 1311.06,315.14 1268.26,315.14 ccw(c1268.26,313.4) 1266.53,313.4 cw(c1263.34,313.4) 1263.34,310.21 1237.85,310.21 ccw(c1237.85,308.23) 1235.86,308.23 1235.86,288.58 ccw(c1237.85,288.58) 1237.85,286.59 1264.6,286.59 cw(c1264.6,284.62) 1266.57,284.62 ccw(c1269.52,284.62) 1269.52,281.67 1279.56,281.67
  region net NetC4_2: 1216.2,281.52 ccw(c1217.68,281.52) 1217.68,280.04 cw(c1217.68,278.79) 1218.93,278.79 1218.93,251.79 ccw(c1222.16,251.79) 1221.52,248.62 1221.52,248.56 1235.02,248.56 cw(c1235.02,232.36) 1251.22,232.36 1251.22,210.14 ccw(c1265.58,210.14) 1265.58,195.78 1288.75,195.78 1288.75,228.14 cw(c1292.28,228.14) 1292.28,231.67 1292.28,265.14 1251.3,265.14 cw(c1251.3,268.18) 1248.25,268.18 1245.58,268.18 cw(c1245.58,288.17) 1225.58,288.17 1225.58,308.49 ccw(c1223.88,308.49) 1223.88,310.21 1217.89,310.21 ccw(c1217.89,308.52) 1216.2,308.52 1216.2,289.12 1216.18,289.12 1216.18,288.01 ccw(c1217.47,288.01) 1216.2,287.78
  region net 3p3V_Utility: 1009.61,629.34 1020.57,629.34 ccw(c1020.57,632.67) 1023.91,632.67 1023.91,650.05 ccw(c1020.91,650.05) 1020.91,652.96 1008.74,652.96 cw(c1008.74,660.8) 1000.91,660.8 1000.91,705.19 cw(c1007.76,705.19) 1007.76,712.04 1020.08,712.04 ccw(c1020.08,715.91) 1023.95,715.91 1023.95,731.69 ccw(c1020,731.69) 1020,735.64 1007.66,735.64 1007.66,735.6 981.49,735.6 cw(c981.49,744.6) 972.5,744.6 ccw(c968.34,744.6) 968.34,748.75 932.5,748.75 ccw(c932.5,741.19) 924.94,741.19 924.94,632.96 ccw(c928.49,632.96) 928.49,629.41 1017.11,629.41
  region net NetC1_1: 793.53,382.57 ccw(c797.47,382.57) 797.47,378.63 847.74,378.63 cw(c847.74,369.45) 856.92,369.45 856.92,351.27 ccw(c860.5,351.27) 860.5,347.69 1015.01,347.69 1030.73,347.69 ccw(c1030.73,356.54) 1039.59,356.54 cw(c1049.53,356.54) 1049.53,366.48 1120.99,366.48 1120.99,466.92 ccw(c1101.01,466.92) 1101.01,486.9 921.48,486.9 cw(c921.48,496.74) 911.64,496.74 ccw(c899.83,496.74) 899.83,508.55 805.34,508.55 ccw(c805.34,496.74) 793.53,496.74
  region net 3p3V_Utility: 532.01,1988.54 ccw(c534.67,1988.54) 534.67,1985.88 603.73,1985.88 ccw(c603.73,1994.84) 612.68,1994.84 612.68,2056.34 ccw(c610.86,2056.34) 610.86,2058.16 540.49,2058.16 ccw(c540.55,2049.62) 532.01,2049.77 532.01,1999.41
  region net 3p3V_Utility: 519.77,2097.73 531.52,2097.73 cw(c531.52,2079.52) 549.72,2079.52 ccw(c553.17,2079.52) 553.17,2076.08 560.06,2076.08 ccw(c560.06,2079.52) 563.5,2079.52 563.5,2139.56 ccw(c560.06,2139.56) 560.06,2143.01 553.17,2143.01 ccw(c553.17,2139.56) 549.72,2139.56 cw(c531.52,2139.56) 531.52,2121.35 519.77,2121.35
  region net GND: 638.66,2076.08 ccw(c638.66,2089.5) 652.09,2089.5 652.09,2129.23 ccw(c638.31,2129.23) 638.31,2143.01 629.94,2143.01 ccw(c629.94,2139.56) 626.5,2139.56 626.5,2079.52 ccw(c629.94,2079.52) 629.94,2076.08
  pour cut-out: 3335,1135 3350.49,1150.49 3350.49,1839.53 3325.19,1839.53 3330.09,1834.63 3330.09,1142.28
  pour cut-out: 2952.51,1170.06 2934.8,1187.76 2934.8,1526.06 2953.81,1526.06 2957.51,1522.36 2952.51,1517.36
  pour cut-out: 581 vertices and 0 holes, not listed, extent 2860.51,896.63 3689.35,1410.91
  pour cut-out: 339 vertices and 0 holes, not listed, extent 2860.51,871.6 3739.35,1510.91
  pour cut-out: 350 vertices and 0 holes, not listed, extent 2860.51,805.06 3754.21,1310.91
  pour cut-out: 241 vertices and 0 holes, not listed, extent 2822.2,1205.14 3539.35,2110.91
  pour cut-out: 264 vertices and 0 holes, not listed, extent 2633.31,840.66 3489.35,2225.71
  pour cut-out: 301 vertices and 0 holes, not listed, extent 1349.3,1058.29 2217.54,2281.67
  region net GND: 2070.42,1331.53 2070.42,1320.62 2083.01,1320.62 2083.01,1278.94 2106.64,1278.94 2106.64,1333.22 2070.56,1333.22 2070.56,1332.54
  pour cut-out: 81.91,1006.06 81.91,1006.07 86.89,1006.06 86.9,1006.06 100.61,1006.03 104.19,1004.88 107.07,1002.45 108.79,999.1 109.13,997.24 109.13,986.95 108.93,984.92 107.38,981.17 104.5,978.29 100.75,976.74 98.72,976.54 81.91,976.53 81.91,976.55 73.2,976.57 69.62,977.71 66.74,980.15 65.02,983.5 64.68,985.36 64.68,995.64 64.88,997.68 66.43,1001.43 69.31,1004.3 73.06,1005.86 75.09,1006.06
  text ".Layer_Name" at 577,-858.49 h60
Multi-Layer:
  pour cut-out: 1334.01,1842.77 cw(c1334.01,1853.77) 1323.01,1853.77 cw(c1334.01,1853.77) 1334.01,1864.77 cw(c1334.01,1853.77) 1345.01,1853.77 cw(c1334.01,1853.77)
  pour cut-out: 1244.37,1882.18 cw(c1244.37,1893.18) 1233.37,1893.18 cw(c1244.37,1893.18) 1244.37,1904.18 cw(c1244.37,1893.18) 1255.37,1893.18 cw(c1244.37,1893.18)

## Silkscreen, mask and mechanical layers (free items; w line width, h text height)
Top Overlay:
  drawing of 207 lines, arcs and shapes, not listed
  text "POWER / GOOD" at 1239.25,2560 h90
  text "ADC354xEVM / RevG" at 1910.05,2401.48 h60
  text "DUT / SPI" at 1641.44,2105 h70 r90
  text "DUT OPTION" at 2000.04,2091.93 h100
  text "ADC3544" at 2135.04,2031.93 h50
  text "CTRL" at 997.24,1992.43 h60
  text "ADC3543" at 2135.04,1961.93 h50
  text "HIGH" at 997.23,1950.17 h60
  text "LOW" at 1129.73,1950.17 h60
  text "REF" at 1258.89,1950.47 h60
  text "CLK" at 1378.89,1950.47 h60
  text "ON" at 1032.39,1911.47 h30
  text "OFF" at 1157.39,1911.47 h30
  text "EXT" at 1287.39,1911.47 h30
  text "DIFF" at 1397.39,1911.47 h30
  text "ON" at 1032.39,1851.47 h30
  text "ON" at 1157.39,1851.47 h30
  text "INT" at 1287.39,1851.47 h30
  text "DIFF" at 1397.39,1851.47 h30
  text "OFF" at 1032.39,1795.67 h30
  text "ON" at 1157.39,1795.67 h30
  text "INT" at 1287.39,1795.67 h30
  text "SE" at 1397.39,1795.67 h30
  text ".Layer_Name" at 577,-858.49 h60
Bottom Overlay:
  lines w7: 1289.04,2304.12 1304.04,2289.12 ; 1289.04,2379.12 1289.04,2369.12 1304.04,2354.12 1304.04,2289.12 ; 1319.04,2304.12 1304.04,2289.12 ; 1419,2258.63 1464,2258.63
  text ".Layer_Name" at 577,-858.49 h60
Top Paste:
  text ".Layer_Name" at 577,-858.49 h60
Bottom Paste:
  text ".Layer_Name" at 577,-858.49 h60
Top Solder:
  text ".Layer_Name" at 577,-858.49 h60
  text ".Layer_Name" at 577,-858.49 h60
Bottom Solder:
  text ".Layer_Name" at 577,-858.49 h60
Drill Guide:
  text ".Layer_Name" at 577,-858.49 h60
M1 Board Outline:
  lines w5: 0,50 ccw(c50,50) 50,0 100,0 3850,0 ccw(c3850,50) 3900,50 3900,100 3900,2616.53 3900,2666.54 ccw(c3850,2666.54) 3850,2716.54 100,2716.54 50,2716.54 ccw(c50,2666.54) 0,2666.54 0,2616.53 0,100 0,50
  text ".Layer_Name" at 577,-858.49 h60
M2 Board Dimensions:
  rectangle: 125,-400 500,-275
  rectangle: 0,-275 125,-150
  lines w7: 0,-275 1000,-275 ; 125,-400 125,-150 ; 250,-400 250,-150 ; 500,-400 500,-150 ; 750,-400 750,-150 ; 0,-400 0,-150 1000,-150 1000,-400 0,-400
  text ".Layer_Name" at 577,-858.49 h60
M3 3D STEP Top:
  text ".Layer_Name" at 577,-858.49 h60
M4 3D STEP Bottom:
  text ".Layer_Name" at 577,-858.49 h60
M5 Assembly Top:
  lines w10: -292,-930.17 6308,-930.17 ; -292,-726.83 6310,-726.83 ; -292,-523.5 -292,-1133.5 3713,-1133.5 6310,-1133.5 6310,-523.5 -291.5,-523.5 -291.5,-1133.5 1284,-1133.5 ; 2173,-1133.5 2173,-523.5 ; 3440,-726.83 3440,-523.5 ; 4280,-726.83 4280,-523.5 ; 4902,-1140 4902,-937.17
  text "COMPONENTS MARKED 'DNP' SHOULD NOT BE POPULATED." at 1153.5,-318.5 h60
  text "ASSEMBLY VARIANT:" at 1153,-434 h60
  text ".VariantName" at 2189,-434 h60
  text "PCB VIEWED FROM TOP SIDE" at -228.5,-655.67 h60
  text "BOARD #:" at 2248,-655.67 h60
  text ".PRJ_Number" at 2793.5,-655.67 h60
  text "REV:" at 3638,-655.67 h60
  text ".PCB_Rev" at 3929.5,-655.67 h60
  text "SVN REV:" at 4476,-655.67 h60
  text ".VersionControl_RevNumber" at 4982,-655.67 h60
  text "PLOT NAME =" at -228.5,-1064.34 h60
  text ".plot_File_Name" at 577,-1064.34 h60
  text "GENERATED    :" at 2250,-1064.34 h60
  text ".Print_Date" at 3119.5,-1064.34 h60
  text ".Print_Time" at 3848.5,-1064.34 h60
  text "TEXAS INSTRUMENTS" at 5113,-1064.34 h60
M6 Assembly Bottom:
  lines w10: -292.5,-727.33 6309.5,-727.33 ; -290.5,-930.67 6309.5,-930.67 ; 1115.5,-1140.5 1115.5,-937.67 ; 1737.5,-727.33 1737.5,-524 ; 2577.5,-727.33 2577.5,-524 ; 3844.5,-1134 3844.5,-524 ; 4733.5,-1134 6309,-1134 6309,-524 -292.5,-524 -292.5,-1134 2304.5,-1134 6309.5,-1134 6309.5,-524
  text "COMPONENTS MARKED 'DNP' SHOULD NOT BE POPULATED." at 6102,-318 h60
  text ".VariantName" at 5058,-434 h60
  text "ASSEMBLY VARIANT:" at 6097,-434 h60
  text ".VersionControl_RevNumber" at 1035.5,-656.17 h60
  text "SVN REV:" at 1541.5,-656.17 h60
  text ".PCB_Rev" at 2088,-656.17 h60
  text "REV:" at 2379.5,-656.17 h60
  text ".PRJ_Number" at 3224,-656.17 h60
  text "BOARD #:" at 3769.5,-656.17 h60
  text "PCB VIEWED FROM BOTTOM SIDE" at 6246,-656.17 h60
  text "TEXAS INSTRUMENTS" at 904.5,-1064.84 h60
  text ".Print_Time" at 2169,-1064.84 h60
  text ".Print_Date" at 2898,-1064.84 h60
  text "GENERATED    :" at 3767.5,-1064.84 h60
  text ".plot_File_Name" at 5440.5,-1064.84 h60
  text "PLOT NAME =" at 6246,-1064.84 h60
M9 Title Sheet:
  drawing of 56 lines, arcs and shapes, not listed
  text "1" at 1058.34,13381.39 h70
  text "2" at 4384,13381.39 h70
  text "3" at 7714,13381.39 h70
  text "4" at 11049,13381.39 h70
  text "5" at 14374,13381.39 h70
  text "6" at 17709,13381.39 h70
  text "A" at -463,11603.39 h70
  text "A" at 19237,11603.39 h70
  text "B" at -463,7853.39 h70
  text "B" at 19237,7853.39 h70
  text "C" at -463,4103.39 h70
  text "C" at 19237,4103.39 h70
  text "D" at -463,353.39 h70
  text "D" at 19237,353.39 h70
  text "PROJECT TITLE:" at 16143,268.39 h45
  text ".PRJ_Title" at 16193,135.06 h70
  text "DESIGNED FOR:" at 16143,-32.61 h45
  text ".PRJ_Customer" at 16193,-172.61 h70
  text "FILE NAME:" at 16143,-332.61 h45
  text ".PCB_File_Name_No_Path" at 16193,-452.61 h70
  text "Texas Instruments (TI) and/or its licensors do not warrant the accuracy or completeness of this specification" at 11173.5,-614.45 h45
  text "ENGINEER:" at 16143,-622.61 h45
  text "LAYOUT BY:" at 17648,-622.61 h45
  text "or any information contained therein. TI and/or its licensors do not warrant that this design will meet" at 11128.51,-727.11 h45
  text ".PRJ_Engineer" at 16193,-777.6 h70
  text ".PCB_Layout" at 17698.5,-777.6 h70
  text "the specifications, will be suitable for your application or fit for any particular purpose, or will operate in" at 11128.51,-839.78 h45
  text ".Layer_Name" at 577,-858.49 h60
  text "ALTIUM DESIGNER VERSION:" at 17648,-932.61 h45
  text "an implementation. TI and/or its licensors do not warrant that the design is production worthy. You should" at 11128.51,-952.44 h45
  text "completely validate and test your design implementation to confirm the system functionality for your application." at 11173.5,-1065.11 h45
  text ".print_Scale" at 16193,-1065.94 h70
  text ".Application_BuildNumber" at 17698.5,-1065.94 h70
  text "1" at 1058.34,-1318.61 h70
  text "2" at 4384,-1318.61 h70
  text "3" at 7714,-1318.61 h70
  text "4" at 11049,-1318.61 h70
  text "5" at 14374,-1318.61 h70
  text "6" at 17709,-1318.61 h70
M10 Fab Notes:
  drawing of 213 lines, arcs and shapes, not listed
  text "M10 Fab Notes" at 16103.19,9538.99 h60
  text "DESIGN INFORMATION" at 17181.52,9421.87 h60
  text "MIN. TRACK WIDTH:" at 16536.96,9289.74 h60
  text "4" at 17633.2,9289.74 h60
  text "MIL" at 17787.96,9289.74 h60
  text "MIN. CLEARANCE:" at 16536.96,9165.62 h60
  text "MIL" at 17787.96,9165.62 h60
  text "5" at 17633.42,9163.98 h60
  text "MIN. VIA PAD SIZE:" at 16536.96,9041.49 h60
  text "18" at 17603.21,9041.49 h60
  text "MIL" at 17787.96,9041.49 h60
  text "0.05mm (2MIL)" at 17231.96,8911.59 h60
  text "MINIMUM ANNULAR RING" at 16207.73,8903.37 h60
  text "EXTERNAL" at 17939.96,8903.37 h60
  text "PER" at 16407.73,8793.24 h60
  text "IPC-D-275 CLASS 2 LEVEL C" at 16627.73,8793.24 h60
  text "MIL, HOLES" at 18115.96,8692.76 h60
  text "+/-" at 17723.5,8684.18 h60
  text "+/-" at 18577.5,8684.18 h60
  text "REGISTRATION TOLERANCES:" at 16207.73,8683.11 h60
  text "METAL" at 17407.5,8683.11 h60
  text "5" at 17983.7,8683.12 h60
  text "3" at 18816.7,8683.12 h60
  text "MIL" at 18932.96,8683.11 h60
  text "HOLE SIZE TOLERANCE (UNLESS OTHERWISE SPECIFIED):" at 16207.73,8584.8 h60
  text "+/-" at 18577.5,8581.92 h60
  text "3" at 18816.7,8580.86 h60
  text "MIL" at 18932.96,8580.86 h60
  text "MATERIAL:" at 16132.96,8443.21 h60
  text "UNIFORM STACKUP" at 17867.01,8348.29 h60
  text "HYBRID STACKUP" at 16841.48,8341.02 h60
  text "X" at 17720,8340 h60
  text "ISOLA FR408HR" at 16547.68,8177.37 h60
  text "X" at 16403.5,8170.36 h60
  text "Megtron 4    Isola I-Speed" at 16538.93,7976.12 h60
  text "OR" at 16988.92,7976.12 h60
  text "Megtron6    Isola MT-40    Nelco MW-1000" at 16538.93,7779.27 h60
  text "OR" at 16940.28,7779.27 h60
  text "OR" at 17639.01,7779.27 h60
  text "OTHER" at 16578.93,7582.42 h60
  text "X" at 16756.39,7385.94 h60
  text "62 MIL (1.6mm) +/-10%" at 16877.21,7384.84 h60
  text "92 MIL  +/-10%" at 18453.18,7384.84 h60
  text "THICKNESS:" at 16210.88,7376.62 h60
  text "OTHER" at 18162.11,7376.62 h60
  text "TOLERANCE:" at 16210.88,7238.3 h60
  text "X" at 17059.11,7238.3 h60
  text "ANSI IPC-6012 TYPE 3 CLASS 2" at 17237.12,7238.3 h60
  text "OTHER +/-" at 17237.11,7094.11 h60
  text "BOW & TWIST:" at 16210.88,6948.92 h60
  text "X" at 17059.11,6948.92 h60
  text "ANSI IPC-6012 TYPE 3 CLASS 2" at 17237.12,6948.92 h60
  text "OTHER +/-" at 17237.11,6802.23 h60
  text "DRILLING:" at 16136.11,6671.61 h60
  text "NC_DRILL FILES" at 17897.11,6566.42 h60
  text "REFERENCE:" at 16210.88,6562.48 h60
  text "X" at 16868.11,6562.39 h60
  text "AS SHOWN" at 17046.11,6562.48 h60
  text "X" at 17769.11,6562.48 h60
  text "OTHER" at 18195.11,6420.23 h60
  text "PTH COPPER THICKNESS:" at 16210.55,6416.7 h60
  text "X" at 17349.79,6416.7 h60
  text "20-30 um" at 17477.79,6416.7 h60
  text "BOARD FINISH:" at 16136.11,6269.1 h60
  text "SILKSCREEN:" at 16291.33,6158.98 h60
  text "X" at 17249.11,6158.98 h60
  text "TOP" at 17366.11,6158.98 h60
  text "X" at 17759.11,6158.98 h60
  text "BOTTOM" at 17877.11,6158.98 h60
  text "SILKSCREEN COLOR:" at 16291.33,6003.79 h60
  text "X" at 17249.11,6003.79 h60
  text "WHITE" at 17366.11,6003.79 h60
  text "OTHER" at 17877.11,6003.79 h60
  text "RED" at 18482.9,5866.47 h60
  text "X" at 17971.79,5863.76 h60
  text "GREEN" at 17497.11,5860.34 h60
  text "OTHER" at 18115.11,5860.34 h60
  text "SOLDER RESIST COLOR:" at 16291.33,5853.47 h60
  text "X" at 17379.11,5706.09 h60
  text "MATTE" at 17497.11,5706.09 h60
  text "SEMI-GLOSS" at 18114.65,5705.45 h60
  text "X" at 17009.34,5533.32 h60
  text "IMMERSION GOLD (ENIG)" at 17197.11,5533.32 h60
  text "ENEPIG" at 18534.65,5526.1 h60
  text "SURFACE FINISH:" at 16136.11,5525.1 h60
  text "IMM. TIN/SILVER OR EQUIV" at 16465.65,5387.78 h60
  text "HARD GOLD (30u)" at 17897.11,5383.84 h60
  text "OTHER" at 16490.65,5186.99 h60
  text "X" at 17025,5035 h60
  text "ARRAY/PANEL:" at 16136.11,5031.62 h60
  text "CUT AND TRIM PER M1 BOARD OUTLINE" at 17197.11,5023.39 h60
  text "N.C. ROUTE" at 17197.11,4887.43 h60
  text "V. SCORE" at 18063.11,4887.43 h60
  text "CERTIFICATION:" at 16136.11,4758.3 h60
  text "MATERIALS AND WORKMANSHIP FOR ALL PCBS" at 16861.11,4758.3 h60
  text "TO MEET OR EXCEED THE REQUIREMENTS OF:" at 16861.11,4664.24 h60
  text "X" at 16498.62,4535.61 h60
  text "ANSI IPC-A-600F CLASS ->" at 16626.61,4535.61 h60
  text "X" at 18274.62,4535.61 h60
  text "2" at 18384.61,4535.61 h60
  text "1" at 18069.61,4534.11 h60
  text "3" at 18738.61,4534.11 h60
  text "X" at 17310.62,4387.92 h60
  text "RoHS" at 17438.61,4387.92 h60
  text "OTHER" at 18083.01,4387.92 h60
  text "PER ORDER" at 18480.07,4387.92 h60
  text "ALL BOARDS MUST MEET OR EXCEED UL94-V0 REQUIREMENTS." at 16163.65,4234.1 h60
  text "PCB MUST BEAR THE UL94V-0 UL REGISTERED MATERIAL ID NUMBER" at 16163.65,4118.03 h60
  text "ADDITIONAL REQUIREMENTS:" at 16136.11,3948.61 h60
  text "MICROSECTION:" at 16210.88,3841.48 h60
  text "YES" at 17116.61,3841.48 h60
  text "REQUIRED" at 17978.11,3697.15 h60
  text "BARE BOARD ELEC. TEST:" at 16210.88,3694.29 h60
  text "NONE" at 17516.61,3694.29 h60
  text "X" at 17860.11,3694.29 h60
  text "PER ORDER" at 18570.11,3694.29 h60
  text "FAB INSTRUCTIONS" at 16207.95,3403.28 h100
  text "X" at 16255.41,3252.08 h60
  text "16 MIL & SMALLER VIAS REQUIRE NON-CONDUCTIVE FILL AND PLANARIZE" at 16362.95,3163.28 h59
  text "X" at 16250.41,3057.08 h60
  text "TOP LAYER TRACKS 9.7 MIL WIDE REQUIRE 50 OHM SINGLE-ENDED IMPEDANCE" at 16365.9,2952.65 h60
  text "OUTER LAYER TRACKS XX MIL WIDE WITH XX MIL SPACE REQUIRE 100 OHM DIFFERENTIAL IMPEDANCE" at 16365.9,2747.93 h60
  text "INNER LAYER XX & XX TRACKS XX MIL WIDE REQUIRE 50 OHM SINGLE-ENDED IMPEDANCE" at 16365.9,2543.21 h60
  text "INNER LAYER TRACKS XX MIL WIDE WITH   / XX MIL SPACE REQUIRE 100 OHM DIFFERENTIAL IMPEDANCE" at 16360,2349.31 h60
  text "NO PULL-BACK ON COPPER FEATURES TO EDGE OF THE BOARD" at 16357.04,2144.58 h60
  text ".Layer_Name" at 577,-858.49 h60
M11 Gerber Information:
  lines w10: -292,-930.17 6308,-930.17 ; -292,-726.83 6310,-726.83 ; -292,-523.5 -292,-1133.5 3713,-1133.5 6310,-1133.5 6310,-523.5 -291.5,-523.5 -291.5,-1133.5 1284,-1133.5 ; 2173,-1133.5 2173,-523.5 ; 3440,-726.83 3440,-523.5 ; 4280,-726.83 4280,-523.5 ; 4902,-1140 4902,-937.17
  text "ALL ARTWORK VIEWED FROM TOP SIDE" at -228.5,-655.67 h60
  text "BOARD #:" at 2248,-655.67 h60
  text ".PRJ_Number" at 2793.5,-655.67 h60
  text "REV:" at 3638,-655.67 h60
  text ".PCB_Rev" at 3929.5,-655.67 h60
  text "SVN REV:" at 4476,-655.67 h60
  text ".VersionControl_RevNumber" at 4982,-655.67 h60
  text "LAYER NAME =" at -228.5,-858.49 h60
  text "PLOT NAME =" at -228.5,-1064.34 h60
  text ".plot_File_Name" at 577,-1064.34 h60
  text "GENERATED    :" at 2250,-1064.34 h60
  text ".Print_Date" at 3119.5,-1064.34 h60
  text ".Print_Time" at 3848.5,-1064.34 h60
  text "TEXAS INSTRUMENTS" at 5113,-1064.34 h60
M12 Stackup:
  drawing of 607 lines, arcs and shapes, not listed
  text "Layer" at 9956.79,4031.7 h60
  text "Name" at 10366.7,4031.7 h60
  text "Material" at 11296.44,4031.7 h60
  text "Thickness" at 12156.21,4031.7 h60
  text "Constant" at 12806.04,4031.7 h60
  text "Board Layer Stack" at 13375.91,4031.7 h60
  text "Top Overlay" at 10366.7,3911.7 h60
  text "Top Solder" at 10366.7,3791.7 h60
  text "Solder Resist" at 11296.44,3791.7 h60
  text "0.40mil" at 12156.21,3791.7 h60
  text "3.5" at 12806.04,3791.7 h60
  text "1" at 9956.79,3671.7 h60
  text "Top Layer" at 10366.7,3671.7 h60
  text "1.40mil" at 12156.21,3671.7 h60
  text "Dielectric 1" at 10366.7,3551.7 h60
  text "FR408HR" at 11296.44,3551.7 h60
  text "5.00mil" at 12156.21,3551.7 h60
  text "3.62" at 12806.04,3551.7 h60
  text "2" at 9956.79,3431.7 h60
  text "L2 GND" at 10366.7,3431.7 h60
  text "CF-004" at 11296.44,3431.7 h60
  text "1.40mil" at 12156.21,3431.7 h60
  text "Dielectric 3" at 10366.7,3311.7 h60
  text "FR408HR" at 11296.44,3311.7 h60
  text "3.20mil" at 12156.21,3311.7 h60
  text "3.46" at 12806.04,3311.7 h60
  text "3" at 9956.79,3191.7 h60
  text "L3 PWR" at 10366.7,3191.7 h60
  text "CF-004" at 11296.44,3191.7 h60
  text "1.40mil" at 12156.21,3191.7 h60
  text "Dielectric 5" at 10366.7,3071.7 h60
  text "FR408HR" at 11296.44,3071.7 h60
  text "3.00mil" at 12156.21,3071.7 h60
  text "3.6" at 12806.04,3071.7 h60
  text "4" at 9956.79,2951.7 h60
  text "L4 GND" at 10366.7,2951.7 h60
  text "CF-004" at 11296.44,2951.7 h60
  text "1.40mil" at 12156.21,2951.7 h60
  text "Dielectric 7" at 10366.7,2831.7 h60
  text "FR408HR" at 11296.44,2831.7 h60
  text "9.20mil" at 12156.21,2831.7 h60
  text "3.68" at 12806.04,2831.7 h60
  text "5" at 9956.79,2711.7 h60
  text "L5 SIG" at 10366.7,2711.7 h60
  text "CF-004" at 11296.44,2711.7 h60
  text "1.40mil" at 12156.21,2711.7 h60
  text "Dielectric1" at 10366.7,2591.7 h60
  text "FR408HR" at 11296.44,2591.7 h60
  text "6.40mil" at 12156.21,2591.7 h60
  text "3.46" at 12806.04,2591.7 h60
  text "6" at 9956.79,2471.7 h60
  text "L6 GND" at 10366.7,2471.7 h60
  text "CF-004" at 11296.44,2471.7 h60
  text "1.40mil" at 12156.21,2471.7 h60
  text "Dielectric 8" at 10366.7,2351.7 h60
  text "FR408HR" at 11296.44,2351.7 h60
  text "9.20mil" at 12156.21,2351.7 h60
  text "3.68" at 12806.04,2351.7 h60
  text "7" at 9956.79,2231.7 h60
  text "L7 GND" at 10366.7,2231.7 h60
  text "CF-004" at 11296.44,2231.7 h60
  text "1.40mil" at 12156.21,2231.7 h60
  text "Dielectric 6" at 10366.7,2111.7 h60
  text "FR408HR" at 11296.44,2111.7 h60
  text "3.00mil" at 12156.21,2111.7 h60
  text "3.6" at 12806.04,2111.7 h60
  text "8" at 9956.79,1991.7 h60
  text "L8 PWR" at 10366.7,1991.7 h60
  text "CF-004" at 11296.44,1991.7 h60
  text "1.40mil" at 12156.21,1991.7 h60
  text "Dielectric 4" at 10366.7,1871.7 h60
  text "FR408HR" at 11296.44,1871.7 h60
  text "3.20mil" at 12156.21,1871.7 h60
  text "3.46" at 12806.04,1871.7 h60
  text "9" at 9956.79,1751.7 h60
  text "L9 GND" at 10366.7,1751.7 h60
  text "CF-004" at 11296.44,1751.7 h60
  text "1.40mil" at 12156.21,1751.7 h60
  text "Dielectric 2" at 10366.7,1631.7 h60
  text "FR408HR" at 11296.44,1631.7 h60
  text "5.00mil" at 12156.21,1631.7 h60
  text "3.62" at 12806.04,1631.7 h60
  text "10" at 9956.79,1511.7 h60
  text "Bottom Layer" at 10366.7,1511.7 h60
  text "1.40mil" at 12156.21,1511.7 h60
  text "Bottom Solder" at 10366.7,1391.7 h60
  text "Solder Resist" at 11296.44,1391.7 h60
  text "0.40mil" at 12156.21,1391.7 h60
  text "3.5" at 12806.04,1391.7 h60
  text "Bottom Overlay" at 10366.7,1271.7 h60
  text "Total board thickness:" at 9956.79,1151.7 h60
  text "62.00mil" at 12156.21,1151.7 h60
  text ".Layer_Name" at 577,-858.49 h60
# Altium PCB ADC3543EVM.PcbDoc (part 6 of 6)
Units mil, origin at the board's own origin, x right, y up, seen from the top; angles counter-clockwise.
Board outline 3900 x 2716.54 mil, 10 copper layers (Top Layer, L2 GND, L3 PWR, L4 GND, L5 SIG, L6 GND, L7 GND, L8 PWR, L9 GND, Bottom Layer), stack 61.2 mil thick; 352 components, 249 nets, 1505 pads, 904 vias.

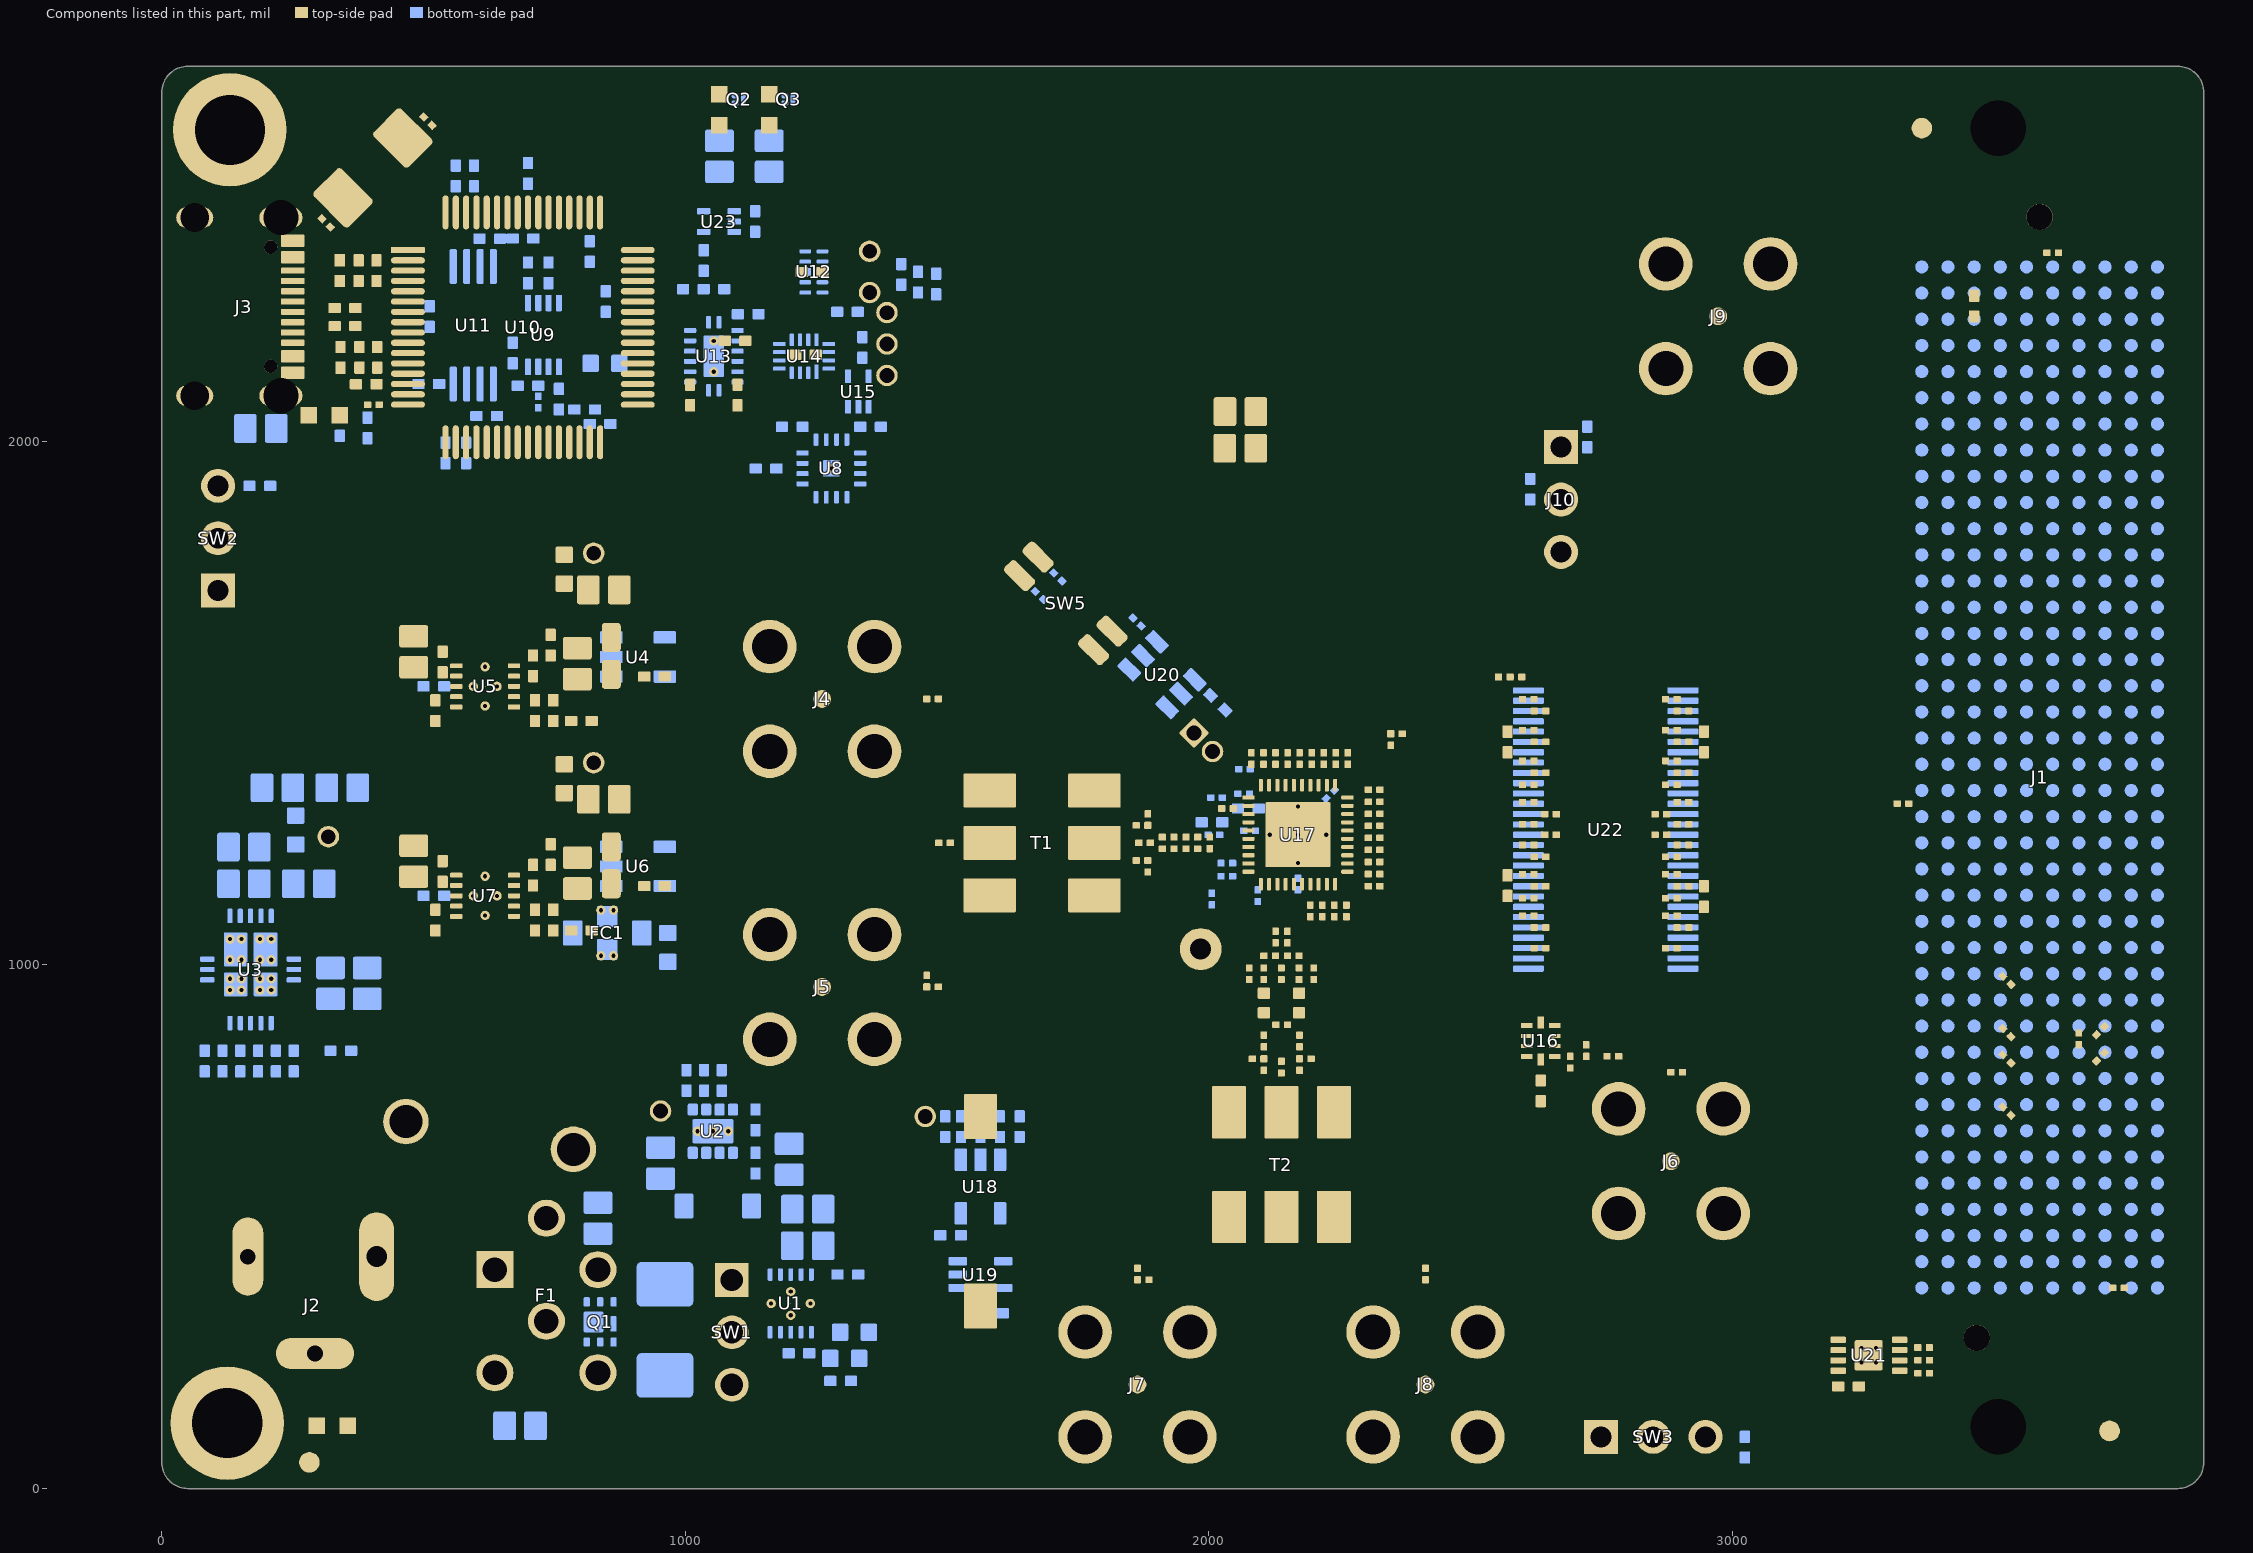
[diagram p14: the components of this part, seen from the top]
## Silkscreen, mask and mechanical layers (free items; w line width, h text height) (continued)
Drill Drawing:
  drawing of 165 lines, arcs and shapes, not listed
  text "Symbol" at 111.04,5465 h48
  text "Count" at 458.95,5465 h48
  text "Hole Size" at 898.84,5465 h48
  text "Plated" at 1671.95,5465 h48
  text "Hole Type" at 2019.86,5465 h48
  text "Drill Layer Pair" at 2519.73,5465 h48
  text "Via/Pad" at 3526.1,5465 h48
  text "Pad Shape" at 3930,5465 h48
  text "Template" at 4663.12,5465 h48
  text "Description" at 5816.11,5465 h48
  text "Hole Tolerance (+)" at 6395.95,5465 h48
  text "Hole Tolerance (-)" at 7295.69,5465 h48
  text "1" at 458.95,5365 h40
  text "39.76mil (1.010mm)" at 898.84,5365 h40
  text "PTH" at 1671.95,5365 h40
  text "Slot" at 2019.86,5365 h40
  text "Top Layer - Bottom Layer" at 2519.73,5365 h40
  text "Pad" at 3526.1,5365 h40
  text "Rounded" at 3930,5365 h40
  text "r430_170h101_356r85" at 4663.12,5365 h40
  text "2" at 458.95,5265 h40
  text "25.59mil (0.650mm)" at 898.84,5265 h40
  text "NPTH" at 1671.95,5265 h40
  text "Round" at 2019.86,5265 h40
  text "Top Layer - Bottom Layer" at 2519.73,5265 h40
  text "Pad" at 3526.1,5265 h40
  text "Rounded" at 3930,5265 h40
  text "c65hn65m65p0" at 4663.12,5265 h40
  text "A" at 89.35,5255.01 h44.44
  text "2" at 458.95,5165 h40
  text "29.92mil (0.760mm)" at 898.84,5165 h40
  text "PTH" at 1671.95,5165 h40
  text "Slot" at 2019.86,5165 h40
  text "Top Layer - Bottom Layer" at 2519.73,5165 h40
  text "Pad" at 3526.1,5165 h40
  text "Rounded" at 3930,5165 h40
  text "r380_150h76_305r75" at 4663.12,5165 h40
  text "2" at 458.95,5065 h40
  text "50.00mil (1.270mm)" at 898.84,5065 h40
  text "NPTH" at 1671.95,5065 h40
  text "Round" at 2019.86,5065 h40
  text "Top Layer - Bottom Layer" at 2519.73,5065 h40
  text "Pad" at 3526.1,5065 h40
  text "Rounded" at 3930,5065 h40
  text "c127hn127" at 4663.12,5065 h40
  text "2" at 458.95,4965 h40
  text "55.12mil (1.400mm)" at 898.84,4965 h40
  text "PTH" at 1671.95,4965 h40
  text "Slot" at 2019.86,4965 h40
  text "Top Layer - Bottom Layer" at 2519.73,4965 h40
  text "Pad" at 3526.1,4965 h40
  text "Rounded Rectangle" at 3930,4965 h40
  text "r100_180h140_60r50m100_180p0" at 4663.12,4965 h40
  text "C" at 89.35,4955.01 h44.44
  text "2" at 458.95,4865 h40
  text "63.00mil (1.600mm)" at 898.84,4865 h40
  text "PTH" at 1671.95,4865 h40
  text "Round" at 2019.86,4865 h40
  text "Top Layer - Bottom Layer" at 2519.73,4865 h40
  text "Pad" at 3526.1,4865 h40
  text "Rounded" at 3930,4865 h40
  text "c221h160" at 4663.12,4865 h40
  text "2" at 458.95,4765 h40
  text "66.93mil (1.700mm)" at 898.84,4765 h40
  text "PTH" at 1671.95,4765 h40
  text "Slot" at 2019.86,4765 h40
  text "Top Layer - Bottom Layer" at 2519.73,4765 h40
  text "Pad" at 3526.1,4765 h40
  text "Rounded Rectangle" at 3930,4765 h40
  text "r100_210h170_60r50m100_210p0" at 4663.12,4765 h40
  text "B" at 89.35,4755.01 h44.44
  text "2" at 458.95,4665 h40
  text "105.91mil (2.690mm)" at 898.84,4665 h40
  text "NPTH" at 1671.95,4665 h40
  text "Round" at 2019.86,4665 h40
  text "Top Layer - Bottom Layer" at 2519.73,4665 h40
  text "Pad" at 3526.1,4665 h40
  text "Rounded" at 3930,4665 h40
  text "c-127hn269" at 4663.12,4665 h40
  text "2" at 458.95,4565 h40
  text "133.86mil (3.400mm)" at 898.84,4565 h40
  text "PTH" at 1671.95,4565 h40
  text "Round" at 2019.86,4565 h40
  text "Top Layer - Bottom Layer" at 2519.73,4565 h40
  text "Pad" at 3526.1,4565 h40
  text "Rounded" at 3930,4565 h40
  text "c550h340m550p0" at 4663.12,4565 h40
  text "3" at 458.95,4465 h40
  text "42.91mil (1.090mm)" at 898.84,4465 h40
  text "PTH" at 1671.95,4465 h40
  text "Round" at 2019.86,4465 h40
  text "Top Layer - Bottom Layer" at 2519.73,4465 h40
  text "Pad" at 3526.1,4465 h40
  text "(Mixed)" at 3930,4465 h40
  text "(Mixed)" at 4663.12,4465 h40
  text "6" at 458.95,4365 h40
  text "47.24mil (1.200mm)" at 898.84,4365 h40
  text "PTH" at 1671.95,4365 h40
  text "Round" at 2019.86,4365 h40
  text "Top Layer - Bottom Layer" at 2519.73,4365 h40
  text "Pad" at 3526.1,4365 h40
  text "(Mixed)" at 3930,4365 h40
  text "(Mixed)" at 4663.12,4365 h40
  text "9" at 458.95,4265 h40
  text "20.00mil (0.508mm)" at 898.84,4265 h40
  text "PTH" at 1671.95,4265 h40
  text "Round" at 2019.86,4265 h40
  text "Top Layer - Bottom Layer" at 2519.73,4265 h40
  text "Via" at 3526.1,4265 h40
  text "Rounded" at 3930,4265 h40
  text "v102h51m0mx0" at 4663.12,4265 h40
  text "10" at 458.95,4165 h40
  text "40.00mil (1.016mm)" at 898.84,4165 h40
  text "PTH" at 1671.95,4165 h40
  text "Round" at 2019.86,4165 h40
  text "Top Layer - Bottom Layer" at 2519.73,4165 h40
  text "Pad" at 3526.1,4165 h40
  text "(Mixed)" at 3930,4165 h40
  text "(Mixed)" at 4663.12,4165 h40
  text "12" at 458.95,4065 h40
  text "28.00mil (0.711mm)" at 898.84,4065 h40
  text "PTH" at 1671.95,4065 h40
  text "Round" at 2019.86,4065 h40
  text "Top Layer - Bottom Layer" at 2519.73,4065 h40
  text "Pad" at 3526.1,4065 h40
  text "(Mixed)" at 3930,4065 h40
  text "(Mixed)" at 4663.12,4065 h40
  text "24" at 458.95,3965 h40
  text "66.93mil (1.700mm)" at 898.84,3965 h40
  text "PTH" at 1671.95,3965 h40
  text "Round" at 2019.86,3965 h40
  text "Top Layer - Bottom Layer" at 2519.73,3965 h40
  text "Pad" at 3526.1,3965 h40
  text "Rounded" at 3930,3965 h40
  text "c260h170m260p0" at 4663.12,3965 h40
  text "44" at 458.95,3865 h40
  text "7.87mil (0.200mm)" at 898.84,3865 h40
  text "PTH" at 1671.95,3865 h40
  text "Round" at 2019.86,3865 h40
  text "Top Layer - Bottom Layer" at 2519.73,3865 h40
  text "Pad" at 3526.1,3865 h40
  text "Rounded" at 3930,3865 h40
  text "(Mixed)" at 4663.12,3865 h40
  text "898" at 458.95,3765 h40
  text "8.00mil (0.203mm)" at 898.84,3765 h40
  text "PTH" at 1671.95,3765 h40
  text "Round" at 2019.86,3765 h40
  text "Top Layer - Bottom Layer" at 2519.73,3765 h40
  text "(Mixed)" at 3526.1,3765 h40
  text "Rounded" at 3930,3765 h40
  text "(Mixed)" at 4663.12,3765 h40
  text "1023 Total" at 458.95,3665 h40
  text "Slot definitions :" at 111.04,3561.68 h40
  text "Routed Path Length" at 808.83,3561.68 h40
  text "= Calculated from tool start centre position to tool end centre position." at 1553.28,3561.68 h40
  text "Hole Length" at 808.83,3488.37 h40
  text "= Routed Path Length + Tool Size = Slot length as defined in the PCB layout" at 1280.03,3488.37 h40
  text ".Layer_Name" at 577,-858.49 h60

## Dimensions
0,100 to 3900,100 on M2 Board Dimensions
100,2716.54 to 100,0 on M2 Board Dimensions
0,-400 to 1000,-400 on M2 Board Dimensions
